VERSION 5.7 ;
  NOWIREEXTENSIONATPIN ON ;
  DIVIDERCHAR "/" ;
  BUSBITCHARS "[]" ;
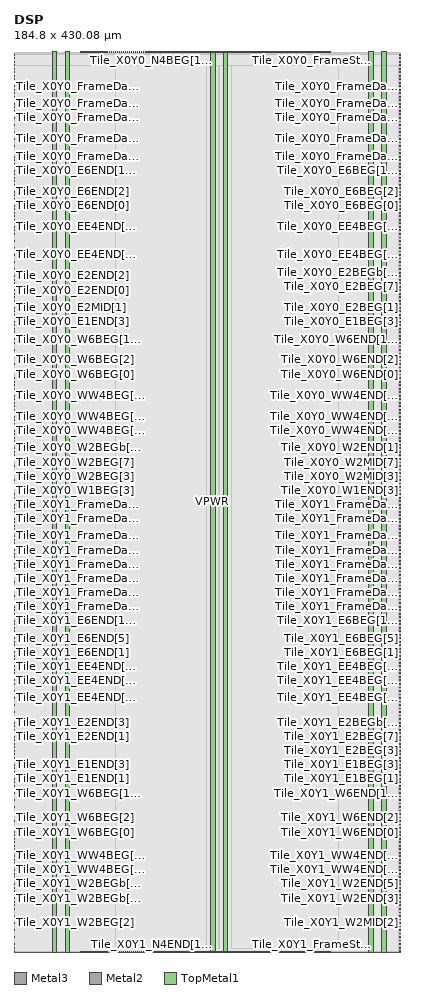
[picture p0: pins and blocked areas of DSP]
MACRO DSP
  CLASS BLOCK ;
  FOREIGN DSP ;
  ORIGIN 0.000 0.000 ;
  SIZE 184.800 BY 430.080 ;
  PIN Tile_X0Y0_E1BEG[0]
    DIRECTION OUTPUT ;
    USE SIGNAL ;
    ANTENNADIFFAREA 0.708600 ;
    PORT
      LAYER Metal3 ;
        RECT 184.400 295.900 184.800 296.300 ;
    END
  END Tile_X0Y0_E1BEG[0]
  PIN Tile_X0Y0_E1BEG[1]
    DIRECTION OUTPUT ;
    USE SIGNAL ;
    ANTENNADIFFAREA 0.708600 ;
    PORT
      LAYER Metal3 ;
        RECT 184.400 297.580 184.800 297.980 ;
    END
  END Tile_X0Y0_E1BEG[1]
  PIN Tile_X0Y0_E1BEG[2]
    DIRECTION OUTPUT ;
    USE SIGNAL ;
    ANTENNADIFFAREA 0.708600 ;
    PORT
      LAYER Metal3 ;
        RECT 184.400 299.260 184.800 299.660 ;
    END
  END Tile_X0Y0_E1BEG[2]
  PIN Tile_X0Y0_E1BEG[3]
    DIRECTION OUTPUT ;
    USE SIGNAL ;
    ANTENNADIFFAREA 0.708600 ;
    PORT
      LAYER Metal3 ;
        RECT 184.400 300.940 184.800 301.340 ;
    END
  END Tile_X0Y0_E1BEG[3]
  PIN Tile_X0Y0_E1END[0]
    DIRECTION INPUT ;
    USE SIGNAL ;
    ANTENNAGATEAREA 0.668200 ;
    PORT
      LAYER Metal3 ;
        RECT 0.000 295.900 0.400 296.300 ;
    END
  END Tile_X0Y0_E1END[0]
  PIN Tile_X0Y0_E1END[1]
    DIRECTION INPUT ;
    USE SIGNAL ;
    ANTENNAGATEAREA 1.834300 ;
    PORT
      LAYER Metal3 ;
        RECT 0.000 297.580 0.400 297.980 ;
    END
  END Tile_X0Y0_E1END[1]
  PIN Tile_X0Y0_E1END[2]
    DIRECTION INPUT ;
    USE SIGNAL ;
    ANTENNAGATEAREA 2.345200 ;
    PORT
      LAYER Metal3 ;
        RECT 0.000 299.260 0.400 299.660 ;
    END
  END Tile_X0Y0_E1END[2]
  PIN Tile_X0Y0_E1END[3]
    DIRECTION INPUT ;
    USE SIGNAL ;
    ANTENNAGATEAREA 1.336400 ;
    PORT
      LAYER Metal3 ;
        RECT 0.000 300.940 0.400 301.340 ;
    END
  END Tile_X0Y0_E1END[3]
  PIN Tile_X0Y0_E2BEG[0]
    DIRECTION OUTPUT ;
    USE SIGNAL ;
    ANTENNADIFFAREA 0.708600 ;
    PORT
      LAYER Metal3 ;
        RECT 184.400 302.620 184.800 303.020 ;
    END
  END Tile_X0Y0_E2BEG[0]
  PIN Tile_X0Y0_E2BEG[1]
    DIRECTION OUTPUT ;
    USE SIGNAL ;
    ANTENNADIFFAREA 0.708600 ;
    PORT
      LAYER Metal3 ;
        RECT 184.400 304.300 184.800 304.700 ;
    END
  END Tile_X0Y0_E2BEG[1]
  PIN Tile_X0Y0_E2BEG[2]
    DIRECTION OUTPUT ;
    USE SIGNAL ;
    ANTENNADIFFAREA 0.708600 ;
    PORT
      LAYER Metal3 ;
        RECT 184.400 305.980 184.800 306.380 ;
    END
  END Tile_X0Y0_E2BEG[2]
  PIN Tile_X0Y0_E2BEG[3]
    DIRECTION OUTPUT ;
    USE SIGNAL ;
    ANTENNADIFFAREA 0.708600 ;
    PORT
      LAYER Metal3 ;
        RECT 184.400 307.660 184.800 308.060 ;
    END
  END Tile_X0Y0_E2BEG[3]
  PIN Tile_X0Y0_E2BEG[4]
    DIRECTION OUTPUT ;
    USE SIGNAL ;
    ANTENNADIFFAREA 0.708600 ;
    PORT
      LAYER Metal3 ;
        RECT 184.400 309.340 184.800 309.740 ;
    END
  END Tile_X0Y0_E2BEG[4]
  PIN Tile_X0Y0_E2BEG[5]
    DIRECTION OUTPUT ;
    USE SIGNAL ;
    ANTENNADIFFAREA 0.708600 ;
    PORT
      LAYER Metal3 ;
        RECT 184.400 311.020 184.800 311.420 ;
    END
  END Tile_X0Y0_E2BEG[5]
  PIN Tile_X0Y0_E2BEG[6]
    DIRECTION OUTPUT ;
    USE SIGNAL ;
    ANTENNADIFFAREA 0.708600 ;
    PORT
      LAYER Metal3 ;
        RECT 184.400 312.700 184.800 313.100 ;
    END
  END Tile_X0Y0_E2BEG[6]
  PIN Tile_X0Y0_E2BEG[7]
    DIRECTION OUTPUT ;
    USE SIGNAL ;
    ANTENNADIFFAREA 0.708600 ;
    PORT
      LAYER Metal3 ;
        RECT 184.400 314.380 184.800 314.780 ;
    END
  END Tile_X0Y0_E2BEG[7]
  PIN Tile_X0Y0_E2BEGb[0]
    DIRECTION OUTPUT ;
    USE SIGNAL ;
    ANTENNADIFFAREA 0.708600 ;
    PORT
      LAYER Metal3 ;
        RECT 184.400 316.060 184.800 316.460 ;
    END
  END Tile_X0Y0_E2BEGb[0]
  PIN Tile_X0Y0_E2BEGb[1]
    DIRECTION OUTPUT ;
    USE SIGNAL ;
    ANTENNADIFFAREA 0.708600 ;
    PORT
      LAYER Metal3 ;
        RECT 184.400 317.740 184.800 318.140 ;
    END
  END Tile_X0Y0_E2BEGb[1]
  PIN Tile_X0Y0_E2BEGb[2]
    DIRECTION OUTPUT ;
    USE SIGNAL ;
    ANTENNADIFFAREA 0.708600 ;
    PORT
      LAYER Metal3 ;
        RECT 184.400 319.420 184.800 319.820 ;
    END
  END Tile_X0Y0_E2BEGb[2]
  PIN Tile_X0Y0_E2BEGb[3]
    DIRECTION OUTPUT ;
    USE SIGNAL ;
    ANTENNADIFFAREA 0.708600 ;
    PORT
      LAYER Metal3 ;
        RECT 184.400 321.100 184.800 321.500 ;
    END
  END Tile_X0Y0_E2BEGb[3]
  PIN Tile_X0Y0_E2BEGb[4]
    DIRECTION OUTPUT ;
    USE SIGNAL ;
    ANTENNADIFFAREA 0.708600 ;
    PORT
      LAYER Metal3 ;
        RECT 184.400 322.780 184.800 323.180 ;
    END
  END Tile_X0Y0_E2BEGb[4]
  PIN Tile_X0Y0_E2BEGb[5]
    DIRECTION OUTPUT ;
    USE SIGNAL ;
    ANTENNADIFFAREA 0.708600 ;
    PORT
      LAYER Metal3 ;
        RECT 184.400 324.460 184.800 324.860 ;
    END
  END Tile_X0Y0_E2BEGb[5]
  PIN Tile_X0Y0_E2BEGb[6]
    DIRECTION OUTPUT ;
    USE SIGNAL ;
    ANTENNADIFFAREA 0.708600 ;
    PORT
      LAYER Metal3 ;
        RECT 184.400 326.140 184.800 326.540 ;
    END
  END Tile_X0Y0_E2BEGb[6]
  PIN Tile_X0Y0_E2BEGb[7]
    DIRECTION OUTPUT ;
    USE SIGNAL ;
    ANTENNADIFFAREA 0.708600 ;
    PORT
      LAYER Metal3 ;
        RECT 184.400 327.820 184.800 328.220 ;
    END
  END Tile_X0Y0_E2BEGb[7]
  PIN Tile_X0Y0_E2END[0]
    DIRECTION INPUT ;
    USE SIGNAL ;
    ANTENNAGATEAREA 0.938600 ;
    PORT
      LAYER Metal3 ;
        RECT 0.000 316.060 0.400 316.460 ;
    END
  END Tile_X0Y0_E2END[0]
  PIN Tile_X0Y0_E2END[1]
    DIRECTION INPUT ;
    USE SIGNAL ;
    ANTENNAGATEAREA 0.894400 ;
    PORT
      LAYER Metal3 ;
        RECT 0.000 317.740 0.400 318.140 ;
    END
  END Tile_X0Y0_E2END[1]
  PIN Tile_X0Y0_E2END[2]
    DIRECTION INPUT ;
    USE SIGNAL ;
    ANTENNAGATEAREA 1.501500 ;
    PORT
      LAYER Metal3 ;
        RECT 0.000 319.420 0.400 319.820 ;
    END
  END Tile_X0Y0_E2END[2]
  PIN Tile_X0Y0_E2END[3]
    DIRECTION INPUT ;
    USE SIGNAL ;
    ANTENNAGATEAREA 1.714700 ;
    PORT
      LAYER Metal3 ;
        RECT 0.000 321.100 0.400 321.500 ;
    END
  END Tile_X0Y0_E2END[3]
  PIN Tile_X0Y0_E2END[4]
    DIRECTION INPUT ;
    USE SIGNAL ;
    ANTENNAGATEAREA 1.066000 ;
    PORT
      LAYER Metal3 ;
        RECT 0.000 322.780 0.400 323.180 ;
    END
  END Tile_X0Y0_E2END[4]
  PIN Tile_X0Y0_E2END[5]
    DIRECTION INPUT ;
    USE SIGNAL ;
    ANTENNAGATEAREA 1.378000 ;
    PORT
      LAYER Metal3 ;
        RECT 0.000 324.460 0.400 324.860 ;
    END
  END Tile_X0Y0_E2END[5]
  PIN Tile_X0Y0_E2END[6]
    DIRECTION INPUT ;
    USE SIGNAL ;
    ANTENNAGATEAREA 1.279200 ;
    PORT
      LAYER Metal3 ;
        RECT 0.000 326.140 0.400 326.540 ;
    END
  END Tile_X0Y0_E2END[6]
  PIN Tile_X0Y0_E2END[7]
    DIRECTION INPUT ;
    USE SIGNAL ;
    ANTENNAGATEAREA 1.180400 ;
    PORT
      LAYER Metal3 ;
        RECT 0.000 327.820 0.400 328.220 ;
    END
  END Tile_X0Y0_E2END[7]
  PIN Tile_X0Y0_E2MID[0]
    DIRECTION INPUT ;
    USE SIGNAL ;
    ANTENNAGATEAREA 0.914700 ;
    PORT
      LAYER Metal3 ;
        RECT 0.000 302.620 0.400 303.020 ;
    END
  END Tile_X0Y0_E2MID[0]
  PIN Tile_X0Y0_E2MID[1]
    DIRECTION INPUT ;
    USE SIGNAL ;
    ANTENNAGATEAREA 0.968500 ;
    PORT
      LAYER Metal3 ;
        RECT 0.000 304.300 0.400 304.700 ;
    END
  END Tile_X0Y0_E2MID[1]
  PIN Tile_X0Y0_E2MID[2]
    DIRECTION INPUT ;
    USE SIGNAL ;
    ANTENNAGATEAREA 0.848900 ;
    PORT
      LAYER Metal3 ;
        RECT 0.000 305.980 0.400 306.380 ;
    END
  END Tile_X0Y0_E2MID[2]
  PIN Tile_X0Y0_E2MID[3]
    DIRECTION INPUT ;
    USE SIGNAL ;
    ANTENNAGATEAREA 1.059500 ;
    PORT
      LAYER Metal3 ;
        RECT 0.000 307.660 0.400 308.060 ;
    END
  END Tile_X0Y0_E2MID[3]
  PIN Tile_X0Y0_E2MID[4]
    DIRECTION INPUT ;
    USE SIGNAL ;
    ANTENNAGATEAREA 4.104100 ;
    ANTENNADIFFAREA 10.077000 ;
    PORT
      LAYER Metal3 ;
        RECT 0.000 309.340 0.400 309.740 ;
    END
  END Tile_X0Y0_E2MID[4]
  PIN Tile_X0Y0_E2MID[5]
    DIRECTION INPUT ;
    USE SIGNAL ;
    ANTENNAGATEAREA 1.127900 ;
    PORT
      LAYER Metal3 ;
        RECT 0.000 311.020 0.400 311.420 ;
    END
  END Tile_X0Y0_E2MID[5]
  PIN Tile_X0Y0_E2MID[6]
    DIRECTION INPUT ;
    USE SIGNAL ;
    ANTENNAGATEAREA 0.848900 ;
    PORT
      LAYER Metal3 ;
        RECT 0.000 312.700 0.400 313.100 ;
    END
  END Tile_X0Y0_E2MID[6]
  PIN Tile_X0Y0_E2MID[7]
    DIRECTION INPUT ;
    USE SIGNAL ;
    ANTENNAGATEAREA 1.062100 ;
    PORT
      LAYER Metal3 ;
        RECT 0.000 314.380 0.400 314.780 ;
    END
  END Tile_X0Y0_E2MID[7]
  PIN Tile_X0Y0_E6BEG[0]
    DIRECTION OUTPUT ;
    USE SIGNAL ;
    ANTENNADIFFAREA 0.708600 ;
    PORT
      LAYER Metal3 ;
        RECT 184.400 356.380 184.800 356.780 ;
    END
  END Tile_X0Y0_E6BEG[0]
  PIN Tile_X0Y0_E6BEG[10]
    DIRECTION OUTPUT ;
    USE SIGNAL ;
    ANTENNADIFFAREA 0.708600 ;
    PORT
      LAYER Metal3 ;
        RECT 184.400 373.180 184.800 373.580 ;
    END
  END Tile_X0Y0_E6BEG[10]
  PIN Tile_X0Y0_E6BEG[11]
    DIRECTION OUTPUT ;
    USE SIGNAL ;
    ANTENNADIFFAREA 0.708600 ;
    PORT
      LAYER Metal3 ;
        RECT 184.400 374.860 184.800 375.260 ;
    END
  END Tile_X0Y0_E6BEG[11]
  PIN Tile_X0Y0_E6BEG[1]
    DIRECTION OUTPUT ;
    USE SIGNAL ;
    ANTENNADIFFAREA 0.708600 ;
    PORT
      LAYER Metal3 ;
        RECT 184.400 358.060 184.800 358.460 ;
    END
  END Tile_X0Y0_E6BEG[1]
  PIN Tile_X0Y0_E6BEG[2]
    DIRECTION OUTPUT ;
    USE SIGNAL ;
    ANTENNADIFFAREA 0.708600 ;
    PORT
      LAYER Metal3 ;
        RECT 184.400 359.740 184.800 360.140 ;
    END
  END Tile_X0Y0_E6BEG[2]
  PIN Tile_X0Y0_E6BEG[3]
    DIRECTION OUTPUT ;
    USE SIGNAL ;
    ANTENNADIFFAREA 0.708600 ;
    PORT
      LAYER Metal3 ;
        RECT 184.400 361.420 184.800 361.820 ;
    END
  END Tile_X0Y0_E6BEG[3]
  PIN Tile_X0Y0_E6BEG[4]
    DIRECTION OUTPUT ;
    USE SIGNAL ;
    ANTENNADIFFAREA 0.708600 ;
    PORT
      LAYER Metal3 ;
        RECT 184.400 363.100 184.800 363.500 ;
    END
  END Tile_X0Y0_E6BEG[4]
  PIN Tile_X0Y0_E6BEG[5]
    DIRECTION OUTPUT ;
    USE SIGNAL ;
    ANTENNADIFFAREA 0.708600 ;
    PORT
      LAYER Metal3 ;
        RECT 184.400 364.780 184.800 365.180 ;
    END
  END Tile_X0Y0_E6BEG[5]
  PIN Tile_X0Y0_E6BEG[6]
    DIRECTION OUTPUT ;
    USE SIGNAL ;
    ANTENNADIFFAREA 0.708600 ;
    PORT
      LAYER Metal3 ;
        RECT 184.400 366.460 184.800 366.860 ;
    END
  END Tile_X0Y0_E6BEG[6]
  PIN Tile_X0Y0_E6BEG[7]
    DIRECTION OUTPUT ;
    USE SIGNAL ;
    ANTENNADIFFAREA 0.708600 ;
    PORT
      LAYER Metal3 ;
        RECT 184.400 368.140 184.800 368.540 ;
    END
  END Tile_X0Y0_E6BEG[7]
  PIN Tile_X0Y0_E6BEG[8]
    DIRECTION OUTPUT ;
    USE SIGNAL ;
    ANTENNADIFFAREA 0.708600 ;
    PORT
      LAYER Metal3 ;
        RECT 184.400 369.820 184.800 370.220 ;
    END
  END Tile_X0Y0_E6BEG[8]
  PIN Tile_X0Y0_E6BEG[9]
    DIRECTION OUTPUT ;
    USE SIGNAL ;
    ANTENNADIFFAREA 0.708600 ;
    PORT
      LAYER Metal3 ;
        RECT 184.400 371.500 184.800 371.900 ;
    END
  END Tile_X0Y0_E6BEG[9]
  PIN Tile_X0Y0_E6END[0]
    DIRECTION INPUT ;
    USE SIGNAL ;
    ANTENNAGATEAREA 2.567500 ;
    PORT
      LAYER Metal3 ;
        RECT 0.000 356.380 0.400 356.780 ;
    END
  END Tile_X0Y0_E6END[0]
  PIN Tile_X0Y0_E6END[10]
    DIRECTION INPUT ;
    USE SIGNAL ;
    ANTENNAGATEAREA 0.789100 ;
    ANTENNADIFFAREA 2.015400 ;
    PORT
      LAYER Metal3 ;
        RECT 0.000 373.180 0.400 373.580 ;
    END
  END Tile_X0Y0_E6END[10]
  PIN Tile_X0Y0_E6END[11]
    DIRECTION INPUT ;
    USE SIGNAL ;
    ANTENNAGATEAREA 0.180700 ;
    PORT
      LAYER Metal3 ;
        RECT 0.000 374.860 0.400 375.260 ;
    END
  END Tile_X0Y0_E6END[11]
  PIN Tile_X0Y0_E6END[1]
    DIRECTION INPUT ;
    USE SIGNAL ;
    ANTENNAGATEAREA 2.764900 ;
    PORT
      LAYER Metal3 ;
        RECT 0.000 358.060 0.400 358.460 ;
    END
  END Tile_X0Y0_E6END[1]
  PIN Tile_X0Y0_E6END[2]
    DIRECTION INPUT ;
    USE SIGNAL ;
    ANTENNAGATEAREA 0.180700 ;
    PORT
      LAYER Metal3 ;
        RECT 0.000 359.740 0.400 360.140 ;
    END
  END Tile_X0Y0_E6END[2]
  PIN Tile_X0Y0_E6END[3]
    DIRECTION INPUT ;
    USE SIGNAL ;
    ANTENNAGATEAREA 0.789100 ;
    ANTENNADIFFAREA 2.015400 ;
    PORT
      LAYER Metal3 ;
        RECT 0.000 361.420 0.400 361.820 ;
    END
  END Tile_X0Y0_E6END[3]
  PIN Tile_X0Y0_E6END[4]
    DIRECTION INPUT ;
    USE SIGNAL ;
    ANTENNAGATEAREA 0.789100 ;
    ANTENNADIFFAREA 2.015400 ;
    PORT
      LAYER Metal3 ;
        RECT 0.000 363.100 0.400 363.500 ;
    END
  END Tile_X0Y0_E6END[4]
  PIN Tile_X0Y0_E6END[5]
    DIRECTION INPUT ;
    USE SIGNAL ;
    ANTENNAGATEAREA 0.789100 ;
    ANTENNADIFFAREA 2.015400 ;
    PORT
      LAYER Metal3 ;
        RECT 0.000 364.780 0.400 365.180 ;
    END
  END Tile_X0Y0_E6END[5]
  PIN Tile_X0Y0_E6END[6]
    DIRECTION INPUT ;
    USE SIGNAL ;
    ANTENNAGATEAREA 0.180700 ;
    PORT
      LAYER Metal3 ;
        RECT 0.000 366.460 0.400 366.860 ;
    END
  END Tile_X0Y0_E6END[6]
  PIN Tile_X0Y0_E6END[7]
    DIRECTION INPUT ;
    USE SIGNAL ;
    ANTENNAGATEAREA 0.180700 ;
    PORT
      LAYER Metal3 ;
        RECT 0.000 368.140 0.400 368.540 ;
    END
  END Tile_X0Y0_E6END[7]
  PIN Tile_X0Y0_E6END[8]
    DIRECTION INPUT ;
    USE SIGNAL ;
    ANTENNAGATEAREA 0.789100 ;
    ANTENNADIFFAREA 2.015400 ;
    PORT
      LAYER Metal3 ;
        RECT 0.000 369.820 0.400 370.220 ;
    END
  END Tile_X0Y0_E6END[8]
  PIN Tile_X0Y0_E6END[9]
    DIRECTION INPUT ;
    USE SIGNAL ;
    ANTENNAGATEAREA 0.180700 ;
    PORT
      LAYER Metal3 ;
        RECT 0.000 371.500 0.400 371.900 ;
    END
  END Tile_X0Y0_E6END[9]
  PIN Tile_X0Y0_EE4BEG[0]
    DIRECTION OUTPUT ;
    USE SIGNAL ;
    ANTENNADIFFAREA 0.708600 ;
    PORT
      LAYER Metal3 ;
        RECT 184.400 329.500 184.800 329.900 ;
    END
  END Tile_X0Y0_EE4BEG[0]
  PIN Tile_X0Y0_EE4BEG[10]
    DIRECTION OUTPUT ;
    USE SIGNAL ;
    ANTENNADIFFAREA 0.708600 ;
    PORT
      LAYER Metal3 ;
        RECT 184.400 346.300 184.800 346.700 ;
    END
  END Tile_X0Y0_EE4BEG[10]
  PIN Tile_X0Y0_EE4BEG[11]
    DIRECTION OUTPUT ;
    USE SIGNAL ;
    ANTENNADIFFAREA 0.708600 ;
    PORT
      LAYER Metal3 ;
        RECT 184.400 347.980 184.800 348.380 ;
    END
  END Tile_X0Y0_EE4BEG[11]
  PIN Tile_X0Y0_EE4BEG[12]
    DIRECTION OUTPUT ;
    USE SIGNAL ;
    ANTENNADIFFAREA 0.708600 ;
    PORT
      LAYER Metal3 ;
        RECT 184.400 349.660 184.800 350.060 ;
    END
  END Tile_X0Y0_EE4BEG[12]
  PIN Tile_X0Y0_EE4BEG[13]
    DIRECTION OUTPUT ;
    USE SIGNAL ;
    ANTENNADIFFAREA 0.708600 ;
    PORT
      LAYER Metal3 ;
        RECT 184.400 351.340 184.800 351.740 ;
    END
  END Tile_X0Y0_EE4BEG[13]
  PIN Tile_X0Y0_EE4BEG[14]
    DIRECTION OUTPUT ;
    USE SIGNAL ;
    ANTENNADIFFAREA 0.708600 ;
    PORT
      LAYER Metal3 ;
        RECT 184.400 353.020 184.800 353.420 ;
    END
  END Tile_X0Y0_EE4BEG[14]
  PIN Tile_X0Y0_EE4BEG[15]
    DIRECTION OUTPUT ;
    USE SIGNAL ;
    ANTENNADIFFAREA 0.708600 ;
    PORT
      LAYER Metal3 ;
        RECT 184.400 354.700 184.800 355.100 ;
    END
  END Tile_X0Y0_EE4BEG[15]
  PIN Tile_X0Y0_EE4BEG[1]
    DIRECTION OUTPUT ;
    USE SIGNAL ;
    ANTENNADIFFAREA 0.708600 ;
    PORT
      LAYER Metal3 ;
        RECT 184.400 331.180 184.800 331.580 ;
    END
  END Tile_X0Y0_EE4BEG[1]
  PIN Tile_X0Y0_EE4BEG[2]
    DIRECTION OUTPUT ;
    USE SIGNAL ;
    ANTENNADIFFAREA 0.708600 ;
    PORT
      LAYER Metal3 ;
        RECT 184.400 332.860 184.800 333.260 ;
    END
  END Tile_X0Y0_EE4BEG[2]
  PIN Tile_X0Y0_EE4BEG[3]
    DIRECTION OUTPUT ;
    USE SIGNAL ;
    ANTENNADIFFAREA 0.708600 ;
    PORT
      LAYER Metal3 ;
        RECT 184.400 334.540 184.800 334.940 ;
    END
  END Tile_X0Y0_EE4BEG[3]
  PIN Tile_X0Y0_EE4BEG[4]
    DIRECTION OUTPUT ;
    USE SIGNAL ;
    ANTENNADIFFAREA 0.708600 ;
    PORT
      LAYER Metal3 ;
        RECT 184.400 336.220 184.800 336.620 ;
    END
  END Tile_X0Y0_EE4BEG[4]
  PIN Tile_X0Y0_EE4BEG[5]
    DIRECTION OUTPUT ;
    USE SIGNAL ;
    ANTENNADIFFAREA 0.708600 ;
    PORT
      LAYER Metal3 ;
        RECT 184.400 337.900 184.800 338.300 ;
    END
  END Tile_X0Y0_EE4BEG[5]
  PIN Tile_X0Y0_EE4BEG[6]
    DIRECTION OUTPUT ;
    USE SIGNAL ;
    ANTENNADIFFAREA 0.708600 ;
    PORT
      LAYER Metal3 ;
        RECT 184.400 339.580 184.800 339.980 ;
    END
  END Tile_X0Y0_EE4BEG[6]
  PIN Tile_X0Y0_EE4BEG[7]
    DIRECTION OUTPUT ;
    USE SIGNAL ;
    ANTENNADIFFAREA 0.708600 ;
    PORT
      LAYER Metal3 ;
        RECT 184.400 341.260 184.800 341.660 ;
    END
  END Tile_X0Y0_EE4BEG[7]
  PIN Tile_X0Y0_EE4BEG[8]
    DIRECTION OUTPUT ;
    USE SIGNAL ;
    ANTENNADIFFAREA 0.708600 ;
    PORT
      LAYER Metal3 ;
        RECT 184.400 342.940 184.800 343.340 ;
    END
  END Tile_X0Y0_EE4BEG[8]
  PIN Tile_X0Y0_EE4BEG[9]
    DIRECTION OUTPUT ;
    USE SIGNAL ;
    ANTENNADIFFAREA 0.708600 ;
    PORT
      LAYER Metal3 ;
        RECT 184.400 344.620 184.800 345.020 ;
    END
  END Tile_X0Y0_EE4BEG[9]
  PIN Tile_X0Y0_EE4END[0]
    DIRECTION INPUT ;
    USE SIGNAL ;
    ANTENNAGATEAREA 0.696800 ;
    PORT
      LAYER Metal3 ;
        RECT 0.000 329.500 0.400 329.900 ;
    END
  END Tile_X0Y0_EE4END[0]
  PIN Tile_X0Y0_EE4END[10]
    DIRECTION INPUT ;
    USE SIGNAL ;
    ANTENNAGATEAREA 0.180700 ;
    PORT
      LAYER Metal3 ;
        RECT 0.000 346.300 0.400 346.700 ;
    END
  END Tile_X0Y0_EE4END[10]
  PIN Tile_X0Y0_EE4END[11]
    DIRECTION INPUT ;
    USE SIGNAL ;
    ANTENNAGATEAREA 0.789100 ;
    ANTENNADIFFAREA 2.015400 ;
    PORT
      LAYER Metal3 ;
        RECT 0.000 347.980 0.400 348.380 ;
    END
  END Tile_X0Y0_EE4END[11]
  PIN Tile_X0Y0_EE4END[12]
    DIRECTION INPUT ;
    USE SIGNAL ;
    ANTENNAGATEAREA 0.789100 ;
    ANTENNADIFFAREA 2.015400 ;
    PORT
      LAYER Metal3 ;
        RECT 0.000 349.660 0.400 350.060 ;
    END
  END Tile_X0Y0_EE4END[12]
  PIN Tile_X0Y0_EE4END[13]
    DIRECTION INPUT ;
    USE SIGNAL ;
    ANTENNAGATEAREA 0.789100 ;
    ANTENNADIFFAREA 2.015400 ;
    PORT
      LAYER Metal3 ;
        RECT 0.000 351.340 0.400 351.740 ;
    END
  END Tile_X0Y0_EE4END[13]
  PIN Tile_X0Y0_EE4END[14]
    DIRECTION INPUT ;
    USE SIGNAL ;
    ANTENNAGATEAREA 0.180700 ;
    PORT
      LAYER Metal3 ;
        RECT 0.000 353.020 0.400 353.420 ;
    END
  END Tile_X0Y0_EE4END[14]
  PIN Tile_X0Y0_EE4END[15]
    DIRECTION INPUT ;
    USE SIGNAL ;
    ANTENNAGATEAREA 0.180700 ;
    PORT
      LAYER Metal3 ;
        RECT 0.000 354.700 0.400 355.100 ;
    END
  END Tile_X0Y0_EE4END[15]
  PIN Tile_X0Y0_EE4END[1]
    DIRECTION INPUT ;
    USE SIGNAL ;
    ANTENNAGATEAREA 0.681200 ;
    PORT
      LAYER Metal3 ;
        RECT 0.000 331.180 0.400 331.580 ;
    END
  END Tile_X0Y0_EE4END[1]
  PIN Tile_X0Y0_EE4END[2]
    DIRECTION INPUT ;
    USE SIGNAL ;
    ANTENNAGATEAREA 0.705400 ;
    PORT
      LAYER Metal3 ;
        RECT 0.000 332.860 0.400 333.260 ;
    END
  END Tile_X0Y0_EE4END[2]
  PIN Tile_X0Y0_EE4END[3]
    DIRECTION INPUT ;
    USE SIGNAL ;
    ANTENNAGATEAREA 0.393900 ;
    PORT
      LAYER Metal3 ;
        RECT 0.000 334.540 0.400 334.940 ;
    END
  END Tile_X0Y0_EE4END[3]
  PIN Tile_X0Y0_EE4END[4]
    DIRECTION INPUT ;
    USE SIGNAL ;
    ANTENNAGATEAREA 0.180700 ;
    PORT
      LAYER Metal3 ;
        RECT 0.000 336.220 0.400 336.620 ;
    END
  END Tile_X0Y0_EE4END[4]
  PIN Tile_X0Y0_EE4END[5]
    DIRECTION INPUT ;
    USE SIGNAL ;
    ANTENNAGATEAREA 0.180700 ;
    PORT
      LAYER Metal3 ;
        RECT 0.000 337.900 0.400 338.300 ;
    END
  END Tile_X0Y0_EE4END[5]
  PIN Tile_X0Y0_EE4END[6]
    DIRECTION INPUT ;
    USE SIGNAL ;
    ANTENNAGATEAREA 0.180700 ;
    PORT
      LAYER Metal3 ;
        RECT 0.000 339.580 0.400 339.980 ;
    END
  END Tile_X0Y0_EE4END[6]
  PIN Tile_X0Y0_EE4END[7]
    DIRECTION INPUT ;
    USE SIGNAL ;
    ANTENNAGATEAREA 0.180700 ;
    PORT
      LAYER Metal3 ;
        RECT 0.000 341.260 0.400 341.660 ;
    END
  END Tile_X0Y0_EE4END[7]
  PIN Tile_X0Y0_EE4END[8]
    DIRECTION INPUT ;
    USE SIGNAL ;
    ANTENNAGATEAREA 0.789100 ;
    ANTENNADIFFAREA 2.015400 ;
    PORT
      LAYER Metal3 ;
        RECT 0.000 342.940 0.400 343.340 ;
    END
  END Tile_X0Y0_EE4END[8]
  PIN Tile_X0Y0_EE4END[9]
    DIRECTION INPUT ;
    USE SIGNAL ;
    ANTENNAGATEAREA 0.180700 ;
    PORT
      LAYER Metal3 ;
        RECT 0.000 344.620 0.400 345.020 ;
    END
  END Tile_X0Y0_EE4END[9]
  PIN Tile_X0Y0_FrameData[0]
    DIRECTION INPUT ;
    USE SIGNAL ;
    ANTENNAGATEAREA 2.349100 ;
    PORT
      LAYER Metal3 ;
        RECT 0.000 376.540 0.400 376.940 ;
    END
  END Tile_X0Y0_FrameData[0]
  PIN Tile_X0Y0_FrameData[10]
    DIRECTION INPUT ;
    USE SIGNAL ;
    ANTENNAGATEAREA 2.529800 ;
    PORT
      LAYER Metal3 ;
        RECT 0.000 393.340 0.400 393.740 ;
    END
  END Tile_X0Y0_FrameData[10]
  PIN Tile_X0Y0_FrameData[11]
    DIRECTION INPUT ;
    USE SIGNAL ;
    ANTENNAGATEAREA 2.529800 ;
    PORT
      LAYER Metal3 ;
        RECT 0.000 395.020 0.400 395.420 ;
    END
  END Tile_X0Y0_FrameData[11]
  PIN Tile_X0Y0_FrameData[12]
    DIRECTION INPUT ;
    USE SIGNAL ;
    ANTENNAGATEAREA 2.529800 ;
    PORT
      LAYER Metal3 ;
        RECT 0.000 396.700 0.400 397.100 ;
    END
  END Tile_X0Y0_FrameData[12]
  PIN Tile_X0Y0_FrameData[13]
    DIRECTION INPUT ;
    USE SIGNAL ;
    ANTENNAGATEAREA 2.529800 ;
    PORT
      LAYER Metal3 ;
        RECT 0.000 398.380 0.400 398.780 ;
    END
  END Tile_X0Y0_FrameData[13]
  PIN Tile_X0Y0_FrameData[14]
    DIRECTION INPUT ;
    USE SIGNAL ;
    ANTENNAGATEAREA 2.529800 ;
    PORT
      LAYER Metal3 ;
        RECT 0.000 400.060 0.400 400.460 ;
    END
  END Tile_X0Y0_FrameData[14]
  PIN Tile_X0Y0_FrameData[15]
    DIRECTION INPUT ;
    USE SIGNAL ;
    ANTENNAGATEAREA 2.529800 ;
    PORT
      LAYER Metal3 ;
        RECT 0.000 401.740 0.400 402.140 ;
    END
  END Tile_X0Y0_FrameData[15]
  PIN Tile_X0Y0_FrameData[16]
    DIRECTION INPUT ;
    USE SIGNAL ;
    ANTENNAGATEAREA 2.529800 ;
    PORT
      LAYER Metal3 ;
        RECT 0.000 403.420 0.400 403.820 ;
    END
  END Tile_X0Y0_FrameData[16]
  PIN Tile_X0Y0_FrameData[17]
    DIRECTION INPUT ;
    USE SIGNAL ;
    ANTENNAGATEAREA 2.529800 ;
    PORT
      LAYER Metal3 ;
        RECT 0.000 405.100 0.400 405.500 ;
    END
  END Tile_X0Y0_FrameData[17]
  PIN Tile_X0Y0_FrameData[18]
    DIRECTION INPUT ;
    USE SIGNAL ;
    ANTENNAGATEAREA 2.529800 ;
    PORT
      LAYER Metal3 ;
        RECT 0.000 406.780 0.400 407.180 ;
    END
  END Tile_X0Y0_FrameData[18]
  PIN Tile_X0Y0_FrameData[19]
    DIRECTION INPUT ;
    USE SIGNAL ;
    ANTENNAGATEAREA 2.529800 ;
    PORT
      LAYER Metal3 ;
        RECT 0.000 408.460 0.400 408.860 ;
    END
  END Tile_X0Y0_FrameData[19]
  PIN Tile_X0Y0_FrameData[1]
    DIRECTION INPUT ;
    USE SIGNAL ;
    ANTENNAGATEAREA 2.349100 ;
    PORT
      LAYER Metal3 ;
        RECT 0.000 378.220 0.400 378.620 ;
    END
  END Tile_X0Y0_FrameData[1]
  PIN Tile_X0Y0_FrameData[20]
    DIRECTION INPUT ;
    USE SIGNAL ;
    ANTENNAGATEAREA 2.529800 ;
    PORT
      LAYER Metal3 ;
        RECT 0.000 410.140 0.400 410.540 ;
    END
  END Tile_X0Y0_FrameData[20]
  PIN Tile_X0Y0_FrameData[21]
    DIRECTION INPUT ;
    USE SIGNAL ;
    ANTENNAGATEAREA 2.529800 ;
    PORT
      LAYER Metal3 ;
        RECT 0.000 411.820 0.400 412.220 ;
    END
  END Tile_X0Y0_FrameData[21]
  PIN Tile_X0Y0_FrameData[22]
    DIRECTION INPUT ;
    USE SIGNAL ;
    ANTENNAGATEAREA 2.529800 ;
    PORT
      LAYER Metal3 ;
        RECT 0.000 413.500 0.400 413.900 ;
    END
  END Tile_X0Y0_FrameData[22]
  PIN Tile_X0Y0_FrameData[23]
    DIRECTION INPUT ;
    USE SIGNAL ;
    ANTENNAGATEAREA 2.529800 ;
    PORT
      LAYER Metal3 ;
        RECT 0.000 415.180 0.400 415.580 ;
    END
  END Tile_X0Y0_FrameData[23]
  PIN Tile_X0Y0_FrameData[24]
    DIRECTION INPUT ;
    USE SIGNAL ;
    ANTENNAGATEAREA 2.529800 ;
    PORT
      LAYER Metal3 ;
        RECT 0.000 416.860 0.400 417.260 ;
    END
  END Tile_X0Y0_FrameData[24]
  PIN Tile_X0Y0_FrameData[25]
    DIRECTION INPUT ;
    USE SIGNAL ;
    ANTENNAGATEAREA 2.529800 ;
    PORT
      LAYER Metal3 ;
        RECT 0.000 418.540 0.400 418.940 ;
    END
  END Tile_X0Y0_FrameData[25]
  PIN Tile_X0Y0_FrameData[26]
    DIRECTION INPUT ;
    USE SIGNAL ;
    ANTENNAGATEAREA 2.529800 ;
    PORT
      LAYER Metal3 ;
        RECT 0.000 420.220 0.400 420.620 ;
    END
  END Tile_X0Y0_FrameData[26]
  PIN Tile_X0Y0_FrameData[27]
    DIRECTION INPUT ;
    USE SIGNAL ;
    ANTENNAGATEAREA 2.529800 ;
    PORT
      LAYER Metal3 ;
        RECT 0.000 421.900 0.400 422.300 ;
    END
  END Tile_X0Y0_FrameData[27]
  PIN Tile_X0Y0_FrameData[28]
    DIRECTION INPUT ;
    USE SIGNAL ;
    ANTENNAGATEAREA 2.529800 ;
    PORT
      LAYER Metal3 ;
        RECT 0.000 423.580 0.400 423.980 ;
    END
  END Tile_X0Y0_FrameData[28]
  PIN Tile_X0Y0_FrameData[29]
    DIRECTION INPUT ;
    USE SIGNAL ;
    ANTENNAGATEAREA 2.529800 ;
    PORT
      LAYER Metal3 ;
        RECT 0.000 425.260 0.400 425.660 ;
    END
  END Tile_X0Y0_FrameData[29]
  PIN Tile_X0Y0_FrameData[2]
    DIRECTION INPUT ;
    USE SIGNAL ;
    ANTENNAGATEAREA 2.349100 ;
    PORT
      LAYER Metal3 ;
        RECT 0.000 379.900 0.400 380.300 ;
    END
  END Tile_X0Y0_FrameData[2]
  PIN Tile_X0Y0_FrameData[30]
    DIRECTION INPUT ;
    USE SIGNAL ;
    ANTENNAGATEAREA 2.529800 ;
    PORT
      LAYER Metal3 ;
        RECT 0.000 426.940 0.400 427.340 ;
    END
  END Tile_X0Y0_FrameData[30]
  PIN Tile_X0Y0_FrameData[31]
    DIRECTION INPUT ;
    USE SIGNAL ;
    ANTENNAGATEAREA 2.529800 ;
    PORT
      LAYER Metal3 ;
        RECT 0.000 428.620 0.400 429.020 ;
    END
  END Tile_X0Y0_FrameData[31]
  PIN Tile_X0Y0_FrameData[3]
    DIRECTION INPUT ;
    USE SIGNAL ;
    ANTENNAGATEAREA 2.349100 ;
    PORT
      LAYER Metal3 ;
        RECT 0.000 381.580 0.400 381.980 ;
    END
  END Tile_X0Y0_FrameData[3]
  PIN Tile_X0Y0_FrameData[4]
    DIRECTION INPUT ;
    USE SIGNAL ;
    ANTENNAGATEAREA 2.349100 ;
    PORT
      LAYER Metal3 ;
        RECT 0.000 383.260 0.400 383.660 ;
    END
  END Tile_X0Y0_FrameData[4]
  PIN Tile_X0Y0_FrameData[5]
    DIRECTION INPUT ;
    USE SIGNAL ;
    ANTENNAGATEAREA 2.349100 ;
    PORT
      LAYER Metal3 ;
        RECT 0.000 384.940 0.400 385.340 ;
    END
  END Tile_X0Y0_FrameData[5]
  PIN Tile_X0Y0_FrameData[6]
    DIRECTION INPUT ;
    USE SIGNAL ;
    ANTENNAGATEAREA 17.559099 ;
    ANTENNADIFFAREA 50.384998 ;
    PORT
      LAYER Metal3 ;
        RECT 0.000 386.620 0.400 387.020 ;
    END
  END Tile_X0Y0_FrameData[6]
  PIN Tile_X0Y0_FrameData[7]
    DIRECTION INPUT ;
    USE SIGNAL ;
    ANTENNAGATEAREA 2.349100 ;
    PORT
      LAYER Metal3 ;
        RECT 0.000 388.300 0.400 388.700 ;
    END
  END Tile_X0Y0_FrameData[7]
  PIN Tile_X0Y0_FrameData[8]
    DIRECTION INPUT ;
    USE SIGNAL ;
    ANTENNAGATEAREA 2.349100 ;
    PORT
      LAYER Metal3 ;
        RECT 0.000 389.980 0.400 390.380 ;
    END
  END Tile_X0Y0_FrameData[8]
  PIN Tile_X0Y0_FrameData[9]
    DIRECTION INPUT ;
    USE SIGNAL ;
    ANTENNAGATEAREA 2.349100 ;
    PORT
      LAYER Metal3 ;
        RECT 0.000 391.660 0.400 392.060 ;
    END
  END Tile_X0Y0_FrameData[9]
  PIN Tile_X0Y0_FrameData_O[0]
    DIRECTION OUTPUT ;
    USE SIGNAL ;
    ANTENNADIFFAREA 0.708600 ;
    PORT
      LAYER Metal3 ;
        RECT 184.400 376.540 184.800 376.940 ;
    END
  END Tile_X0Y0_FrameData_O[0]
  PIN Tile_X0Y0_FrameData_O[10]
    DIRECTION OUTPUT ;
    USE SIGNAL ;
    ANTENNADIFFAREA 0.708600 ;
    PORT
      LAYER Metal3 ;
        RECT 184.400 393.340 184.800 393.740 ;
    END
  END Tile_X0Y0_FrameData_O[10]
  PIN Tile_X0Y0_FrameData_O[11]
    DIRECTION OUTPUT ;
    USE SIGNAL ;
    ANTENNADIFFAREA 0.708600 ;
    PORT
      LAYER Metal3 ;
        RECT 184.400 395.020 184.800 395.420 ;
    END
  END Tile_X0Y0_FrameData_O[11]
  PIN Tile_X0Y0_FrameData_O[12]
    DIRECTION OUTPUT ;
    USE SIGNAL ;
    ANTENNADIFFAREA 0.708600 ;
    PORT
      LAYER Metal3 ;
        RECT 184.400 396.700 184.800 397.100 ;
    END
  END Tile_X0Y0_FrameData_O[12]
  PIN Tile_X0Y0_FrameData_O[13]
    DIRECTION OUTPUT ;
    USE SIGNAL ;
    ANTENNADIFFAREA 0.708600 ;
    PORT
      LAYER Metal3 ;
        RECT 184.400 398.380 184.800 398.780 ;
    END
  END Tile_X0Y0_FrameData_O[13]
  PIN Tile_X0Y0_FrameData_O[14]
    DIRECTION OUTPUT ;
    USE SIGNAL ;
    ANTENNADIFFAREA 0.708600 ;
    PORT
      LAYER Metal3 ;
        RECT 184.400 400.060 184.800 400.460 ;
    END
  END Tile_X0Y0_FrameData_O[14]
  PIN Tile_X0Y0_FrameData_O[15]
    DIRECTION OUTPUT ;
    USE SIGNAL ;
    ANTENNADIFFAREA 0.708600 ;
    PORT
      LAYER Metal3 ;
        RECT 184.400 401.740 184.800 402.140 ;
    END
  END Tile_X0Y0_FrameData_O[15]
  PIN Tile_X0Y0_FrameData_O[16]
    DIRECTION OUTPUT ;
    USE SIGNAL ;
    ANTENNADIFFAREA 0.708600 ;
    PORT
      LAYER Metal3 ;
        RECT 184.400 403.420 184.800 403.820 ;
    END
  END Tile_X0Y0_FrameData_O[16]
  PIN Tile_X0Y0_FrameData_O[17]
    DIRECTION OUTPUT ;
    USE SIGNAL ;
    ANTENNADIFFAREA 0.708600 ;
    PORT
      LAYER Metal3 ;
        RECT 184.400 405.100 184.800 405.500 ;
    END
  END Tile_X0Y0_FrameData_O[17]
  PIN Tile_X0Y0_FrameData_O[18]
    DIRECTION OUTPUT ;
    USE SIGNAL ;
    ANTENNADIFFAREA 0.708600 ;
    PORT
      LAYER Metal3 ;
        RECT 184.400 406.780 184.800 407.180 ;
    END
  END Tile_X0Y0_FrameData_O[18]
  PIN Tile_X0Y0_FrameData_O[19]
    DIRECTION OUTPUT ;
    USE SIGNAL ;
    ANTENNADIFFAREA 0.708600 ;
    PORT
      LAYER Metal3 ;
        RECT 184.400 408.460 184.800 408.860 ;
    END
  END Tile_X0Y0_FrameData_O[19]
  PIN Tile_X0Y0_FrameData_O[1]
    DIRECTION OUTPUT ;
    USE SIGNAL ;
    ANTENNADIFFAREA 0.708600 ;
    PORT
      LAYER Metal3 ;
        RECT 184.400 378.220 184.800 378.620 ;
    END
  END Tile_X0Y0_FrameData_O[1]
  PIN Tile_X0Y0_FrameData_O[20]
    DIRECTION OUTPUT ;
    USE SIGNAL ;
    ANTENNADIFFAREA 0.708600 ;
    PORT
      LAYER Metal3 ;
        RECT 184.400 410.140 184.800 410.540 ;
    END
  END Tile_X0Y0_FrameData_O[20]
  PIN Tile_X0Y0_FrameData_O[21]
    DIRECTION OUTPUT ;
    USE SIGNAL ;
    ANTENNADIFFAREA 0.708600 ;
    PORT
      LAYER Metal3 ;
        RECT 184.400 411.820 184.800 412.220 ;
    END
  END Tile_X0Y0_FrameData_O[21]
  PIN Tile_X0Y0_FrameData_O[22]
    DIRECTION OUTPUT ;
    USE SIGNAL ;
    ANTENNADIFFAREA 0.708600 ;
    PORT
      LAYER Metal3 ;
        RECT 184.400 413.500 184.800 413.900 ;
    END
  END Tile_X0Y0_FrameData_O[22]
  PIN Tile_X0Y0_FrameData_O[23]
    DIRECTION OUTPUT ;
    USE SIGNAL ;
    ANTENNADIFFAREA 0.708600 ;
    PORT
      LAYER Metal3 ;
        RECT 184.400 415.180 184.800 415.580 ;
    END
  END Tile_X0Y0_FrameData_O[23]
  PIN Tile_X0Y0_FrameData_O[24]
    DIRECTION OUTPUT ;
    USE SIGNAL ;
    ANTENNADIFFAREA 0.708600 ;
    PORT
      LAYER Metal3 ;
        RECT 184.400 416.860 184.800 417.260 ;
    END
  END Tile_X0Y0_FrameData_O[24]
  PIN Tile_X0Y0_FrameData_O[25]
    DIRECTION OUTPUT ;
    USE SIGNAL ;
    ANTENNADIFFAREA 0.708600 ;
    PORT
      LAYER Metal3 ;
        RECT 184.400 418.540 184.800 418.940 ;
    END
  END Tile_X0Y0_FrameData_O[25]
  PIN Tile_X0Y0_FrameData_O[26]
    DIRECTION OUTPUT ;
    USE SIGNAL ;
    ANTENNADIFFAREA 0.708600 ;
    PORT
      LAYER Metal3 ;
        RECT 184.400 420.220 184.800 420.620 ;
    END
  END Tile_X0Y0_FrameData_O[26]
  PIN Tile_X0Y0_FrameData_O[27]
    DIRECTION OUTPUT ;
    USE SIGNAL ;
    ANTENNADIFFAREA 0.708600 ;
    PORT
      LAYER Metal3 ;
        RECT 184.400 421.900 184.800 422.300 ;
    END
  END Tile_X0Y0_FrameData_O[27]
  PIN Tile_X0Y0_FrameData_O[28]
    DIRECTION OUTPUT ;
    USE SIGNAL ;
    ANTENNADIFFAREA 0.708600 ;
    PORT
      LAYER Metal3 ;
        RECT 184.400 423.580 184.800 423.980 ;
    END
  END Tile_X0Y0_FrameData_O[28]
  PIN Tile_X0Y0_FrameData_O[29]
    DIRECTION OUTPUT ;
    USE SIGNAL ;
    ANTENNADIFFAREA 0.708600 ;
    PORT
      LAYER Metal3 ;
        RECT 184.400 425.260 184.800 425.660 ;
    END
  END Tile_X0Y0_FrameData_O[29]
  PIN Tile_X0Y0_FrameData_O[2]
    DIRECTION OUTPUT ;
    USE SIGNAL ;
    ANTENNADIFFAREA 0.708600 ;
    PORT
      LAYER Metal3 ;
        RECT 184.400 379.900 184.800 380.300 ;
    END
  END Tile_X0Y0_FrameData_O[2]
  PIN Tile_X0Y0_FrameData_O[30]
    DIRECTION OUTPUT ;
    USE SIGNAL ;
    ANTENNADIFFAREA 0.708600 ;
    PORT
      LAYER Metal3 ;
        RECT 184.400 426.940 184.800 427.340 ;
    END
  END Tile_X0Y0_FrameData_O[30]
  PIN Tile_X0Y0_FrameData_O[31]
    DIRECTION OUTPUT ;
    USE SIGNAL ;
    ANTENNADIFFAREA 0.708600 ;
    PORT
      LAYER Metal3 ;
        RECT 184.400 428.620 184.800 429.020 ;
    END
  END Tile_X0Y0_FrameData_O[31]
  PIN Tile_X0Y0_FrameData_O[3]
    DIRECTION OUTPUT ;
    USE SIGNAL ;
    ANTENNADIFFAREA 0.708600 ;
    PORT
      LAYER Metal3 ;
        RECT 184.400 381.580 184.800 381.980 ;
    END
  END Tile_X0Y0_FrameData_O[3]
  PIN Tile_X0Y0_FrameData_O[4]
    DIRECTION OUTPUT ;
    USE SIGNAL ;
    ANTENNADIFFAREA 0.708600 ;
    PORT
      LAYER Metal3 ;
        RECT 184.400 383.260 184.800 383.660 ;
    END
  END Tile_X0Y0_FrameData_O[4]
  PIN Tile_X0Y0_FrameData_O[5]
    DIRECTION OUTPUT ;
    USE SIGNAL ;
    ANTENNADIFFAREA 0.708600 ;
    PORT
      LAYER Metal3 ;
        RECT 184.400 384.940 184.800 385.340 ;
    END
  END Tile_X0Y0_FrameData_O[5]
  PIN Tile_X0Y0_FrameData_O[6]
    DIRECTION OUTPUT ;
    USE SIGNAL ;
    ANTENNADIFFAREA 0.708600 ;
    PORT
      LAYER Metal3 ;
        RECT 184.400 386.620 184.800 387.020 ;
    END
  END Tile_X0Y0_FrameData_O[6]
  PIN Tile_X0Y0_FrameData_O[7]
    DIRECTION OUTPUT ;
    USE SIGNAL ;
    ANTENNADIFFAREA 0.708600 ;
    PORT
      LAYER Metal3 ;
        RECT 184.400 388.300 184.800 388.700 ;
    END
  END Tile_X0Y0_FrameData_O[7]
  PIN Tile_X0Y0_FrameData_O[8]
    DIRECTION OUTPUT ;
    USE SIGNAL ;
    ANTENNADIFFAREA 0.708600 ;
    PORT
      LAYER Metal3 ;
        RECT 184.400 389.980 184.800 390.380 ;
    END
  END Tile_X0Y0_FrameData_O[8]
  PIN Tile_X0Y0_FrameData_O[9]
    DIRECTION OUTPUT ;
    USE SIGNAL ;
    ANTENNADIFFAREA 0.708600 ;
    PORT
      LAYER Metal3 ;
        RECT 184.400 391.660 184.800 392.060 ;
    END
  END Tile_X0Y0_FrameData_O[9]
  PIN Tile_X0Y0_FrameStrobe_O[0]
    DIRECTION OUTPUT ;
    USE SIGNAL ;
    ANTENNADIFFAREA 0.708600 ;
    PORT
      LAYER Metal2 ;
        RECT 132.760 429.680 133.160 430.080 ;
    END
  END Tile_X0Y0_FrameStrobe_O[0]
  PIN Tile_X0Y0_FrameStrobe_O[10]
    DIRECTION OUTPUT ;
    USE SIGNAL ;
    ANTENNADIFFAREA 0.708600 ;
    PORT
      LAYER Metal2 ;
        RECT 142.360 429.680 142.760 430.080 ;
    END
  END Tile_X0Y0_FrameStrobe_O[10]
  PIN Tile_X0Y0_FrameStrobe_O[11]
    DIRECTION OUTPUT ;
    USE SIGNAL ;
    ANTENNADIFFAREA 0.708600 ;
    PORT
      LAYER Metal2 ;
        RECT 143.320 429.680 143.720 430.080 ;
    END
  END Tile_X0Y0_FrameStrobe_O[11]
  PIN Tile_X0Y0_FrameStrobe_O[12]
    DIRECTION OUTPUT ;
    USE SIGNAL ;
    ANTENNADIFFAREA 0.708600 ;
    PORT
      LAYER Metal2 ;
        RECT 144.280 429.680 144.680 430.080 ;
    END
  END Tile_X0Y0_FrameStrobe_O[12]
  PIN Tile_X0Y0_FrameStrobe_O[13]
    DIRECTION OUTPUT ;
    USE SIGNAL ;
    ANTENNADIFFAREA 0.708600 ;
    PORT
      LAYER Metal2 ;
        RECT 145.240 429.680 145.640 430.080 ;
    END
  END Tile_X0Y0_FrameStrobe_O[13]
  PIN Tile_X0Y0_FrameStrobe_O[14]
    DIRECTION OUTPUT ;
    USE SIGNAL ;
    ANTENNADIFFAREA 0.708600 ;
    PORT
      LAYER Metal2 ;
        RECT 146.200 429.680 146.600 430.080 ;
    END
  END Tile_X0Y0_FrameStrobe_O[14]
  PIN Tile_X0Y0_FrameStrobe_O[15]
    DIRECTION OUTPUT ;
    USE SIGNAL ;
    ANTENNADIFFAREA 0.708600 ;
    PORT
      LAYER Metal2 ;
        RECT 147.160 429.680 147.560 430.080 ;
    END
  END Tile_X0Y0_FrameStrobe_O[15]
  PIN Tile_X0Y0_FrameStrobe_O[16]
    DIRECTION OUTPUT ;
    USE SIGNAL ;
    ANTENNADIFFAREA 0.708600 ;
    PORT
      LAYER Metal2 ;
        RECT 148.120 429.680 148.520 430.080 ;
    END
  END Tile_X0Y0_FrameStrobe_O[16]
  PIN Tile_X0Y0_FrameStrobe_O[17]
    DIRECTION OUTPUT ;
    USE SIGNAL ;
    ANTENNADIFFAREA 0.708600 ;
    PORT
      LAYER Metal2 ;
        RECT 149.080 429.680 149.480 430.080 ;
    END
  END Tile_X0Y0_FrameStrobe_O[17]
  PIN Tile_X0Y0_FrameStrobe_O[18]
    DIRECTION OUTPUT ;
    USE SIGNAL ;
    ANTENNADIFFAREA 0.708600 ;
    PORT
      LAYER Metal2 ;
        RECT 150.040 429.680 150.440 430.080 ;
    END
  END Tile_X0Y0_FrameStrobe_O[18]
  PIN Tile_X0Y0_FrameStrobe_O[19]
    DIRECTION OUTPUT ;
    USE SIGNAL ;
    ANTENNADIFFAREA 0.708600 ;
    PORT
      LAYER Metal2 ;
        RECT 151.000 429.680 151.400 430.080 ;
    END
  END Tile_X0Y0_FrameStrobe_O[19]
  PIN Tile_X0Y0_FrameStrobe_O[1]
    DIRECTION OUTPUT ;
    USE SIGNAL ;
    ANTENNADIFFAREA 0.708600 ;
    PORT
      LAYER Metal2 ;
        RECT 133.720 429.680 134.120 430.080 ;
    END
  END Tile_X0Y0_FrameStrobe_O[1]
  PIN Tile_X0Y0_FrameStrobe_O[2]
    DIRECTION OUTPUT ;
    USE SIGNAL ;
    ANTENNADIFFAREA 0.708600 ;
    PORT
      LAYER Metal2 ;
        RECT 134.680 429.680 135.080 430.080 ;
    END
  END Tile_X0Y0_FrameStrobe_O[2]
  PIN Tile_X0Y0_FrameStrobe_O[3]
    DIRECTION OUTPUT ;
    USE SIGNAL ;
    ANTENNADIFFAREA 0.708600 ;
    PORT
      LAYER Metal2 ;
        RECT 135.640 429.680 136.040 430.080 ;
    END
  END Tile_X0Y0_FrameStrobe_O[3]
  PIN Tile_X0Y0_FrameStrobe_O[4]
    DIRECTION OUTPUT ;
    USE SIGNAL ;
    ANTENNADIFFAREA 0.708600 ;
    PORT
      LAYER Metal2 ;
        RECT 136.600 429.680 137.000 430.080 ;
    END
  END Tile_X0Y0_FrameStrobe_O[4]
  PIN Tile_X0Y0_FrameStrobe_O[5]
    DIRECTION OUTPUT ;
    USE SIGNAL ;
    ANTENNADIFFAREA 0.708600 ;
    PORT
      LAYER Metal2 ;
        RECT 137.560 429.680 137.960 430.080 ;
    END
  END Tile_X0Y0_FrameStrobe_O[5]
  PIN Tile_X0Y0_FrameStrobe_O[6]
    DIRECTION OUTPUT ;
    USE SIGNAL ;
    ANTENNADIFFAREA 0.708600 ;
    PORT
      LAYER Metal2 ;
        RECT 138.520 429.680 138.920 430.080 ;
    END
  END Tile_X0Y0_FrameStrobe_O[6]
  PIN Tile_X0Y0_FrameStrobe_O[7]
    DIRECTION OUTPUT ;
    USE SIGNAL ;
    ANTENNADIFFAREA 0.708600 ;
    PORT
      LAYER Metal2 ;
        RECT 139.480 429.680 139.880 430.080 ;
    END
  END Tile_X0Y0_FrameStrobe_O[7]
  PIN Tile_X0Y0_FrameStrobe_O[8]
    DIRECTION OUTPUT ;
    USE SIGNAL ;
    ANTENNADIFFAREA 0.708600 ;
    PORT
      LAYER Metal2 ;
        RECT 140.440 429.680 140.840 430.080 ;
    END
  END Tile_X0Y0_FrameStrobe_O[8]
  PIN Tile_X0Y0_FrameStrobe_O[9]
    DIRECTION OUTPUT ;
    USE SIGNAL ;
    ANTENNADIFFAREA 0.708600 ;
    PORT
      LAYER Metal2 ;
        RECT 141.400 429.680 141.800 430.080 ;
    END
  END Tile_X0Y0_FrameStrobe_O[9]
  PIN Tile_X0Y0_N1BEG[0]
    DIRECTION OUTPUT ;
    USE SIGNAL ;
    ANTENNADIFFAREA 0.708600 ;
    PORT
      LAYER Metal2 ;
        RECT 31.960 429.680 32.360 430.080 ;
    END
  END Tile_X0Y0_N1BEG[0]
  PIN Tile_X0Y0_N1BEG[1]
    DIRECTION OUTPUT ;
    USE SIGNAL ;
    ANTENNADIFFAREA 0.708600 ;
    PORT
      LAYER Metal2 ;
        RECT 32.920 429.680 33.320 430.080 ;
    END
  END Tile_X0Y0_N1BEG[1]
  PIN Tile_X0Y0_N1BEG[2]
    DIRECTION OUTPUT ;
    USE SIGNAL ;
    ANTENNADIFFAREA 0.708600 ;
    PORT
      LAYER Metal2 ;
        RECT 33.880 429.680 34.280 430.080 ;
    END
  END Tile_X0Y0_N1BEG[2]
  PIN Tile_X0Y0_N1BEG[3]
    DIRECTION OUTPUT ;
    USE SIGNAL ;
    ANTENNADIFFAREA 0.708600 ;
    PORT
      LAYER Metal2 ;
        RECT 34.840 429.680 35.240 430.080 ;
    END
  END Tile_X0Y0_N1BEG[3]
  PIN Tile_X0Y0_N2BEG[0]
    DIRECTION OUTPUT ;
    USE SIGNAL ;
    ANTENNADIFFAREA 0.708600 ;
    PORT
      LAYER Metal2 ;
        RECT 35.800 429.680 36.200 430.080 ;
    END
  END Tile_X0Y0_N2BEG[0]
  PIN Tile_X0Y0_N2BEG[1]
    DIRECTION OUTPUT ;
    USE SIGNAL ;
    ANTENNADIFFAREA 0.708600 ;
    PORT
      LAYER Metal2 ;
        RECT 36.760 429.680 37.160 430.080 ;
    END
  END Tile_X0Y0_N2BEG[1]
  PIN Tile_X0Y0_N2BEG[2]
    DIRECTION OUTPUT ;
    USE SIGNAL ;
    ANTENNADIFFAREA 0.708600 ;
    PORT
      LAYER Metal2 ;
        RECT 37.720 429.680 38.120 430.080 ;
    END
  END Tile_X0Y0_N2BEG[2]
  PIN Tile_X0Y0_N2BEG[3]
    DIRECTION OUTPUT ;
    USE SIGNAL ;
    ANTENNADIFFAREA 0.708600 ;
    PORT
      LAYER Metal2 ;
        RECT 38.680 429.680 39.080 430.080 ;
    END
  END Tile_X0Y0_N2BEG[3]
  PIN Tile_X0Y0_N2BEG[4]
    DIRECTION OUTPUT ;
    USE SIGNAL ;
    ANTENNADIFFAREA 0.708600 ;
    PORT
      LAYER Metal2 ;
        RECT 39.640 429.680 40.040 430.080 ;
    END
  END Tile_X0Y0_N2BEG[4]
  PIN Tile_X0Y0_N2BEG[5]
    DIRECTION OUTPUT ;
    USE SIGNAL ;
    ANTENNADIFFAREA 0.708600 ;
    PORT
      LAYER Metal2 ;
        RECT 40.600 429.680 41.000 430.080 ;
    END
  END Tile_X0Y0_N2BEG[5]
  PIN Tile_X0Y0_N2BEG[6]
    DIRECTION OUTPUT ;
    USE SIGNAL ;
    ANTENNADIFFAREA 0.708600 ;
    PORT
      LAYER Metal2 ;
        RECT 41.560 429.680 41.960 430.080 ;
    END
  END Tile_X0Y0_N2BEG[6]
  PIN Tile_X0Y0_N2BEG[7]
    DIRECTION OUTPUT ;
    USE SIGNAL ;
    ANTENNADIFFAREA 0.708600 ;
    PORT
      LAYER Metal2 ;
        RECT 42.520 429.680 42.920 430.080 ;
    END
  END Tile_X0Y0_N2BEG[7]
  PIN Tile_X0Y0_N2BEGb[0]
    DIRECTION OUTPUT ;
    USE SIGNAL ;
    ANTENNADIFFAREA 0.708600 ;
    PORT
      LAYER Metal2 ;
        RECT 43.480 429.680 43.880 430.080 ;
    END
  END Tile_X0Y0_N2BEGb[0]
  PIN Tile_X0Y0_N2BEGb[1]
    DIRECTION OUTPUT ;
    USE SIGNAL ;
    ANTENNADIFFAREA 0.708600 ;
    PORT
      LAYER Metal2 ;
        RECT 44.440 429.680 44.840 430.080 ;
    END
  END Tile_X0Y0_N2BEGb[1]
  PIN Tile_X0Y0_N2BEGb[2]
    DIRECTION OUTPUT ;
    USE SIGNAL ;
    ANTENNADIFFAREA 0.708600 ;
    PORT
      LAYER Metal2 ;
        RECT 45.400 429.680 45.800 430.080 ;
    END
  END Tile_X0Y0_N2BEGb[2]
  PIN Tile_X0Y0_N2BEGb[3]
    DIRECTION OUTPUT ;
    USE SIGNAL ;
    ANTENNADIFFAREA 0.708600 ;
    PORT
      LAYER Metal2 ;
        RECT 46.360 429.680 46.760 430.080 ;
    END
  END Tile_X0Y0_N2BEGb[3]
  PIN Tile_X0Y0_N2BEGb[4]
    DIRECTION OUTPUT ;
    USE SIGNAL ;
    ANTENNADIFFAREA 0.708600 ;
    PORT
      LAYER Metal2 ;
        RECT 47.320 429.680 47.720 430.080 ;
    END
  END Tile_X0Y0_N2BEGb[4]
  PIN Tile_X0Y0_N2BEGb[5]
    DIRECTION OUTPUT ;
    USE SIGNAL ;
    ANTENNADIFFAREA 0.708600 ;
    PORT
      LAYER Metal2 ;
        RECT 48.280 429.680 48.680 430.080 ;
    END
  END Tile_X0Y0_N2BEGb[5]
  PIN Tile_X0Y0_N2BEGb[6]
    DIRECTION OUTPUT ;
    USE SIGNAL ;
    ANTENNADIFFAREA 0.708600 ;
    PORT
      LAYER Metal2 ;
        RECT 49.240 429.680 49.640 430.080 ;
    END
  END Tile_X0Y0_N2BEGb[6]
  PIN Tile_X0Y0_N2BEGb[7]
    DIRECTION OUTPUT ;
    USE SIGNAL ;
    ANTENNADIFFAREA 0.708600 ;
    PORT
      LAYER Metal2 ;
        RECT 50.200 429.680 50.600 430.080 ;
    END
  END Tile_X0Y0_N2BEGb[7]
  PIN Tile_X0Y0_N4BEG[0]
    DIRECTION OUTPUT ;
    USE SIGNAL ;
    ANTENNADIFFAREA 0.708600 ;
    PORT
      LAYER Metal2 ;
        RECT 51.160 429.680 51.560 430.080 ;
    END
  END Tile_X0Y0_N4BEG[0]
  PIN Tile_X0Y0_N4BEG[10]
    DIRECTION OUTPUT ;
    USE SIGNAL ;
    ANTENNADIFFAREA 0.708600 ;
    PORT
      LAYER Metal2 ;
        RECT 60.760 429.680 61.160 430.080 ;
    END
  END Tile_X0Y0_N4BEG[10]
  PIN Tile_X0Y0_N4BEG[11]
    DIRECTION OUTPUT ;
    USE SIGNAL ;
    ANTENNADIFFAREA 0.708600 ;
    PORT
      LAYER Metal2 ;
        RECT 61.720 429.680 62.120 430.080 ;
    END
  END Tile_X0Y0_N4BEG[11]
  PIN Tile_X0Y0_N4BEG[12]
    DIRECTION OUTPUT ;
    USE SIGNAL ;
    ANTENNADIFFAREA 0.708600 ;
    PORT
      LAYER Metal2 ;
        RECT 62.680 429.680 63.080 430.080 ;
    END
  END Tile_X0Y0_N4BEG[12]
  PIN Tile_X0Y0_N4BEG[13]
    DIRECTION OUTPUT ;
    USE SIGNAL ;
    ANTENNADIFFAREA 0.708600 ;
    PORT
      LAYER Metal2 ;
        RECT 63.640 429.680 64.040 430.080 ;
    END
  END Tile_X0Y0_N4BEG[13]
  PIN Tile_X0Y0_N4BEG[14]
    DIRECTION OUTPUT ;
    USE SIGNAL ;
    ANTENNADIFFAREA 0.708600 ;
    PORT
      LAYER Metal2 ;
        RECT 64.600 429.680 65.000 430.080 ;
    END
  END Tile_X0Y0_N4BEG[14]
  PIN Tile_X0Y0_N4BEG[15]
    DIRECTION OUTPUT ;
    USE SIGNAL ;
    ANTENNADIFFAREA 0.708600 ;
    PORT
      LAYER Metal2 ;
        RECT 65.560 429.680 65.960 430.080 ;
    END
  END Tile_X0Y0_N4BEG[15]
  PIN Tile_X0Y0_N4BEG[1]
    DIRECTION OUTPUT ;
    USE SIGNAL ;
    ANTENNADIFFAREA 0.708600 ;
    PORT
      LAYER Metal2 ;
        RECT 52.120 429.680 52.520 430.080 ;
    END
  END Tile_X0Y0_N4BEG[1]
  PIN Tile_X0Y0_N4BEG[2]
    DIRECTION OUTPUT ;
    USE SIGNAL ;
    ANTENNADIFFAREA 0.708600 ;
    PORT
      LAYER Metal2 ;
        RECT 53.080 429.680 53.480 430.080 ;
    END
  END Tile_X0Y0_N4BEG[2]
  PIN Tile_X0Y0_N4BEG[3]
    DIRECTION OUTPUT ;
    USE SIGNAL ;
    ANTENNADIFFAREA 0.708600 ;
    PORT
      LAYER Metal2 ;
        RECT 54.040 429.680 54.440 430.080 ;
    END
  END Tile_X0Y0_N4BEG[3]
  PIN Tile_X0Y0_N4BEG[4]
    DIRECTION OUTPUT ;
    USE SIGNAL ;
    ANTENNADIFFAREA 0.708600 ;
    PORT
      LAYER Metal2 ;
        RECT 55.000 429.680 55.400 430.080 ;
    END
  END Tile_X0Y0_N4BEG[4]
  PIN Tile_X0Y0_N4BEG[5]
    DIRECTION OUTPUT ;
    USE SIGNAL ;
    ANTENNADIFFAREA 0.708600 ;
    PORT
      LAYER Metal2 ;
        RECT 55.960 429.680 56.360 430.080 ;
    END
  END Tile_X0Y0_N4BEG[5]
  PIN Tile_X0Y0_N4BEG[6]
    DIRECTION OUTPUT ;
    USE SIGNAL ;
    ANTENNADIFFAREA 0.708600 ;
    PORT
      LAYER Metal2 ;
        RECT 56.920 429.680 57.320 430.080 ;
    END
  END Tile_X0Y0_N4BEG[6]
  PIN Tile_X0Y0_N4BEG[7]
    DIRECTION OUTPUT ;
    USE SIGNAL ;
    ANTENNADIFFAREA 0.708600 ;
    PORT
      LAYER Metal2 ;
        RECT 57.880 429.680 58.280 430.080 ;
    END
  END Tile_X0Y0_N4BEG[7]
  PIN Tile_X0Y0_N4BEG[8]
    DIRECTION OUTPUT ;
    USE SIGNAL ;
    ANTENNADIFFAREA 0.708600 ;
    PORT
      LAYER Metal2 ;
        RECT 58.840 429.680 59.240 430.080 ;
    END
  END Tile_X0Y0_N4BEG[8]
  PIN Tile_X0Y0_N4BEG[9]
    DIRECTION OUTPUT ;
    USE SIGNAL ;
    ANTENNADIFFAREA 0.708600 ;
    PORT
      LAYER Metal2 ;
        RECT 59.800 429.680 60.200 430.080 ;
    END
  END Tile_X0Y0_N4BEG[9]
  PIN Tile_X0Y0_NN4BEG[0]
    DIRECTION OUTPUT ;
    USE SIGNAL ;
    ANTENNADIFFAREA 0.708600 ;
    PORT
      LAYER Metal2 ;
        RECT 66.520 429.680 66.920 430.080 ;
    END
  END Tile_X0Y0_NN4BEG[0]
  PIN Tile_X0Y0_NN4BEG[10]
    DIRECTION OUTPUT ;
    USE SIGNAL ;
    ANTENNADIFFAREA 0.708600 ;
    PORT
      LAYER Metal2 ;
        RECT 76.120 429.680 76.520 430.080 ;
    END
  END Tile_X0Y0_NN4BEG[10]
  PIN Tile_X0Y0_NN4BEG[11]
    DIRECTION OUTPUT ;
    USE SIGNAL ;
    ANTENNADIFFAREA 0.708600 ;
    PORT
      LAYER Metal2 ;
        RECT 77.080 429.680 77.480 430.080 ;
    END
  END Tile_X0Y0_NN4BEG[11]
  PIN Tile_X0Y0_NN4BEG[12]
    DIRECTION OUTPUT ;
    USE SIGNAL ;
    ANTENNADIFFAREA 0.708600 ;
    PORT
      LAYER Metal2 ;
        RECT 78.040 429.680 78.440 430.080 ;
    END
  END Tile_X0Y0_NN4BEG[12]
  PIN Tile_X0Y0_NN4BEG[13]
    DIRECTION OUTPUT ;
    USE SIGNAL ;
    ANTENNADIFFAREA 0.708600 ;
    PORT
      LAYER Metal2 ;
        RECT 79.000 429.680 79.400 430.080 ;
    END
  END Tile_X0Y0_NN4BEG[13]
  PIN Tile_X0Y0_NN4BEG[14]
    DIRECTION OUTPUT ;
    USE SIGNAL ;
    ANTENNADIFFAREA 0.708600 ;
    PORT
      LAYER Metal2 ;
        RECT 79.960 429.680 80.360 430.080 ;
    END
  END Tile_X0Y0_NN4BEG[14]
  PIN Tile_X0Y0_NN4BEG[15]
    DIRECTION OUTPUT ;
    USE SIGNAL ;
    ANTENNADIFFAREA 0.708600 ;
    PORT
      LAYER Metal2 ;
        RECT 80.920 429.680 81.320 430.080 ;
    END
  END Tile_X0Y0_NN4BEG[15]
  PIN Tile_X0Y0_NN4BEG[1]
    DIRECTION OUTPUT ;
    USE SIGNAL ;
    ANTENNADIFFAREA 0.708600 ;
    PORT
      LAYER Metal2 ;
        RECT 67.480 429.680 67.880 430.080 ;
    END
  END Tile_X0Y0_NN4BEG[1]
  PIN Tile_X0Y0_NN4BEG[2]
    DIRECTION OUTPUT ;
    USE SIGNAL ;
    ANTENNADIFFAREA 0.708600 ;
    PORT
      LAYER Metal2 ;
        RECT 68.440 429.680 68.840 430.080 ;
    END
  END Tile_X0Y0_NN4BEG[2]
  PIN Tile_X0Y0_NN4BEG[3]
    DIRECTION OUTPUT ;
    USE SIGNAL ;
    ANTENNADIFFAREA 0.708600 ;
    PORT
      LAYER Metal2 ;
        RECT 69.400 429.680 69.800 430.080 ;
    END
  END Tile_X0Y0_NN4BEG[3]
  PIN Tile_X0Y0_NN4BEG[4]
    DIRECTION OUTPUT ;
    USE SIGNAL ;
    ANTENNADIFFAREA 0.708600 ;
    PORT
      LAYER Metal2 ;
        RECT 70.360 429.680 70.760 430.080 ;
    END
  END Tile_X0Y0_NN4BEG[4]
  PIN Tile_X0Y0_NN4BEG[5]
    DIRECTION OUTPUT ;
    USE SIGNAL ;
    ANTENNADIFFAREA 0.708600 ;
    PORT
      LAYER Metal2 ;
        RECT 71.320 429.680 71.720 430.080 ;
    END
  END Tile_X0Y0_NN4BEG[5]
  PIN Tile_X0Y0_NN4BEG[6]
    DIRECTION OUTPUT ;
    USE SIGNAL ;
    ANTENNADIFFAREA 0.708600 ;
    PORT
      LAYER Metal2 ;
        RECT 72.280 429.680 72.680 430.080 ;
    END
  END Tile_X0Y0_NN4BEG[6]
  PIN Tile_X0Y0_NN4BEG[7]
    DIRECTION OUTPUT ;
    USE SIGNAL ;
    ANTENNADIFFAREA 0.708600 ;
    PORT
      LAYER Metal2 ;
        RECT 73.240 429.680 73.640 430.080 ;
    END
  END Tile_X0Y0_NN4BEG[7]
  PIN Tile_X0Y0_NN4BEG[8]
    DIRECTION OUTPUT ;
    USE SIGNAL ;
    ANTENNADIFFAREA 0.708600 ;
    PORT
      LAYER Metal2 ;
        RECT 74.200 429.680 74.600 430.080 ;
    END
  END Tile_X0Y0_NN4BEG[8]
  PIN Tile_X0Y0_NN4BEG[9]
    DIRECTION OUTPUT ;
    USE SIGNAL ;
    ANTENNADIFFAREA 0.708600 ;
    PORT
      LAYER Metal2 ;
        RECT 75.160 429.680 75.560 430.080 ;
    END
  END Tile_X0Y0_NN4BEG[9]
  PIN Tile_X0Y0_S1END[0]
    DIRECTION INPUT ;
    USE SIGNAL ;
    ANTENNAGATEAREA 1.107600 ;
    PORT
      LAYER Metal2 ;
        RECT 81.880 429.680 82.280 430.080 ;
    END
  END Tile_X0Y0_S1END[0]
  PIN Tile_X0Y0_S1END[1]
    DIRECTION INPUT ;
    USE SIGNAL ;
    ANTENNAGATEAREA 1.606800 ;
    PORT
      LAYER Metal2 ;
        RECT 82.840 429.680 83.240 430.080 ;
    END
  END Tile_X0Y0_S1END[1]
  PIN Tile_X0Y0_S1END[2]
    DIRECTION INPUT ;
    USE SIGNAL ;
    ANTENNAGATEAREA 1.830400 ;
    PORT
      LAYER Metal2 ;
        RECT 83.800 429.680 84.200 430.080 ;
    END
  END Tile_X0Y0_S1END[2]
  PIN Tile_X0Y0_S1END[3]
    DIRECTION INPUT ;
    USE SIGNAL ;
    ANTENNAGATEAREA 1.648400 ;
    PORT
      LAYER Metal2 ;
        RECT 84.760 429.680 85.160 430.080 ;
    END
  END Tile_X0Y0_S1END[3]
  PIN Tile_X0Y0_S2END[0]
    DIRECTION INPUT ;
    USE SIGNAL ;
    ANTENNAGATEAREA 1.246700 ;
    PORT
      LAYER Metal2 ;
        RECT 93.400 429.680 93.800 430.080 ;
    END
  END Tile_X0Y0_S2END[0]
  PIN Tile_X0Y0_S2END[1]
    DIRECTION INPUT ;
    USE SIGNAL ;
    ANTENNAGATEAREA 1.280000 ;
    PORT
      LAYER Metal2 ;
        RECT 94.360 429.680 94.760 430.080 ;
    END
  END Tile_X0Y0_S2END[1]
  PIN Tile_X0Y0_S2END[2]
    DIRECTION INPUT ;
    USE SIGNAL ;
    ANTENNAGATEAREA 1.373600 ;
    PORT
      LAYER Metal2 ;
        RECT 95.320 429.680 95.720 430.080 ;
    END
  END Tile_X0Y0_S2END[2]
  PIN Tile_X0Y0_S2END[3]
    DIRECTION INPUT ;
    USE SIGNAL ;
    ANTENNAGATEAREA 1.094600 ;
    PORT
      LAYER Metal2 ;
        RECT 96.280 429.680 96.680 430.080 ;
    END
  END Tile_X0Y0_S2END[3]
  PIN Tile_X0Y0_S2END[4]
    DIRECTION INPUT ;
    USE SIGNAL ;
    ANTENNAGATEAREA 1.066000 ;
    PORT
      LAYER Metal2 ;
        RECT 97.240 429.680 97.640 430.080 ;
    END
  END Tile_X0Y0_S2END[4]
  PIN Tile_X0Y0_S2END[5]
    DIRECTION INPUT ;
    USE SIGNAL ;
    ANTENNAGATEAREA 1.189000 ;
    PORT
      LAYER Metal2 ;
        RECT 98.200 429.680 98.600 430.080 ;
    END
  END Tile_X0Y0_S2END[5]
  PIN Tile_X0Y0_S2END[6]
    DIRECTION INPUT ;
    USE SIGNAL ;
    ANTENNAGATEAREA 1.223600 ;
    PORT
      LAYER Metal2 ;
        RECT 99.160 429.680 99.560 430.080 ;
    END
  END Tile_X0Y0_S2END[6]
  PIN Tile_X0Y0_S2END[7]
    DIRECTION INPUT ;
    USE SIGNAL ;
    ANTENNAGATEAREA 1.468000 ;
    PORT
      LAYER Metal2 ;
        RECT 100.120 429.680 100.520 430.080 ;
    END
  END Tile_X0Y0_S2END[7]
  PIN Tile_X0Y0_S2MID[0]
    DIRECTION INPUT ;
    USE SIGNAL ;
    ANTENNAGATEAREA 1.094600 ;
    PORT
      LAYER Metal2 ;
        RECT 85.720 429.680 86.120 430.080 ;
    END
  END Tile_X0Y0_S2MID[0]
  PIN Tile_X0Y0_S2MID[1]
    DIRECTION INPUT ;
    USE SIGNAL ;
    ANTENNAGATEAREA 2.167100 ;
    PORT
      LAYER Metal2 ;
        RECT 86.680 429.680 87.080 430.080 ;
    END
  END Tile_X0Y0_S2MID[1]
  PIN Tile_X0Y0_S2MID[2]
    DIRECTION INPUT ;
    USE SIGNAL ;
    ANTENNAGATEAREA 1.853800 ;
    PORT
      LAYER Metal2 ;
        RECT 87.640 429.680 88.040 430.080 ;
    END
  END Tile_X0Y0_S2MID[2]
  PIN Tile_X0Y0_S2MID[3]
    DIRECTION INPUT ;
    USE SIGNAL ;
    ANTENNAGATEAREA 2.215200 ;
    PORT
      LAYER Metal2 ;
        RECT 88.600 429.680 89.000 430.080 ;
    END
  END Tile_X0Y0_S2MID[3]
  PIN Tile_X0Y0_S2MID[4]
    DIRECTION INPUT ;
    USE SIGNAL ;
    ANTENNAGATEAREA 23.210199 ;
    ANTENNADIFFAREA 72.554398 ;
    PORT
      LAYER Metal2 ;
        RECT 89.560 429.680 89.960 430.080 ;
    END
  END Tile_X0Y0_S2MID[4]
  PIN Tile_X0Y0_S2MID[5]
    DIRECTION INPUT ;
    USE SIGNAL ;
    ANTENNAGATEAREA 1.718400 ;
    PORT
      LAYER Metal2 ;
        RECT 90.520 429.680 90.920 430.080 ;
    END
  END Tile_X0Y0_S2MID[5]
  PIN Tile_X0Y0_S2MID[6]
    DIRECTION INPUT ;
    USE SIGNAL ;
    ANTENNAGATEAREA 1.586800 ;
    PORT
      LAYER Metal2 ;
        RECT 91.480 429.680 91.880 430.080 ;
    END
  END Tile_X0Y0_S2MID[6]
  PIN Tile_X0Y0_S2MID[7]
    DIRECTION INPUT ;
    USE SIGNAL ;
    ANTENNAGATEAREA 2.358000 ;
    PORT
      LAYER Metal2 ;
        RECT 92.440 429.680 92.840 430.080 ;
    END
  END Tile_X0Y0_S2MID[7]
  PIN Tile_X0Y0_S4END[0]
    DIRECTION INPUT ;
    USE SIGNAL ;
    ANTENNAGATEAREA 4.149600 ;
    ANTENNADIFFAREA 10.077000 ;
    PORT
      LAYER Metal2 ;
        RECT 101.080 429.680 101.480 430.080 ;
    END
  END Tile_X0Y0_S4END[0]
  PIN Tile_X0Y0_S4END[10]
    DIRECTION INPUT ;
    USE SIGNAL ;
    ANTENNAGATEAREA 0.180700 ;
    PORT
      LAYER Metal2 ;
        RECT 110.680 429.680 111.080 430.080 ;
    END
  END Tile_X0Y0_S4END[10]
  PIN Tile_X0Y0_S4END[11]
    DIRECTION INPUT ;
    USE SIGNAL ;
    ANTENNAGATEAREA 0.180700 ;
    PORT
      LAYER Metal2 ;
        RECT 111.640 429.680 112.040 430.080 ;
    END
  END Tile_X0Y0_S4END[11]
  PIN Tile_X0Y0_S4END[12]
    DIRECTION INPUT ;
    USE SIGNAL ;
    ANTENNAGATEAREA 0.180700 ;
    PORT
      LAYER Metal2 ;
        RECT 112.600 429.680 113.000 430.080 ;
    END
  END Tile_X0Y0_S4END[12]
  PIN Tile_X0Y0_S4END[13]
    DIRECTION INPUT ;
    USE SIGNAL ;
    ANTENNAGATEAREA 0.180700 ;
    PORT
      LAYER Metal2 ;
        RECT 113.560 429.680 113.960 430.080 ;
    END
  END Tile_X0Y0_S4END[13]
  PIN Tile_X0Y0_S4END[14]
    DIRECTION INPUT ;
    USE SIGNAL ;
    ANTENNAGATEAREA 0.180700 ;
    PORT
      LAYER Metal2 ;
        RECT 114.520 429.680 114.920 430.080 ;
    END
  END Tile_X0Y0_S4END[14]
  PIN Tile_X0Y0_S4END[15]
    DIRECTION INPUT ;
    USE SIGNAL ;
    ANTENNAGATEAREA 0.180700 ;
    PORT
      LAYER Metal2 ;
        RECT 115.480 429.680 115.880 430.080 ;
    END
  END Tile_X0Y0_S4END[15]
  PIN Tile_X0Y0_S4END[1]
    DIRECTION INPUT ;
    USE SIGNAL ;
    ANTENNAGATEAREA 0.696800 ;
    PORT
      LAYER Metal2 ;
        RECT 102.040 429.680 102.440 430.080 ;
    END
  END Tile_X0Y0_S4END[1]
  PIN Tile_X0Y0_S4END[2]
    DIRECTION INPUT ;
    USE SIGNAL ;
    ANTENNAGATEAREA 0.960200 ;
    PORT
      LAYER Metal2 ;
        RECT 103.000 429.680 103.400 430.080 ;
    END
  END Tile_X0Y0_S4END[2]
  PIN Tile_X0Y0_S4END[3]
    DIRECTION INPUT ;
    USE SIGNAL ;
    ANTENNAGATEAREA 1.107600 ;
    PORT
      LAYER Metal2 ;
        RECT 103.960 429.680 104.360 430.080 ;
    END
  END Tile_X0Y0_S4END[3]
  PIN Tile_X0Y0_S4END[4]
    DIRECTION INPUT ;
    USE SIGNAL ;
    ANTENNAGATEAREA 0.668200 ;
    PORT
      LAYER Metal2 ;
        RECT 104.920 429.680 105.320 430.080 ;
    END
  END Tile_X0Y0_S4END[4]
  PIN Tile_X0Y0_S4END[5]
    DIRECTION INPUT ;
    USE SIGNAL ;
    ANTENNAGATEAREA 1.107600 ;
    PORT
      LAYER Metal2 ;
        RECT 105.880 429.680 106.280 430.080 ;
    END
  END Tile_X0Y0_S4END[5]
  PIN Tile_X0Y0_S4END[6]
    DIRECTION INPUT ;
    USE SIGNAL ;
    ANTENNAGATEAREA 16.239599 ;
    ANTENNADIFFAREA 50.384998 ;
    PORT
      LAYER Metal2 ;
        RECT 106.840 429.680 107.240 430.080 ;
    END
  END Tile_X0Y0_S4END[6]
  PIN Tile_X0Y0_S4END[7]
    DIRECTION INPUT ;
    USE SIGNAL ;
    ANTENNAGATEAREA 1.144800 ;
    PORT
      LAYER Metal2 ;
        RECT 107.800 429.680 108.200 430.080 ;
    END
  END Tile_X0Y0_S4END[7]
  PIN Tile_X0Y0_S4END[8]
    DIRECTION INPUT ;
    USE SIGNAL ;
    ANTENNAGATEAREA 0.180700 ;
    PORT
      LAYER Metal2 ;
        RECT 108.760 429.680 109.160 430.080 ;
    END
  END Tile_X0Y0_S4END[8]
  PIN Tile_X0Y0_S4END[9]
    DIRECTION INPUT ;
    USE SIGNAL ;
    ANTENNAGATEAREA 0.180700 ;
    PORT
      LAYER Metal2 ;
        RECT 109.720 429.680 110.120 430.080 ;
    END
  END Tile_X0Y0_S4END[9]
  PIN Tile_X0Y0_SS4END[0]
    DIRECTION INPUT ;
    USE SIGNAL ;
    ANTENNAGATEAREA 0.668200 ;
    PORT
      LAYER Metal2 ;
        RECT 116.440 429.680 116.840 430.080 ;
    END
  END Tile_X0Y0_SS4END[0]
  PIN Tile_X0Y0_SS4END[10]
    DIRECTION INPUT ;
    USE SIGNAL ;
    ANTENNAGATEAREA 0.180700 ;
    PORT
      LAYER Metal2 ;
        RECT 126.040 429.680 126.440 430.080 ;
    END
  END Tile_X0Y0_SS4END[10]
  PIN Tile_X0Y0_SS4END[11]
    DIRECTION INPUT ;
    USE SIGNAL ;
    ANTENNAGATEAREA 0.180700 ;
    PORT
      LAYER Metal2 ;
        RECT 127.000 429.680 127.400 430.080 ;
    END
  END Tile_X0Y0_SS4END[11]
  PIN Tile_X0Y0_SS4END[12]
    DIRECTION INPUT ;
    USE SIGNAL ;
    ANTENNAGATEAREA 0.180700 ;
    PORT
      LAYER Metal2 ;
        RECT 127.960 429.680 128.360 430.080 ;
    END
  END Tile_X0Y0_SS4END[12]
  PIN Tile_X0Y0_SS4END[13]
    DIRECTION INPUT ;
    USE SIGNAL ;
    ANTENNAGATEAREA 0.180700 ;
    PORT
      LAYER Metal2 ;
        RECT 128.920 429.680 129.320 430.080 ;
    END
  END Tile_X0Y0_SS4END[13]
  PIN Tile_X0Y0_SS4END[14]
    DIRECTION INPUT ;
    USE SIGNAL ;
    ANTENNAGATEAREA 0.180700 ;
    PORT
      LAYER Metal2 ;
        RECT 129.880 429.680 130.280 430.080 ;
    END
  END Tile_X0Y0_SS4END[14]
  PIN Tile_X0Y0_SS4END[15]
    DIRECTION INPUT ;
    USE SIGNAL ;
    ANTENNAGATEAREA 0.180700 ;
    PORT
      LAYER Metal2 ;
        RECT 130.840 429.680 131.240 430.080 ;
    END
  END Tile_X0Y0_SS4END[15]
  PIN Tile_X0Y0_SS4END[1]
    DIRECTION INPUT ;
    USE SIGNAL ;
    ANTENNAGATEAREA 0.668200 ;
    PORT
      LAYER Metal2 ;
        RECT 117.400 429.680 117.800 430.080 ;
    END
  END Tile_X0Y0_SS4END[1]
  PIN Tile_X0Y0_SS4END[2]
    DIRECTION INPUT ;
    USE SIGNAL ;
    ANTENNAGATEAREA 0.681200 ;
    PORT
      LAYER Metal2 ;
        RECT 118.360 429.680 118.760 430.080 ;
    END
  END Tile_X0Y0_SS4END[2]
  PIN Tile_X0Y0_SS4END[3]
    DIRECTION INPUT ;
    USE SIGNAL ;
    ANTENNAGATEAREA 0.455000 ;
    PORT
      LAYER Metal2 ;
        RECT 119.320 429.680 119.720 430.080 ;
    END
  END Tile_X0Y0_SS4END[3]
  PIN Tile_X0Y0_SS4END[4]
    DIRECTION INPUT ;
    USE SIGNAL ;
    ANTENNAGATEAREA 0.734000 ;
    PORT
      LAYER Metal2 ;
        RECT 120.280 429.680 120.680 430.080 ;
    END
  END Tile_X0Y0_SS4END[4]
  PIN Tile_X0Y0_SS4END[5]
    DIRECTION INPUT ;
    USE SIGNAL ;
    ANTENNAGATEAREA 0.652600 ;
    PORT
      LAYER Metal2 ;
        RECT 121.240 429.680 121.640 430.080 ;
    END
  END Tile_X0Y0_SS4END[5]
  PIN Tile_X0Y0_SS4END[6]
    DIRECTION INPUT ;
    USE SIGNAL ;
    ANTENNAGATEAREA 0.696800 ;
    PORT
      LAYER Metal2 ;
        RECT 122.200 429.680 122.600 430.080 ;
    END
  END Tile_X0Y0_SS4END[6]
  PIN Tile_X0Y0_SS4END[7]
    DIRECTION INPUT ;
    USE SIGNAL ;
    ANTENNAGATEAREA 0.455000 ;
    PORT
      LAYER Metal2 ;
        RECT 123.160 429.680 123.560 430.080 ;
    END
  END Tile_X0Y0_SS4END[7]
  PIN Tile_X0Y0_SS4END[8]
    DIRECTION INPUT ;
    USE SIGNAL ;
    ANTENNAGATEAREA 0.180700 ;
    PORT
      LAYER Metal2 ;
        RECT 124.120 429.680 124.520 430.080 ;
    END
  END Tile_X0Y0_SS4END[8]
  PIN Tile_X0Y0_SS4END[9]
    DIRECTION INPUT ;
    USE SIGNAL ;
    ANTENNAGATEAREA 0.180700 ;
    PORT
      LAYER Metal2 ;
        RECT 125.080 429.680 125.480 430.080 ;
    END
  END Tile_X0Y0_SS4END[9]
  PIN Tile_X0Y0_UserCLKo
    DIRECTION OUTPUT ;
    USE SIGNAL ;
    ANTENNADIFFAREA 0.708600 ;
    PORT
      LAYER Metal2 ;
        RECT 131.800 429.680 132.200 430.080 ;
    END
  END Tile_X0Y0_UserCLKo
  PIN Tile_X0Y0_W1BEG[0]
    DIRECTION OUTPUT ;
    USE SIGNAL ;
    ANTENNADIFFAREA 0.708600 ;
    PORT
      LAYER Metal3 ;
        RECT 0.000 215.260 0.400 215.660 ;
    END
  END Tile_X0Y0_W1BEG[0]
  PIN Tile_X0Y0_W1BEG[1]
    DIRECTION OUTPUT ;
    USE SIGNAL ;
    ANTENNADIFFAREA 0.708600 ;
    PORT
      LAYER Metal3 ;
        RECT 0.000 216.940 0.400 217.340 ;
    END
  END Tile_X0Y0_W1BEG[1]
  PIN Tile_X0Y0_W1BEG[2]
    DIRECTION OUTPUT ;
    USE SIGNAL ;
    ANTENNADIFFAREA 0.708600 ;
    PORT
      LAYER Metal3 ;
        RECT 0.000 218.620 0.400 219.020 ;
    END
  END Tile_X0Y0_W1BEG[2]
  PIN Tile_X0Y0_W1BEG[3]
    DIRECTION OUTPUT ;
    USE SIGNAL ;
    ANTENNADIFFAREA 0.708600 ;
    PORT
      LAYER Metal3 ;
        RECT 0.000 220.300 0.400 220.700 ;
    END
  END Tile_X0Y0_W1BEG[3]
  PIN Tile_X0Y0_W1END[0]
    DIRECTION INPUT ;
    USE SIGNAL ;
    ANTENNAGATEAREA 1.904800 ;
    PORT
      LAYER Metal3 ;
        RECT 184.400 215.260 184.800 215.660 ;
    END
  END Tile_X0Y0_W1END[0]
  PIN Tile_X0Y0_W1END[1]
    DIRECTION INPUT ;
    USE SIGNAL ;
    ANTENNAGATEAREA 2.149500 ;
    PORT
      LAYER Metal3 ;
        RECT 184.400 216.940 184.800 217.340 ;
    END
  END Tile_X0Y0_W1END[1]
  PIN Tile_X0Y0_W1END[2]
    DIRECTION INPUT ;
    USE SIGNAL ;
    ANTENNAGATEAREA 2.228200 ;
    PORT
      LAYER Metal3 ;
        RECT 184.400 218.620 184.800 219.020 ;
    END
  END Tile_X0Y0_W1END[2]
  PIN Tile_X0Y0_W1END[3]
    DIRECTION INPUT ;
    USE SIGNAL ;
    ANTENNAGATEAREA 2.176200 ;
    PORT
      LAYER Metal3 ;
        RECT 184.400 220.300 184.800 220.700 ;
    END
  END Tile_X0Y0_W1END[3]
  PIN Tile_X0Y0_W2BEG[0]
    DIRECTION OUTPUT ;
    USE SIGNAL ;
    ANTENNADIFFAREA 0.708600 ;
    PORT
      LAYER Metal3 ;
        RECT 0.000 221.980 0.400 222.380 ;
    END
  END Tile_X0Y0_W2BEG[0]
  PIN Tile_X0Y0_W2BEG[1]
    DIRECTION OUTPUT ;
    USE SIGNAL ;
    ANTENNADIFFAREA 0.708600 ;
    PORT
      LAYER Metal3 ;
        RECT 0.000 223.660 0.400 224.060 ;
    END
  END Tile_X0Y0_W2BEG[1]
  PIN Tile_X0Y0_W2BEG[2]
    DIRECTION OUTPUT ;
    USE SIGNAL ;
    ANTENNADIFFAREA 0.708600 ;
    PORT
      LAYER Metal3 ;
        RECT 0.000 225.340 0.400 225.740 ;
    END
  END Tile_X0Y0_W2BEG[2]
  PIN Tile_X0Y0_W2BEG[3]
    DIRECTION OUTPUT ;
    USE SIGNAL ;
    ANTENNADIFFAREA 0.708600 ;
    PORT
      LAYER Metal3 ;
        RECT 0.000 227.020 0.400 227.420 ;
    END
  END Tile_X0Y0_W2BEG[3]
  PIN Tile_X0Y0_W2BEG[4]
    DIRECTION OUTPUT ;
    USE SIGNAL ;
    ANTENNADIFFAREA 0.708600 ;
    PORT
      LAYER Metal3 ;
        RECT 0.000 228.700 0.400 229.100 ;
    END
  END Tile_X0Y0_W2BEG[4]
  PIN Tile_X0Y0_W2BEG[5]
    DIRECTION OUTPUT ;
    USE SIGNAL ;
    ANTENNADIFFAREA 0.708600 ;
    PORT
      LAYER Metal3 ;
        RECT 0.000 230.380 0.400 230.780 ;
    END
  END Tile_X0Y0_W2BEG[5]
  PIN Tile_X0Y0_W2BEG[6]
    DIRECTION OUTPUT ;
    USE SIGNAL ;
    ANTENNADIFFAREA 0.708600 ;
    PORT
      LAYER Metal3 ;
        RECT 0.000 232.060 0.400 232.460 ;
    END
  END Tile_X0Y0_W2BEG[6]
  PIN Tile_X0Y0_W2BEG[7]
    DIRECTION OUTPUT ;
    USE SIGNAL ;
    ANTENNADIFFAREA 0.708600 ;
    PORT
      LAYER Metal3 ;
        RECT 0.000 233.740 0.400 234.140 ;
    END
  END Tile_X0Y0_W2BEG[7]
  PIN Tile_X0Y0_W2BEGb[0]
    DIRECTION OUTPUT ;
    USE SIGNAL ;
    ANTENNADIFFAREA 0.708600 ;
    PORT
      LAYER Metal3 ;
        RECT 0.000 235.420 0.400 235.820 ;
    END
  END Tile_X0Y0_W2BEGb[0]
  PIN Tile_X0Y0_W2BEGb[1]
    DIRECTION OUTPUT ;
    USE SIGNAL ;
    ANTENNADIFFAREA 0.708600 ;
    PORT
      LAYER Metal3 ;
        RECT 0.000 237.100 0.400 237.500 ;
    END
  END Tile_X0Y0_W2BEGb[1]
  PIN Tile_X0Y0_W2BEGb[2]
    DIRECTION OUTPUT ;
    USE SIGNAL ;
    ANTENNADIFFAREA 0.708600 ;
    PORT
      LAYER Metal3 ;
        RECT 0.000 238.780 0.400 239.180 ;
    END
  END Tile_X0Y0_W2BEGb[2]
  PIN Tile_X0Y0_W2BEGb[3]
    DIRECTION OUTPUT ;
    USE SIGNAL ;
    ANTENNADIFFAREA 0.708600 ;
    PORT
      LAYER Metal3 ;
        RECT 0.000 240.460 0.400 240.860 ;
    END
  END Tile_X0Y0_W2BEGb[3]
  PIN Tile_X0Y0_W2BEGb[4]
    DIRECTION OUTPUT ;
    USE SIGNAL ;
    ANTENNADIFFAREA 0.708600 ;
    PORT
      LAYER Metal3 ;
        RECT 0.000 242.140 0.400 242.540 ;
    END
  END Tile_X0Y0_W2BEGb[4]
  PIN Tile_X0Y0_W2BEGb[5]
    DIRECTION OUTPUT ;
    USE SIGNAL ;
    ANTENNADIFFAREA 0.708600 ;
    PORT
      LAYER Metal3 ;
        RECT 0.000 243.820 0.400 244.220 ;
    END
  END Tile_X0Y0_W2BEGb[5]
  PIN Tile_X0Y0_W2BEGb[6]
    DIRECTION OUTPUT ;
    USE SIGNAL ;
    ANTENNADIFFAREA 0.708600 ;
    PORT
      LAYER Metal3 ;
        RECT 0.000 245.500 0.400 245.900 ;
    END
  END Tile_X0Y0_W2BEGb[6]
  PIN Tile_X0Y0_W2BEGb[7]
    DIRECTION OUTPUT ;
    USE SIGNAL ;
    ANTENNADIFFAREA 0.708600 ;
    PORT
      LAYER Metal3 ;
        RECT 0.000 247.180 0.400 247.580 ;
    END
  END Tile_X0Y0_W2BEGb[7]
  PIN Tile_X0Y0_W2END[0]
    DIRECTION INPUT ;
    USE SIGNAL ;
    ANTENNAGATEAREA 0.607100 ;
    PORT
      LAYER Metal3 ;
        RECT 184.400 235.420 184.800 235.820 ;
    END
  END Tile_X0Y0_W2END[0]
  PIN Tile_X0Y0_W2END[1]
    DIRECTION INPUT ;
    USE SIGNAL ;
    ANTENNAGATEAREA 1.489600 ;
    PORT
      LAYER Metal3 ;
        RECT 184.400 237.100 184.800 237.500 ;
    END
  END Tile_X0Y0_W2END[1]
  PIN Tile_X0Y0_W2END[2]
    DIRECTION INPUT ;
    USE SIGNAL ;
    ANTENNAGATEAREA 1.331200 ;
    PORT
      LAYER Metal3 ;
        RECT 184.400 238.780 184.800 239.180 ;
    END
  END Tile_X0Y0_W2END[2]
  PIN Tile_X0Y0_W2END[3]
    DIRECTION INPUT ;
    USE SIGNAL ;
    ANTENNAGATEAREA 1.604500 ;
    PORT
      LAYER Metal3 ;
        RECT 184.400 240.460 184.800 240.860 ;
    END
  END Tile_X0Y0_W2END[3]
  PIN Tile_X0Y0_W2END[4]
    DIRECTION INPUT ;
    USE SIGNAL ;
    ANTENNAGATEAREA 1.673100 ;
    PORT
      LAYER Metal3 ;
        RECT 184.400 242.140 184.800 242.540 ;
    END
  END Tile_X0Y0_W2END[4]
  PIN Tile_X0Y0_W2END[5]
    DIRECTION INPUT ;
    USE SIGNAL ;
    ANTENNAGATEAREA 0.426400 ;
    PORT
      LAYER Metal3 ;
        RECT 184.400 243.820 184.800 244.220 ;
    END
  END Tile_X0Y0_W2END[5]
  PIN Tile_X0Y0_W2END[6]
    DIRECTION INPUT ;
    USE SIGNAL ;
    ANTENNAGATEAREA 0.426400 ;
    PORT
      LAYER Metal3 ;
        RECT 184.400 245.500 184.800 245.900 ;
    END
  END Tile_X0Y0_W2END[6]
  PIN Tile_X0Y0_W2END[7]
    DIRECTION INPUT ;
    USE SIGNAL ;
    ANTENNAGATEAREA 0.833300 ;
    PORT
      LAYER Metal3 ;
        RECT 184.400 247.180 184.800 247.580 ;
    END
  END Tile_X0Y0_W2END[7]
  PIN Tile_X0Y0_W2MID[0]
    DIRECTION INPUT ;
    USE SIGNAL ;
    ANTENNAGATEAREA 0.899100 ;
    PORT
      LAYER Metal3 ;
        RECT 184.400 221.980 184.800 222.380 ;
    END
  END Tile_X0Y0_W2MID[0]
  PIN Tile_X0Y0_W2MID[1]
    DIRECTION INPUT ;
    USE SIGNAL ;
    ANTENNAGATEAREA 1.059500 ;
    PORT
      LAYER Metal3 ;
        RECT 184.400 223.660 184.800 224.060 ;
    END
  END Tile_X0Y0_W2MID[1]
  PIN Tile_X0Y0_W2MID[2]
    DIRECTION INPUT ;
    USE SIGNAL ;
    ANTENNAGATEAREA 0.820300 ;
    PORT
      LAYER Metal3 ;
        RECT 184.400 225.340 184.800 225.740 ;
    END
  END Tile_X0Y0_W2MID[2]
  PIN Tile_X0Y0_W2MID[3]
    DIRECTION INPUT ;
    USE SIGNAL ;
    ANTENNAGATEAREA 1.090700 ;
    PORT
      LAYER Metal3 ;
        RECT 184.400 227.020 184.800 227.420 ;
    END
  END Tile_X0Y0_W2MID[3]
  PIN Tile_X0Y0_W2MID[4]
    DIRECTION INPUT ;
    USE SIGNAL ;
    ANTENNAGATEAREA 0.820300 ;
    PORT
      LAYER Metal3 ;
        RECT 184.400 228.700 184.800 229.100 ;
    END
  END Tile_X0Y0_W2MID[4]
  PIN Tile_X0Y0_W2MID[5]
    DIRECTION INPUT ;
    USE SIGNAL ;
    ANTENNAGATEAREA 1.062100 ;
    PORT
      LAYER Metal3 ;
        RECT 184.400 230.380 184.800 230.780 ;
    END
  END Tile_X0Y0_W2MID[5]
  PIN Tile_X0Y0_W2MID[6]
    DIRECTION INPUT ;
    USE SIGNAL ;
    ANTENNAGATEAREA 0.800800 ;
    PORT
      LAYER Metal3 ;
        RECT 184.400 232.060 184.800 232.460 ;
    END
  END Tile_X0Y0_W2MID[6]
  PIN Tile_X0Y0_W2MID[7]
    DIRECTION INPUT ;
    USE SIGNAL ;
    ANTENNAGATEAREA 5.320900 ;
    ANTENNADIFFAREA 14.107800 ;
    PORT
      LAYER Metal3 ;
        RECT 184.400 233.740 184.800 234.140 ;
    END
  END Tile_X0Y0_W2MID[7]
  PIN Tile_X0Y0_W6BEG[0]
    DIRECTION OUTPUT ;
    USE SIGNAL ;
    ANTENNADIFFAREA 0.708600 ;
    PORT
      LAYER Metal3 ;
        RECT 0.000 275.740 0.400 276.140 ;
    END
  END Tile_X0Y0_W6BEG[0]
  PIN Tile_X0Y0_W6BEG[10]
    DIRECTION OUTPUT ;
    USE SIGNAL ;
    ANTENNADIFFAREA 0.708600 ;
    PORT
      LAYER Metal3 ;
        RECT 0.000 292.540 0.400 292.940 ;
    END
  END Tile_X0Y0_W6BEG[10]
  PIN Tile_X0Y0_W6BEG[11]
    DIRECTION OUTPUT ;
    USE SIGNAL ;
    ANTENNADIFFAREA 0.708600 ;
    PORT
      LAYER Metal3 ;
        RECT 0.000 294.220 0.400 294.620 ;
    END
  END Tile_X0Y0_W6BEG[11]
  PIN Tile_X0Y0_W6BEG[1]
    DIRECTION OUTPUT ;
    USE SIGNAL ;
    ANTENNADIFFAREA 0.708600 ;
    PORT
      LAYER Metal3 ;
        RECT 0.000 277.420 0.400 277.820 ;
    END
  END Tile_X0Y0_W6BEG[1]
  PIN Tile_X0Y0_W6BEG[2]
    DIRECTION OUTPUT ;
    USE SIGNAL ;
    ANTENNADIFFAREA 0.708600 ;
    PORT
      LAYER Metal3 ;
        RECT 0.000 279.100 0.400 279.500 ;
    END
  END Tile_X0Y0_W6BEG[2]
  PIN Tile_X0Y0_W6BEG[3]
    DIRECTION OUTPUT ;
    USE SIGNAL ;
    ANTENNADIFFAREA 0.708600 ;
    PORT
      LAYER Metal3 ;
        RECT 0.000 280.780 0.400 281.180 ;
    END
  END Tile_X0Y0_W6BEG[3]
  PIN Tile_X0Y0_W6BEG[4]
    DIRECTION OUTPUT ;
    USE SIGNAL ;
    ANTENNADIFFAREA 0.708600 ;
    PORT
      LAYER Metal3 ;
        RECT 0.000 282.460 0.400 282.860 ;
    END
  END Tile_X0Y0_W6BEG[4]
  PIN Tile_X0Y0_W6BEG[5]
    DIRECTION OUTPUT ;
    USE SIGNAL ;
    ANTENNADIFFAREA 0.708600 ;
    PORT
      LAYER Metal3 ;
        RECT 0.000 284.140 0.400 284.540 ;
    END
  END Tile_X0Y0_W6BEG[5]
  PIN Tile_X0Y0_W6BEG[6]
    DIRECTION OUTPUT ;
    USE SIGNAL ;
    ANTENNADIFFAREA 0.708600 ;
    PORT
      LAYER Metal3 ;
        RECT 0.000 285.820 0.400 286.220 ;
    END
  END Tile_X0Y0_W6BEG[6]
  PIN Tile_X0Y0_W6BEG[7]
    DIRECTION OUTPUT ;
    USE SIGNAL ;
    ANTENNADIFFAREA 0.708600 ;
    PORT
      LAYER Metal3 ;
        RECT 0.000 287.500 0.400 287.900 ;
    END
  END Tile_X0Y0_W6BEG[7]
  PIN Tile_X0Y0_W6BEG[8]
    DIRECTION OUTPUT ;
    USE SIGNAL ;
    ANTENNADIFFAREA 0.708600 ;
    PORT
      LAYER Metal3 ;
        RECT 0.000 289.180 0.400 289.580 ;
    END
  END Tile_X0Y0_W6BEG[8]
  PIN Tile_X0Y0_W6BEG[9]
    DIRECTION OUTPUT ;
    USE SIGNAL ;
    ANTENNADIFFAREA 0.708600 ;
    PORT
      LAYER Metal3 ;
        RECT 0.000 290.860 0.400 291.260 ;
    END
  END Tile_X0Y0_W6BEG[9]
  PIN Tile_X0Y0_W6END[0]
    DIRECTION INPUT ;
    USE SIGNAL ;
    ANTENNAGATEAREA 1.970800 ;
    PORT
      LAYER Metal3 ;
        RECT 184.400 275.740 184.800 276.140 ;
    END
  END Tile_X0Y0_W6END[0]
  PIN Tile_X0Y0_W6END[10]
    DIRECTION INPUT ;
    USE SIGNAL ;
    ANTENNAGATEAREA 0.180700 ;
    PORT
      LAYER Metal3 ;
        RECT 184.400 292.540 184.800 292.940 ;
    END
  END Tile_X0Y0_W6END[10]
  PIN Tile_X0Y0_W6END[11]
    DIRECTION INPUT ;
    USE SIGNAL ;
    ANTENNAGATEAREA 0.180700 ;
    PORT
      LAYER Metal3 ;
        RECT 184.400 294.220 184.800 294.620 ;
    END
  END Tile_X0Y0_W6END[11]
  PIN Tile_X0Y0_W6END[1]
    DIRECTION INPUT ;
    USE SIGNAL ;
    ANTENNAGATEAREA 1.386600 ;
    PORT
      LAYER Metal3 ;
        RECT 184.400 277.420 184.800 277.820 ;
    END
  END Tile_X0Y0_W6END[1]
  PIN Tile_X0Y0_W6END[2]
    DIRECTION INPUT ;
    USE SIGNAL ;
    ANTENNAGATEAREA 0.180700 ;
    PORT
      LAYER Metal3 ;
        RECT 184.400 279.100 184.800 279.500 ;
    END
  END Tile_X0Y0_W6END[2]
  PIN Tile_X0Y0_W6END[3]
    DIRECTION INPUT ;
    USE SIGNAL ;
    ANTENNAGATEAREA 0.180700 ;
    PORT
      LAYER Metal3 ;
        RECT 184.400 280.780 184.800 281.180 ;
    END
  END Tile_X0Y0_W6END[3]
  PIN Tile_X0Y0_W6END[4]
    DIRECTION INPUT ;
    USE SIGNAL ;
    ANTENNAGATEAREA 0.180700 ;
    PORT
      LAYER Metal3 ;
        RECT 184.400 282.460 184.800 282.860 ;
    END
  END Tile_X0Y0_W6END[4]
  PIN Tile_X0Y0_W6END[5]
    DIRECTION INPUT ;
    USE SIGNAL ;
    ANTENNAGATEAREA 0.180700 ;
    PORT
      LAYER Metal3 ;
        RECT 184.400 284.140 184.800 284.540 ;
    END
  END Tile_X0Y0_W6END[5]
  PIN Tile_X0Y0_W6END[6]
    DIRECTION INPUT ;
    USE SIGNAL ;
    ANTENNAGATEAREA 0.180700 ;
    PORT
      LAYER Metal3 ;
        RECT 184.400 285.820 184.800 286.220 ;
    END
  END Tile_X0Y0_W6END[6]
  PIN Tile_X0Y0_W6END[7]
    DIRECTION INPUT ;
    USE SIGNAL ;
    ANTENNAGATEAREA 0.180700 ;
    PORT
      LAYER Metal3 ;
        RECT 184.400 287.500 184.800 287.900 ;
    END
  END Tile_X0Y0_W6END[7]
  PIN Tile_X0Y0_W6END[8]
    DIRECTION INPUT ;
    USE SIGNAL ;
    ANTENNAGATEAREA 0.180700 ;
    PORT
      LAYER Metal3 ;
        RECT 184.400 289.180 184.800 289.580 ;
    END
  END Tile_X0Y0_W6END[8]
  PIN Tile_X0Y0_W6END[9]
    DIRECTION INPUT ;
    USE SIGNAL ;
    ANTENNAGATEAREA 0.180700 ;
    PORT
      LAYER Metal3 ;
        RECT 184.400 290.860 184.800 291.260 ;
    END
  END Tile_X0Y0_W6END[9]
  PIN Tile_X0Y0_WW4BEG[0]
    DIRECTION OUTPUT ;
    USE SIGNAL ;
    ANTENNADIFFAREA 0.708600 ;
    PORT
      LAYER Metal3 ;
        RECT 0.000 248.860 0.400 249.260 ;
    END
  END Tile_X0Y0_WW4BEG[0]
  PIN Tile_X0Y0_WW4BEG[10]
    DIRECTION OUTPUT ;
    USE SIGNAL ;
    ANTENNADIFFAREA 0.708600 ;
    PORT
      LAYER Metal3 ;
        RECT 0.000 265.660 0.400 266.060 ;
    END
  END Tile_X0Y0_WW4BEG[10]
  PIN Tile_X0Y0_WW4BEG[11]
    DIRECTION OUTPUT ;
    USE SIGNAL ;
    ANTENNADIFFAREA 0.708600 ;
    PORT
      LAYER Metal3 ;
        RECT 0.000 267.340 0.400 267.740 ;
    END
  END Tile_X0Y0_WW4BEG[11]
  PIN Tile_X0Y0_WW4BEG[12]
    DIRECTION OUTPUT ;
    USE SIGNAL ;
    ANTENNADIFFAREA 0.708600 ;
    PORT
      LAYER Metal3 ;
        RECT 0.000 269.020 0.400 269.420 ;
    END
  END Tile_X0Y0_WW4BEG[12]
  PIN Tile_X0Y0_WW4BEG[13]
    DIRECTION OUTPUT ;
    USE SIGNAL ;
    ANTENNADIFFAREA 0.708600 ;
    PORT
      LAYER Metal3 ;
        RECT 0.000 270.700 0.400 271.100 ;
    END
  END Tile_X0Y0_WW4BEG[13]
  PIN Tile_X0Y0_WW4BEG[14]
    DIRECTION OUTPUT ;
    USE SIGNAL ;
    ANTENNADIFFAREA 0.708600 ;
    PORT
      LAYER Metal3 ;
        RECT 0.000 272.380 0.400 272.780 ;
    END
  END Tile_X0Y0_WW4BEG[14]
  PIN Tile_X0Y0_WW4BEG[15]
    DIRECTION OUTPUT ;
    USE SIGNAL ;
    ANTENNADIFFAREA 0.708600 ;
    PORT
      LAYER Metal3 ;
        RECT 0.000 274.060 0.400 274.460 ;
    END
  END Tile_X0Y0_WW4BEG[15]
  PIN Tile_X0Y0_WW4BEG[1]
    DIRECTION OUTPUT ;
    USE SIGNAL ;
    ANTENNADIFFAREA 0.708600 ;
    PORT
      LAYER Metal3 ;
        RECT 0.000 250.540 0.400 250.940 ;
    END
  END Tile_X0Y0_WW4BEG[1]
  PIN Tile_X0Y0_WW4BEG[2]
    DIRECTION OUTPUT ;
    USE SIGNAL ;
    ANTENNADIFFAREA 0.708600 ;
    PORT
      LAYER Metal3 ;
        RECT 0.000 252.220 0.400 252.620 ;
    END
  END Tile_X0Y0_WW4BEG[2]
  PIN Tile_X0Y0_WW4BEG[3]
    DIRECTION OUTPUT ;
    USE SIGNAL ;
    ANTENNADIFFAREA 0.708600 ;
    PORT
      LAYER Metal3 ;
        RECT 0.000 253.900 0.400 254.300 ;
    END
  END Tile_X0Y0_WW4BEG[3]
  PIN Tile_X0Y0_WW4BEG[4]
    DIRECTION OUTPUT ;
    USE SIGNAL ;
    ANTENNADIFFAREA 0.708600 ;
    PORT
      LAYER Metal3 ;
        RECT 0.000 255.580 0.400 255.980 ;
    END
  END Tile_X0Y0_WW4BEG[4]
  PIN Tile_X0Y0_WW4BEG[5]
    DIRECTION OUTPUT ;
    USE SIGNAL ;
    ANTENNADIFFAREA 0.708600 ;
    PORT
      LAYER Metal3 ;
        RECT 0.000 257.260 0.400 257.660 ;
    END
  END Tile_X0Y0_WW4BEG[5]
  PIN Tile_X0Y0_WW4BEG[6]
    DIRECTION OUTPUT ;
    USE SIGNAL ;
    ANTENNADIFFAREA 0.708600 ;
    PORT
      LAYER Metal3 ;
        RECT 0.000 258.940 0.400 259.340 ;
    END
  END Tile_X0Y0_WW4BEG[6]
  PIN Tile_X0Y0_WW4BEG[7]
    DIRECTION OUTPUT ;
    USE SIGNAL ;
    ANTENNADIFFAREA 0.708600 ;
    PORT
      LAYER Metal3 ;
        RECT 0.000 260.620 0.400 261.020 ;
    END
  END Tile_X0Y0_WW4BEG[7]
  PIN Tile_X0Y0_WW4BEG[8]
    DIRECTION OUTPUT ;
    USE SIGNAL ;
    ANTENNADIFFAREA 0.708600 ;
    PORT
      LAYER Metal3 ;
        RECT 0.000 262.300 0.400 262.700 ;
    END
  END Tile_X0Y0_WW4BEG[8]
  PIN Tile_X0Y0_WW4BEG[9]
    DIRECTION OUTPUT ;
    USE SIGNAL ;
    ANTENNADIFFAREA 0.708600 ;
    PORT
      LAYER Metal3 ;
        RECT 0.000 263.980 0.400 264.380 ;
    END
  END Tile_X0Y0_WW4BEG[9]
  PIN Tile_X0Y0_WW4END[0]
    DIRECTION INPUT ;
    USE SIGNAL ;
    ANTENNAGATEAREA 0.639600 ;
    PORT
      LAYER Metal3 ;
        RECT 184.400 248.860 184.800 249.260 ;
    END
  END Tile_X0Y0_WW4END[0]
  PIN Tile_X0Y0_WW4END[10]
    DIRECTION INPUT ;
    USE SIGNAL ;
    ANTENNAGATEAREA 0.180700 ;
    PORT
      LAYER Metal3 ;
        RECT 184.400 265.660 184.800 266.060 ;
    END
  END Tile_X0Y0_WW4END[10]
  PIN Tile_X0Y0_WW4END[11]
    DIRECTION INPUT ;
    USE SIGNAL ;
    ANTENNAGATEAREA 0.180700 ;
    PORT
      LAYER Metal3 ;
        RECT 184.400 267.340 184.800 267.740 ;
    END
  END Tile_X0Y0_WW4END[11]
  PIN Tile_X0Y0_WW4END[12]
    DIRECTION INPUT ;
    USE SIGNAL ;
    ANTENNAGATEAREA 0.180700 ;
    PORT
      LAYER Metal3 ;
        RECT 184.400 269.020 184.800 269.420 ;
    END
  END Tile_X0Y0_WW4END[12]
  PIN Tile_X0Y0_WW4END[13]
    DIRECTION INPUT ;
    USE SIGNAL ;
    ANTENNAGATEAREA 0.180700 ;
    PORT
      LAYER Metal3 ;
        RECT 184.400 270.700 184.800 271.100 ;
    END
  END Tile_X0Y0_WW4END[13]
  PIN Tile_X0Y0_WW4END[14]
    DIRECTION INPUT ;
    USE SIGNAL ;
    ANTENNAGATEAREA 0.180700 ;
    PORT
      LAYER Metal3 ;
        RECT 184.400 272.380 184.800 272.780 ;
    END
  END Tile_X0Y0_WW4END[14]
  PIN Tile_X0Y0_WW4END[15]
    DIRECTION INPUT ;
    USE SIGNAL ;
    ANTENNAGATEAREA 0.180700 ;
    PORT
      LAYER Metal3 ;
        RECT 184.400 274.060 184.800 274.460 ;
    END
  END Tile_X0Y0_WW4END[15]
  PIN Tile_X0Y0_WW4END[1]
    DIRECTION INPUT ;
    USE SIGNAL ;
    ANTENNAGATEAREA 0.652600 ;
    PORT
      LAYER Metal3 ;
        RECT 184.400 250.540 184.800 250.940 ;
    END
  END Tile_X0Y0_WW4END[1]
  PIN Tile_X0Y0_WW4END[2]
    DIRECTION INPUT ;
    USE SIGNAL ;
    ANTENNAGATEAREA 0.652600 ;
    PORT
      LAYER Metal3 ;
        RECT 184.400 252.220 184.800 252.620 ;
    END
  END Tile_X0Y0_WW4END[2]
  PIN Tile_X0Y0_WW4END[3]
    DIRECTION INPUT ;
    USE SIGNAL ;
    ANTENNAGATEAREA 0.705400 ;
    PORT
      LAYER Metal3 ;
        RECT 184.400 253.900 184.800 254.300 ;
    END
  END Tile_X0Y0_WW4END[3]
  PIN Tile_X0Y0_WW4END[4]
    DIRECTION INPUT ;
    USE SIGNAL ;
    ANTENNAGATEAREA 0.180700 ;
    PORT
      LAYER Metal3 ;
        RECT 184.400 255.580 184.800 255.980 ;
    END
  END Tile_X0Y0_WW4END[4]
  PIN Tile_X0Y0_WW4END[5]
    DIRECTION INPUT ;
    USE SIGNAL ;
    ANTENNAGATEAREA 0.180700 ;
    PORT
      LAYER Metal3 ;
        RECT 184.400 257.260 184.800 257.660 ;
    END
  END Tile_X0Y0_WW4END[5]
  PIN Tile_X0Y0_WW4END[6]
    DIRECTION INPUT ;
    USE SIGNAL ;
    ANTENNAGATEAREA 0.180700 ;
    PORT
      LAYER Metal3 ;
        RECT 184.400 258.940 184.800 259.340 ;
    END
  END Tile_X0Y0_WW4END[6]
  PIN Tile_X0Y0_WW4END[7]
    DIRECTION INPUT ;
    USE SIGNAL ;
    ANTENNAGATEAREA 0.180700 ;
    PORT
      LAYER Metal3 ;
        RECT 184.400 260.620 184.800 261.020 ;
    END
  END Tile_X0Y0_WW4END[7]
  PIN Tile_X0Y0_WW4END[8]
    DIRECTION INPUT ;
    USE SIGNAL ;
    ANTENNAGATEAREA 0.180700 ;
    PORT
      LAYER Metal3 ;
        RECT 184.400 262.300 184.800 262.700 ;
    END
  END Tile_X0Y0_WW4END[8]
  PIN Tile_X0Y0_WW4END[9]
    DIRECTION INPUT ;
    USE SIGNAL ;
    ANTENNAGATEAREA 0.180700 ;
    PORT
      LAYER Metal3 ;
        RECT 184.400 263.980 184.800 264.380 ;
    END
  END Tile_X0Y0_WW4END[9]
  PIN Tile_X0Y1_E1BEG[0]
    DIRECTION OUTPUT ;
    USE SIGNAL ;
    ANTENNADIFFAREA 0.708600 ;
    PORT
      LAYER Metal3 ;
        RECT 184.400 80.860 184.800 81.260 ;
    END
  END Tile_X0Y1_E1BEG[0]
  PIN Tile_X0Y1_E1BEG[1]
    DIRECTION OUTPUT ;
    USE SIGNAL ;
    ANTENNADIFFAREA 0.708600 ;
    PORT
      LAYER Metal3 ;
        RECT 184.400 82.540 184.800 82.940 ;
    END
  END Tile_X0Y1_E1BEG[1]
  PIN Tile_X0Y1_E1BEG[2]
    DIRECTION OUTPUT ;
    USE SIGNAL ;
    ANTENNADIFFAREA 0.708600 ;
    PORT
      LAYER Metal3 ;
        RECT 184.400 84.220 184.800 84.620 ;
    END
  END Tile_X0Y1_E1BEG[2]
  PIN Tile_X0Y1_E1BEG[3]
    DIRECTION OUTPUT ;
    USE SIGNAL ;
    ANTENNADIFFAREA 0.708600 ;
    PORT
      LAYER Metal3 ;
        RECT 184.400 85.900 184.800 86.300 ;
    END
  END Tile_X0Y1_E1BEG[3]
  PIN Tile_X0Y1_E1END[0]
    DIRECTION INPUT ;
    USE SIGNAL ;
    ANTENNAGATEAREA 1.918800 ;
    PORT
      LAYER Metal3 ;
        RECT 0.000 80.860 0.400 81.260 ;
    END
  END Tile_X0Y1_E1END[0]
  PIN Tile_X0Y1_E1END[1]
    DIRECTION INPUT ;
    USE SIGNAL ;
    ANTENNAGATEAREA 1.918800 ;
    PORT
      LAYER Metal3 ;
        RECT 0.000 82.540 0.400 82.940 ;
    END
  END Tile_X0Y1_E1END[1]
  PIN Tile_X0Y1_E1END[2]
    DIRECTION INPUT ;
    USE SIGNAL ;
    ANTENNAGATEAREA 2.411000 ;
    PORT
      LAYER Metal3 ;
        RECT 0.000 84.220 0.400 84.620 ;
    END
  END Tile_X0Y1_E1END[2]
  PIN Tile_X0Y1_E1END[3]
    DIRECTION INPUT ;
    USE SIGNAL ;
    ANTENNAGATEAREA 2.373800 ;
    PORT
      LAYER Metal3 ;
        RECT 0.000 85.900 0.400 86.300 ;
    END
  END Tile_X0Y1_E1END[3]
  PIN Tile_X0Y1_E2BEG[0]
    DIRECTION OUTPUT ;
    USE SIGNAL ;
    ANTENNADIFFAREA 0.708600 ;
    PORT
      LAYER Metal3 ;
        RECT 184.400 87.580 184.800 87.980 ;
    END
  END Tile_X0Y1_E2BEG[0]
  PIN Tile_X0Y1_E2BEG[1]
    DIRECTION OUTPUT ;
    USE SIGNAL ;
    ANTENNADIFFAREA 0.708600 ;
    PORT
      LAYER Metal3 ;
        RECT 184.400 89.260 184.800 89.660 ;
    END
  END Tile_X0Y1_E2BEG[1]
  PIN Tile_X0Y1_E2BEG[2]
    DIRECTION OUTPUT ;
    USE SIGNAL ;
    ANTENNADIFFAREA 0.708600 ;
    PORT
      LAYER Metal3 ;
        RECT 184.400 90.940 184.800 91.340 ;
    END
  END Tile_X0Y1_E2BEG[2]
  PIN Tile_X0Y1_E2BEG[3]
    DIRECTION OUTPUT ;
    USE SIGNAL ;
    ANTENNADIFFAREA 0.708600 ;
    PORT
      LAYER Metal3 ;
        RECT 184.400 92.620 184.800 93.020 ;
    END
  END Tile_X0Y1_E2BEG[3]
  PIN Tile_X0Y1_E2BEG[4]
    DIRECTION OUTPUT ;
    USE SIGNAL ;
    ANTENNADIFFAREA 0.708600 ;
    PORT
      LAYER Metal3 ;
        RECT 184.400 94.300 184.800 94.700 ;
    END
  END Tile_X0Y1_E2BEG[4]
  PIN Tile_X0Y1_E2BEG[5]
    DIRECTION OUTPUT ;
    USE SIGNAL ;
    ANTENNADIFFAREA 0.708600 ;
    PORT
      LAYER Metal3 ;
        RECT 184.400 95.980 184.800 96.380 ;
    END
  END Tile_X0Y1_E2BEG[5]
  PIN Tile_X0Y1_E2BEG[6]
    DIRECTION OUTPUT ;
    USE SIGNAL ;
    ANTENNADIFFAREA 0.708600 ;
    PORT
      LAYER Metal3 ;
        RECT 184.400 97.660 184.800 98.060 ;
    END
  END Tile_X0Y1_E2BEG[6]
  PIN Tile_X0Y1_E2BEG[7]
    DIRECTION OUTPUT ;
    USE SIGNAL ;
    ANTENNADIFFAREA 0.708600 ;
    PORT
      LAYER Metal3 ;
        RECT 184.400 99.340 184.800 99.740 ;
    END
  END Tile_X0Y1_E2BEG[7]
  PIN Tile_X0Y1_E2BEGb[0]
    DIRECTION OUTPUT ;
    USE SIGNAL ;
    ANTENNADIFFAREA 0.708600 ;
    PORT
      LAYER Metal3 ;
        RECT 184.400 101.020 184.800 101.420 ;
    END
  END Tile_X0Y1_E2BEGb[0]
  PIN Tile_X0Y1_E2BEGb[1]
    DIRECTION OUTPUT ;
    USE SIGNAL ;
    ANTENNADIFFAREA 0.708600 ;
    PORT
      LAYER Metal3 ;
        RECT 184.400 102.700 184.800 103.100 ;
    END
  END Tile_X0Y1_E2BEGb[1]
  PIN Tile_X0Y1_E2BEGb[2]
    DIRECTION OUTPUT ;
    USE SIGNAL ;
    ANTENNADIFFAREA 0.708600 ;
    PORT
      LAYER Metal3 ;
        RECT 184.400 104.380 184.800 104.780 ;
    END
  END Tile_X0Y1_E2BEGb[2]
  PIN Tile_X0Y1_E2BEGb[3]
    DIRECTION OUTPUT ;
    USE SIGNAL ;
    ANTENNADIFFAREA 0.708600 ;
    PORT
      LAYER Metal3 ;
        RECT 184.400 106.060 184.800 106.460 ;
    END
  END Tile_X0Y1_E2BEGb[3]
  PIN Tile_X0Y1_E2BEGb[4]
    DIRECTION OUTPUT ;
    USE SIGNAL ;
    ANTENNADIFFAREA 0.708600 ;
    PORT
      LAYER Metal3 ;
        RECT 184.400 107.740 184.800 108.140 ;
    END
  END Tile_X0Y1_E2BEGb[4]
  PIN Tile_X0Y1_E2BEGb[5]
    DIRECTION OUTPUT ;
    USE SIGNAL ;
    ANTENNADIFFAREA 0.708600 ;
    PORT
      LAYER Metal3 ;
        RECT 184.400 109.420 184.800 109.820 ;
    END
  END Tile_X0Y1_E2BEGb[5]
  PIN Tile_X0Y1_E2BEGb[6]
    DIRECTION OUTPUT ;
    USE SIGNAL ;
    ANTENNADIFFAREA 0.708600 ;
    PORT
      LAYER Metal3 ;
        RECT 184.400 111.100 184.800 111.500 ;
    END
  END Tile_X0Y1_E2BEGb[6]
  PIN Tile_X0Y1_E2BEGb[7]
    DIRECTION OUTPUT ;
    USE SIGNAL ;
    ANTENNADIFFAREA 0.708600 ;
    PORT
      LAYER Metal3 ;
        RECT 184.400 112.780 184.800 113.180 ;
    END
  END Tile_X0Y1_E2BEGb[7]
  PIN Tile_X0Y1_E2END[0]
    DIRECTION INPUT ;
    USE SIGNAL ;
    ANTENNAGATEAREA 0.852800 ;
    PORT
      LAYER Metal3 ;
        RECT 0.000 101.020 0.400 101.420 ;
    END
  END Tile_X0Y1_E2END[0]
  PIN Tile_X0Y1_E2END[1]
    DIRECTION INPUT ;
    USE SIGNAL ;
    ANTENNAGATEAREA 0.865800 ;
    PORT
      LAYER Metal3 ;
        RECT 0.000 102.700 0.400 103.100 ;
    END
  END Tile_X0Y1_E2END[1]
  PIN Tile_X0Y1_E2END[2]
    DIRECTION INPUT ;
    USE SIGNAL ;
    ANTENNAGATEAREA 1.459900 ;
    PORT
      LAYER Metal3 ;
        RECT 0.000 104.380 0.400 104.780 ;
    END
  END Tile_X0Y1_E2END[2]
  PIN Tile_X0Y1_E2END[3]
    DIRECTION INPUT ;
    USE SIGNAL ;
    ANTENNAGATEAREA 1.701700 ;
    PORT
      LAYER Metal3 ;
        RECT 0.000 106.060 0.400 106.460 ;
    END
  END Tile_X0Y1_E2END[3]
  PIN Tile_X0Y1_E2END[4]
    DIRECTION INPUT ;
    USE SIGNAL ;
    ANTENNAGATEAREA 1.001000 ;
    PORT
      LAYER Metal3 ;
        RECT 0.000 107.740 0.400 108.140 ;
    END
  END Tile_X0Y1_E2END[4]
  PIN Tile_X0Y1_E2END[5]
    DIRECTION INPUT ;
    USE SIGNAL ;
    ANTENNAGATEAREA 1.279200 ;
    PORT
      LAYER Metal3 ;
        RECT 0.000 109.420 0.400 109.820 ;
    END
  END Tile_X0Y1_E2END[5]
  PIN Tile_X0Y1_E2END[6]
    DIRECTION INPUT ;
    USE SIGNAL ;
    ANTENNAGATEAREA 1.279200 ;
    PORT
      LAYER Metal3 ;
        RECT 0.000 111.100 0.400 111.500 ;
    END
  END Tile_X0Y1_E2END[6]
  PIN Tile_X0Y1_E2END[7]
    DIRECTION INPUT ;
    USE SIGNAL ;
    ANTENNAGATEAREA 1.066000 ;
    PORT
      LAYER Metal3 ;
        RECT 0.000 112.780 0.400 113.180 ;
    END
  END Tile_X0Y1_E2END[7]
  PIN Tile_X0Y1_E2MID[0]
    DIRECTION INPUT ;
    USE SIGNAL ;
    ANTENNAGATEAREA 1.058200 ;
    PORT
      LAYER Metal3 ;
        RECT 0.000 87.580 0.400 87.980 ;
    END
  END Tile_X0Y1_E2MID[0]
  PIN Tile_X0Y1_E2MID[1]
    DIRECTION INPUT ;
    USE SIGNAL ;
    ANTENNAGATEAREA 0.936000 ;
    PORT
      LAYER Metal3 ;
        RECT 0.000 89.260 0.400 89.660 ;
    END
  END Tile_X0Y1_E2MID[1]
  PIN Tile_X0Y1_E2MID[2]
    DIRECTION INPUT ;
    USE SIGNAL ;
    ANTENNAGATEAREA 0.874900 ;
    PORT
      LAYER Metal3 ;
        RECT 0.000 90.940 0.400 91.340 ;
    END
  END Tile_X0Y1_E2MID[2]
  PIN Tile_X0Y1_E2MID[3]
    DIRECTION INPUT ;
    USE SIGNAL ;
    ANTENNAGATEAREA 0.848900 ;
    PORT
      LAYER Metal3 ;
        RECT 0.000 92.620 0.400 93.020 ;
    END
  END Tile_X0Y1_E2MID[3]
  PIN Tile_X0Y1_E2MID[4]
    DIRECTION INPUT ;
    USE SIGNAL ;
    ANTENNAGATEAREA 0.664300 ;
    PORT
      LAYER Metal3 ;
        RECT 0.000 94.300 0.400 94.700 ;
    END
  END Tile_X0Y1_E2MID[4]
  PIN Tile_X0Y1_E2MID[5]
    DIRECTION INPUT ;
    USE SIGNAL ;
    ANTENNAGATEAREA 1.033500 ;
    PORT
      LAYER Metal3 ;
        RECT 0.000 95.980 0.400 96.380 ;
    END
  END Tile_X0Y1_E2MID[5]
  PIN Tile_X0Y1_E2MID[6]
    DIRECTION INPUT ;
    USE SIGNAL ;
    ANTENNAGATEAREA 1.042600 ;
    PORT
      LAYER Metal3 ;
        RECT 0.000 97.660 0.400 98.060 ;
    END
  END Tile_X0Y1_E2MID[6]
  PIN Tile_X0Y1_E2MID[7]
    DIRECTION INPUT ;
    USE SIGNAL ;
    ANTENNAGATEAREA 0.936000 ;
    PORT
      LAYER Metal3 ;
        RECT 0.000 99.340 0.400 99.740 ;
    END
  END Tile_X0Y1_E2MID[7]
  PIN Tile_X0Y1_E6BEG[0]
    DIRECTION OUTPUT ;
    USE SIGNAL ;
    ANTENNADIFFAREA 0.708600 ;
    PORT
      LAYER Metal3 ;
        RECT 184.400 141.340 184.800 141.740 ;
    END
  END Tile_X0Y1_E6BEG[0]
  PIN Tile_X0Y1_E6BEG[10]
    DIRECTION OUTPUT ;
    USE SIGNAL ;
    ANTENNADIFFAREA 0.708600 ;
    PORT
      LAYER Metal3 ;
        RECT 184.400 158.140 184.800 158.540 ;
    END
  END Tile_X0Y1_E6BEG[10]
  PIN Tile_X0Y1_E6BEG[11]
    DIRECTION OUTPUT ;
    USE SIGNAL ;
    ANTENNADIFFAREA 0.708600 ;
    PORT
      LAYER Metal3 ;
        RECT 184.400 159.820 184.800 160.220 ;
    END
  END Tile_X0Y1_E6BEG[11]
  PIN Tile_X0Y1_E6BEG[1]
    DIRECTION OUTPUT ;
    USE SIGNAL ;
    ANTENNADIFFAREA 0.708600 ;
    PORT
      LAYER Metal3 ;
        RECT 184.400 143.020 184.800 143.420 ;
    END
  END Tile_X0Y1_E6BEG[1]
  PIN Tile_X0Y1_E6BEG[2]
    DIRECTION OUTPUT ;
    USE SIGNAL ;
    ANTENNADIFFAREA 0.708600 ;
    PORT
      LAYER Metal3 ;
        RECT 184.400 144.700 184.800 145.100 ;
    END
  END Tile_X0Y1_E6BEG[2]
  PIN Tile_X0Y1_E6BEG[3]
    DIRECTION OUTPUT ;
    USE SIGNAL ;
    ANTENNADIFFAREA 0.708600 ;
    PORT
      LAYER Metal3 ;
        RECT 184.400 146.380 184.800 146.780 ;
    END
  END Tile_X0Y1_E6BEG[3]
  PIN Tile_X0Y1_E6BEG[4]
    DIRECTION OUTPUT ;
    USE SIGNAL ;
    ANTENNADIFFAREA 0.708600 ;
    PORT
      LAYER Metal3 ;
        RECT 184.400 148.060 184.800 148.460 ;
    END
  END Tile_X0Y1_E6BEG[4]
  PIN Tile_X0Y1_E6BEG[5]
    DIRECTION OUTPUT ;
    USE SIGNAL ;
    ANTENNADIFFAREA 0.708600 ;
    PORT
      LAYER Metal3 ;
        RECT 184.400 149.740 184.800 150.140 ;
    END
  END Tile_X0Y1_E6BEG[5]
  PIN Tile_X0Y1_E6BEG[6]
    DIRECTION OUTPUT ;
    USE SIGNAL ;
    ANTENNADIFFAREA 0.708600 ;
    PORT
      LAYER Metal3 ;
        RECT 184.400 151.420 184.800 151.820 ;
    END
  END Tile_X0Y1_E6BEG[6]
  PIN Tile_X0Y1_E6BEG[7]
    DIRECTION OUTPUT ;
    USE SIGNAL ;
    ANTENNADIFFAREA 0.708600 ;
    PORT
      LAYER Metal3 ;
        RECT 184.400 153.100 184.800 153.500 ;
    END
  END Tile_X0Y1_E6BEG[7]
  PIN Tile_X0Y1_E6BEG[8]
    DIRECTION OUTPUT ;
    USE SIGNAL ;
    ANTENNADIFFAREA 0.708600 ;
    PORT
      LAYER Metal3 ;
        RECT 184.400 154.780 184.800 155.180 ;
    END
  END Tile_X0Y1_E6BEG[8]
  PIN Tile_X0Y1_E6BEG[9]
    DIRECTION OUTPUT ;
    USE SIGNAL ;
    ANTENNADIFFAREA 0.708600 ;
    PORT
      LAYER Metal3 ;
        RECT 184.400 156.460 184.800 156.860 ;
    END
  END Tile_X0Y1_E6BEG[9]
  PIN Tile_X0Y1_E6END[0]
    DIRECTION INPUT ;
    USE SIGNAL ;
    ANTENNAGATEAREA 2.672800 ;
    PORT
      LAYER Metal3 ;
        RECT 0.000 141.340 0.400 141.740 ;
    END
  END Tile_X0Y1_E6END[0]
  PIN Tile_X0Y1_E6END[10]
    DIRECTION INPUT ;
    USE SIGNAL ;
    ANTENNAGATEAREA 0.789100 ;
    ANTENNADIFFAREA 2.015400 ;
    PORT
      LAYER Metal3 ;
        RECT 0.000 158.140 0.400 158.540 ;
    END
  END Tile_X0Y1_E6END[10]
  PIN Tile_X0Y1_E6END[11]
    DIRECTION INPUT ;
    USE SIGNAL ;
    ANTENNAGATEAREA 0.180700 ;
    PORT
      LAYER Metal3 ;
        RECT 0.000 159.820 0.400 160.220 ;
    END
  END Tile_X0Y1_E6END[11]
  PIN Tile_X0Y1_E6END[1]
    DIRECTION INPUT ;
    USE SIGNAL ;
    ANTENNAGATEAREA 2.564900 ;
    PORT
      LAYER Metal3 ;
        RECT 0.000 143.020 0.400 143.420 ;
    END
  END Tile_X0Y1_E6END[1]
  PIN Tile_X0Y1_E6END[2]
    DIRECTION INPUT ;
    USE SIGNAL ;
    ANTENNAGATEAREA 0.789100 ;
    ANTENNADIFFAREA 2.015400 ;
    PORT
      LAYER Metal3 ;
        RECT 0.000 144.700 0.400 145.100 ;
    END
  END Tile_X0Y1_E6END[2]
  PIN Tile_X0Y1_E6END[3]
    DIRECTION INPUT ;
    USE SIGNAL ;
    ANTENNAGATEAREA 0.789100 ;
    ANTENNADIFFAREA 2.015400 ;
    PORT
      LAYER Metal3 ;
        RECT 0.000 146.380 0.400 146.780 ;
    END
  END Tile_X0Y1_E6END[3]
  PIN Tile_X0Y1_E6END[4]
    DIRECTION INPUT ;
    USE SIGNAL ;
    ANTENNAGATEAREA 0.180700 ;
    PORT
      LAYER Metal3 ;
        RECT 0.000 148.060 0.400 148.460 ;
    END
  END Tile_X0Y1_E6END[4]
  PIN Tile_X0Y1_E6END[5]
    DIRECTION INPUT ;
    USE SIGNAL ;
    ANTENNAGATEAREA 0.789100 ;
    ANTENNADIFFAREA 2.015400 ;
    PORT
      LAYER Metal3 ;
        RECT 0.000 149.740 0.400 150.140 ;
    END
  END Tile_X0Y1_E6END[5]
  PIN Tile_X0Y1_E6END[6]
    DIRECTION INPUT ;
    USE SIGNAL ;
    ANTENNAGATEAREA 0.180700 ;
    PORT
      LAYER Metal3 ;
        RECT 0.000 151.420 0.400 151.820 ;
    END
  END Tile_X0Y1_E6END[6]
  PIN Tile_X0Y1_E6END[7]
    DIRECTION INPUT ;
    USE SIGNAL ;
    ANTENNAGATEAREA 0.789100 ;
    ANTENNADIFFAREA 2.015400 ;
    PORT
      LAYER Metal3 ;
        RECT 0.000 153.100 0.400 153.500 ;
    END
  END Tile_X0Y1_E6END[7]
  PIN Tile_X0Y1_E6END[8]
    DIRECTION INPUT ;
    USE SIGNAL ;
    ANTENNAGATEAREA 0.789100 ;
    ANTENNADIFFAREA 2.015400 ;
    PORT
      LAYER Metal3 ;
        RECT 0.000 154.780 0.400 155.180 ;
    END
  END Tile_X0Y1_E6END[8]
  PIN Tile_X0Y1_E6END[9]
    DIRECTION INPUT ;
    USE SIGNAL ;
    ANTENNAGATEAREA 0.180700 ;
    PORT
      LAYER Metal3 ;
        RECT 0.000 156.460 0.400 156.860 ;
    END
  END Tile_X0Y1_E6END[9]
  PIN Tile_X0Y1_EE4BEG[0]
    DIRECTION OUTPUT ;
    USE SIGNAL ;
    ANTENNADIFFAREA 0.708600 ;
    PORT
      LAYER Metal3 ;
        RECT 184.400 114.460 184.800 114.860 ;
    END
  END Tile_X0Y1_EE4BEG[0]
  PIN Tile_X0Y1_EE4BEG[10]
    DIRECTION OUTPUT ;
    USE SIGNAL ;
    ANTENNADIFFAREA 0.708600 ;
    PORT
      LAYER Metal3 ;
        RECT 184.400 131.260 184.800 131.660 ;
    END
  END Tile_X0Y1_EE4BEG[10]
  PIN Tile_X0Y1_EE4BEG[11]
    DIRECTION OUTPUT ;
    USE SIGNAL ;
    ANTENNADIFFAREA 0.708600 ;
    PORT
      LAYER Metal3 ;
        RECT 184.400 132.940 184.800 133.340 ;
    END
  END Tile_X0Y1_EE4BEG[11]
  PIN Tile_X0Y1_EE4BEG[12]
    DIRECTION OUTPUT ;
    USE SIGNAL ;
    ANTENNADIFFAREA 0.708600 ;
    PORT
      LAYER Metal3 ;
        RECT 184.400 134.620 184.800 135.020 ;
    END
  END Tile_X0Y1_EE4BEG[12]
  PIN Tile_X0Y1_EE4BEG[13]
    DIRECTION OUTPUT ;
    USE SIGNAL ;
    ANTENNADIFFAREA 0.708600 ;
    PORT
      LAYER Metal3 ;
        RECT 184.400 136.300 184.800 136.700 ;
    END
  END Tile_X0Y1_EE4BEG[13]
  PIN Tile_X0Y1_EE4BEG[14]
    DIRECTION OUTPUT ;
    USE SIGNAL ;
    ANTENNADIFFAREA 0.708600 ;
    PORT
      LAYER Metal3 ;
        RECT 184.400 137.980 184.800 138.380 ;
    END
  END Tile_X0Y1_EE4BEG[14]
  PIN Tile_X0Y1_EE4BEG[15]
    DIRECTION OUTPUT ;
    USE SIGNAL ;
    ANTENNADIFFAREA 0.708600 ;
    PORT
      LAYER Metal3 ;
        RECT 184.400 139.660 184.800 140.060 ;
    END
  END Tile_X0Y1_EE4BEG[15]
  PIN Tile_X0Y1_EE4BEG[1]
    DIRECTION OUTPUT ;
    USE SIGNAL ;
    ANTENNADIFFAREA 0.708600 ;
    PORT
      LAYER Metal3 ;
        RECT 184.400 116.140 184.800 116.540 ;
    END
  END Tile_X0Y1_EE4BEG[1]
  PIN Tile_X0Y1_EE4BEG[2]
    DIRECTION OUTPUT ;
    USE SIGNAL ;
    ANTENNADIFFAREA 0.708600 ;
    PORT
      LAYER Metal3 ;
        RECT 184.400 117.820 184.800 118.220 ;
    END
  END Tile_X0Y1_EE4BEG[2]
  PIN Tile_X0Y1_EE4BEG[3]
    DIRECTION OUTPUT ;
    USE SIGNAL ;
    ANTENNADIFFAREA 0.708600 ;
    PORT
      LAYER Metal3 ;
        RECT 184.400 119.500 184.800 119.900 ;
    END
  END Tile_X0Y1_EE4BEG[3]
  PIN Tile_X0Y1_EE4BEG[4]
    DIRECTION OUTPUT ;
    USE SIGNAL ;
    ANTENNADIFFAREA 0.708600 ;
    PORT
      LAYER Metal3 ;
        RECT 184.400 121.180 184.800 121.580 ;
    END
  END Tile_X0Y1_EE4BEG[4]
  PIN Tile_X0Y1_EE4BEG[5]
    DIRECTION OUTPUT ;
    USE SIGNAL ;
    ANTENNADIFFAREA 0.708600 ;
    PORT
      LAYER Metal3 ;
        RECT 184.400 122.860 184.800 123.260 ;
    END
  END Tile_X0Y1_EE4BEG[5]
  PIN Tile_X0Y1_EE4BEG[6]
    DIRECTION OUTPUT ;
    USE SIGNAL ;
    ANTENNADIFFAREA 0.708600 ;
    PORT
      LAYER Metal3 ;
        RECT 184.400 124.540 184.800 124.940 ;
    END
  END Tile_X0Y1_EE4BEG[6]
  PIN Tile_X0Y1_EE4BEG[7]
    DIRECTION OUTPUT ;
    USE SIGNAL ;
    ANTENNADIFFAREA 0.708600 ;
    PORT
      LAYER Metal3 ;
        RECT 184.400 126.220 184.800 126.620 ;
    END
  END Tile_X0Y1_EE4BEG[7]
  PIN Tile_X0Y1_EE4BEG[8]
    DIRECTION OUTPUT ;
    USE SIGNAL ;
    ANTENNADIFFAREA 0.708600 ;
    PORT
      LAYER Metal3 ;
        RECT 184.400 127.900 184.800 128.300 ;
    END
  END Tile_X0Y1_EE4BEG[8]
  PIN Tile_X0Y1_EE4BEG[9]
    DIRECTION OUTPUT ;
    USE SIGNAL ;
    ANTENNADIFFAREA 0.708600 ;
    PORT
      LAYER Metal3 ;
        RECT 184.400 129.580 184.800 129.980 ;
    END
  END Tile_X0Y1_EE4BEG[9]
  PIN Tile_X0Y1_EE4END[0]
    DIRECTION INPUT ;
    USE SIGNAL ;
    ANTENNAGATEAREA 0.668200 ;
    PORT
      LAYER Metal3 ;
        RECT 0.000 114.460 0.400 114.860 ;
    END
  END Tile_X0Y1_EE4END[0]
  PIN Tile_X0Y1_EE4END[10]
    DIRECTION INPUT ;
    USE SIGNAL ;
    ANTENNAGATEAREA 0.789100 ;
    ANTENNADIFFAREA 2.015400 ;
    PORT
      LAYER Metal3 ;
        RECT 0.000 131.260 0.400 131.660 ;
    END
  END Tile_X0Y1_EE4END[10]
  PIN Tile_X0Y1_EE4END[11]
    DIRECTION INPUT ;
    USE SIGNAL ;
    ANTENNAGATEAREA 0.789100 ;
    ANTENNADIFFAREA 2.015400 ;
    PORT
      LAYER Metal3 ;
        RECT 0.000 132.940 0.400 133.340 ;
    END
  END Tile_X0Y1_EE4END[11]
  PIN Tile_X0Y1_EE4END[12]
    DIRECTION INPUT ;
    USE SIGNAL ;
    ANTENNAGATEAREA 0.789100 ;
    ANTENNADIFFAREA 2.015400 ;
    PORT
      LAYER Metal3 ;
        RECT 0.000 134.620 0.400 135.020 ;
    END
  END Tile_X0Y1_EE4END[12]
  PIN Tile_X0Y1_EE4END[13]
    DIRECTION INPUT ;
    USE SIGNAL ;
    ANTENNAGATEAREA 0.789100 ;
    ANTENNADIFFAREA 2.015400 ;
    PORT
      LAYER Metal3 ;
        RECT 0.000 136.300 0.400 136.700 ;
    END
  END Tile_X0Y1_EE4END[13]
  PIN Tile_X0Y1_EE4END[14]
    DIRECTION INPUT ;
    USE SIGNAL ;
    ANTENNAGATEAREA 0.180700 ;
    PORT
      LAYER Metal3 ;
        RECT 0.000 137.980 0.400 138.380 ;
    END
  END Tile_X0Y1_EE4END[14]
  PIN Tile_X0Y1_EE4END[15]
    DIRECTION INPUT ;
    USE SIGNAL ;
    ANTENNAGATEAREA 0.180700 ;
    PORT
      LAYER Metal3 ;
        RECT 0.000 139.660 0.400 140.060 ;
    END
  END Tile_X0Y1_EE4END[15]
  PIN Tile_X0Y1_EE4END[1]
    DIRECTION INPUT ;
    USE SIGNAL ;
    ANTENNAGATEAREA 0.639600 ;
    PORT
      LAYER Metal3 ;
        RECT 0.000 116.140 0.400 116.540 ;
    END
  END Tile_X0Y1_EE4END[1]
  PIN Tile_X0Y1_EE4END[2]
    DIRECTION INPUT ;
    USE SIGNAL ;
    ANTENNAGATEAREA 0.705400 ;
    PORT
      LAYER Metal3 ;
        RECT 0.000 117.820 0.400 118.220 ;
    END
  END Tile_X0Y1_EE4END[2]
  PIN Tile_X0Y1_EE4END[3]
    DIRECTION INPUT ;
    USE SIGNAL ;
    ANTENNAGATEAREA 0.492200 ;
    PORT
      LAYER Metal3 ;
        RECT 0.000 119.500 0.400 119.900 ;
    END
  END Tile_X0Y1_EE4END[3]
  PIN Tile_X0Y1_EE4END[4]
    DIRECTION INPUT ;
    USE SIGNAL ;
    ANTENNAGATEAREA 0.789100 ;
    ANTENNADIFFAREA 2.015400 ;
    PORT
      LAYER Metal3 ;
        RECT 0.000 121.180 0.400 121.580 ;
    END
  END Tile_X0Y1_EE4END[4]
  PIN Tile_X0Y1_EE4END[5]
    DIRECTION INPUT ;
    USE SIGNAL ;
    ANTENNAGATEAREA 0.789100 ;
    ANTENNADIFFAREA 2.015400 ;
    PORT
      LAYER Metal3 ;
        RECT 0.000 122.860 0.400 123.260 ;
    END
  END Tile_X0Y1_EE4END[5]
  PIN Tile_X0Y1_EE4END[6]
    DIRECTION INPUT ;
    USE SIGNAL ;
    ANTENNAGATEAREA 0.180700 ;
    PORT
      LAYER Metal3 ;
        RECT 0.000 124.540 0.400 124.940 ;
    END
  END Tile_X0Y1_EE4END[6]
  PIN Tile_X0Y1_EE4END[7]
    DIRECTION INPUT ;
    USE SIGNAL ;
    ANTENNAGATEAREA 0.789100 ;
    ANTENNADIFFAREA 2.015400 ;
    PORT
      LAYER Metal3 ;
        RECT 0.000 126.220 0.400 126.620 ;
    END
  END Tile_X0Y1_EE4END[7]
  PIN Tile_X0Y1_EE4END[8]
    DIRECTION INPUT ;
    USE SIGNAL ;
    ANTENNAGATEAREA 0.789100 ;
    ANTENNADIFFAREA 2.015400 ;
    PORT
      LAYER Metal3 ;
        RECT 0.000 127.900 0.400 128.300 ;
    END
  END Tile_X0Y1_EE4END[8]
  PIN Tile_X0Y1_EE4END[9]
    DIRECTION INPUT ;
    USE SIGNAL ;
    ANTENNAGATEAREA 0.789100 ;
    ANTENNADIFFAREA 2.015400 ;
    PORT
      LAYER Metal3 ;
        RECT 0.000 129.580 0.400 129.980 ;
    END
  END Tile_X0Y1_EE4END[9]
  PIN Tile_X0Y1_FrameData[0]
    DIRECTION INPUT ;
    USE SIGNAL ;
    ANTENNAGATEAREA 2.529800 ;
    PORT
      LAYER Metal3 ;
        RECT 0.000 161.500 0.400 161.900 ;
    END
  END Tile_X0Y1_FrameData[0]
  PIN Tile_X0Y1_FrameData[10]
    DIRECTION INPUT ;
    USE SIGNAL ;
    ANTENNAGATEAREA 2.529800 ;
    PORT
      LAYER Metal3 ;
        RECT 0.000 178.300 0.400 178.700 ;
    END
  END Tile_X0Y1_FrameData[10]
  PIN Tile_X0Y1_FrameData[11]
    DIRECTION INPUT ;
    USE SIGNAL ;
    ANTENNAGATEAREA 2.529800 ;
    PORT
      LAYER Metal3 ;
        RECT 0.000 179.980 0.400 180.380 ;
    END
  END Tile_X0Y1_FrameData[11]
  PIN Tile_X0Y1_FrameData[12]
    DIRECTION INPUT ;
    USE SIGNAL ;
    ANTENNAGATEAREA 2.529800 ;
    PORT
      LAYER Metal3 ;
        RECT 0.000 181.660 0.400 182.060 ;
    END
  END Tile_X0Y1_FrameData[12]
  PIN Tile_X0Y1_FrameData[13]
    DIRECTION INPUT ;
    USE SIGNAL ;
    ANTENNAGATEAREA 2.529800 ;
    PORT
      LAYER Metal3 ;
        RECT 0.000 183.340 0.400 183.740 ;
    END
  END Tile_X0Y1_FrameData[13]
  PIN Tile_X0Y1_FrameData[14]
    DIRECTION INPUT ;
    USE SIGNAL ;
    ANTENNAGATEAREA 2.529800 ;
    PORT
      LAYER Metal3 ;
        RECT 0.000 185.020 0.400 185.420 ;
    END
  END Tile_X0Y1_FrameData[14]
  PIN Tile_X0Y1_FrameData[15]
    DIRECTION INPUT ;
    USE SIGNAL ;
    ANTENNAGATEAREA 2.529800 ;
    PORT
      LAYER Metal3 ;
        RECT 0.000 186.700 0.400 187.100 ;
    END
  END Tile_X0Y1_FrameData[15]
  PIN Tile_X0Y1_FrameData[16]
    DIRECTION INPUT ;
    USE SIGNAL ;
    ANTENNAGATEAREA 2.529800 ;
    PORT
      LAYER Metal3 ;
        RECT 0.000 188.380 0.400 188.780 ;
    END
  END Tile_X0Y1_FrameData[16]
  PIN Tile_X0Y1_FrameData[17]
    DIRECTION INPUT ;
    USE SIGNAL ;
    ANTENNAGATEAREA 2.529800 ;
    PORT
      LAYER Metal3 ;
        RECT 0.000 190.060 0.400 190.460 ;
    END
  END Tile_X0Y1_FrameData[17]
  PIN Tile_X0Y1_FrameData[18]
    DIRECTION INPUT ;
    USE SIGNAL ;
    ANTENNAGATEAREA 2.529800 ;
    PORT
      LAYER Metal3 ;
        RECT 0.000 191.740 0.400 192.140 ;
    END
  END Tile_X0Y1_FrameData[18]
  PIN Tile_X0Y1_FrameData[19]
    DIRECTION INPUT ;
    USE SIGNAL ;
    ANTENNAGATEAREA 2.529800 ;
    PORT
      LAYER Metal3 ;
        RECT 0.000 193.420 0.400 193.820 ;
    END
  END Tile_X0Y1_FrameData[19]
  PIN Tile_X0Y1_FrameData[1]
    DIRECTION INPUT ;
    USE SIGNAL ;
    ANTENNAGATEAREA 2.529800 ;
    PORT
      LAYER Metal3 ;
        RECT 0.000 163.180 0.400 163.580 ;
    END
  END Tile_X0Y1_FrameData[1]
  PIN Tile_X0Y1_FrameData[20]
    DIRECTION INPUT ;
    USE SIGNAL ;
    ANTENNAGATEAREA 2.529800 ;
    PORT
      LAYER Metal3 ;
        RECT 0.000 195.100 0.400 195.500 ;
    END
  END Tile_X0Y1_FrameData[20]
  PIN Tile_X0Y1_FrameData[21]
    DIRECTION INPUT ;
    USE SIGNAL ;
    ANTENNAGATEAREA 2.529800 ;
    PORT
      LAYER Metal3 ;
        RECT 0.000 196.780 0.400 197.180 ;
    END
  END Tile_X0Y1_FrameData[21]
  PIN Tile_X0Y1_FrameData[22]
    DIRECTION INPUT ;
    USE SIGNAL ;
    ANTENNAGATEAREA 2.529800 ;
    PORT
      LAYER Metal3 ;
        RECT 0.000 198.460 0.400 198.860 ;
    END
  END Tile_X0Y1_FrameData[22]
  PIN Tile_X0Y1_FrameData[23]
    DIRECTION INPUT ;
    USE SIGNAL ;
    ANTENNAGATEAREA 2.529800 ;
    PORT
      LAYER Metal3 ;
        RECT 0.000 200.140 0.400 200.540 ;
    END
  END Tile_X0Y1_FrameData[23]
  PIN Tile_X0Y1_FrameData[24]
    DIRECTION INPUT ;
    USE SIGNAL ;
    ANTENNAGATEAREA 2.529800 ;
    PORT
      LAYER Metal3 ;
        RECT 0.000 201.820 0.400 202.220 ;
    END
  END Tile_X0Y1_FrameData[24]
  PIN Tile_X0Y1_FrameData[25]
    DIRECTION INPUT ;
    USE SIGNAL ;
    ANTENNAGATEAREA 2.529800 ;
    PORT
      LAYER Metal3 ;
        RECT 0.000 203.500 0.400 203.900 ;
    END
  END Tile_X0Y1_FrameData[25]
  PIN Tile_X0Y1_FrameData[26]
    DIRECTION INPUT ;
    USE SIGNAL ;
    ANTENNAGATEAREA 2.529800 ;
    PORT
      LAYER Metal3 ;
        RECT 0.000 205.180 0.400 205.580 ;
    END
  END Tile_X0Y1_FrameData[26]
  PIN Tile_X0Y1_FrameData[27]
    DIRECTION INPUT ;
    USE SIGNAL ;
    ANTENNAGATEAREA 2.529800 ;
    PORT
      LAYER Metal3 ;
        RECT 0.000 206.860 0.400 207.260 ;
    END
  END Tile_X0Y1_FrameData[27]
  PIN Tile_X0Y1_FrameData[28]
    DIRECTION INPUT ;
    USE SIGNAL ;
    ANTENNAGATEAREA 2.529800 ;
    PORT
      LAYER Metal3 ;
        RECT 0.000 208.540 0.400 208.940 ;
    END
  END Tile_X0Y1_FrameData[28]
  PIN Tile_X0Y1_FrameData[29]
    DIRECTION INPUT ;
    USE SIGNAL ;
    ANTENNAGATEAREA 2.529800 ;
    PORT
      LAYER Metal3 ;
        RECT 0.000 210.220 0.400 210.620 ;
    END
  END Tile_X0Y1_FrameData[29]
  PIN Tile_X0Y1_FrameData[2]
    DIRECTION INPUT ;
    USE SIGNAL ;
    ANTENNAGATEAREA 2.529800 ;
    PORT
      LAYER Metal3 ;
        RECT 0.000 164.860 0.400 165.260 ;
    END
  END Tile_X0Y1_FrameData[2]
  PIN Tile_X0Y1_FrameData[30]
    DIRECTION INPUT ;
    USE SIGNAL ;
    ANTENNAGATEAREA 2.529800 ;
    PORT
      LAYER Metal3 ;
        RECT 0.000 211.900 0.400 212.300 ;
    END
  END Tile_X0Y1_FrameData[30]
  PIN Tile_X0Y1_FrameData[31]
    DIRECTION INPUT ;
    USE SIGNAL ;
    ANTENNAGATEAREA 2.529800 ;
    PORT
      LAYER Metal3 ;
        RECT 0.000 213.580 0.400 213.980 ;
    END
  END Tile_X0Y1_FrameData[31]
  PIN Tile_X0Y1_FrameData[3]
    DIRECTION INPUT ;
    USE SIGNAL ;
    ANTENNAGATEAREA 2.529800 ;
    PORT
      LAYER Metal3 ;
        RECT 0.000 166.540 0.400 166.940 ;
    END
  END Tile_X0Y1_FrameData[3]
  PIN Tile_X0Y1_FrameData[4]
    DIRECTION INPUT ;
    USE SIGNAL ;
    ANTENNAGATEAREA 2.529800 ;
    PORT
      LAYER Metal3 ;
        RECT 0.000 168.220 0.400 168.620 ;
    END
  END Tile_X0Y1_FrameData[4]
  PIN Tile_X0Y1_FrameData[5]
    DIRECTION INPUT ;
    USE SIGNAL ;
    ANTENNAGATEAREA 2.529800 ;
    PORT
      LAYER Metal3 ;
        RECT 0.000 169.900 0.400 170.300 ;
    END
  END Tile_X0Y1_FrameData[5]
  PIN Tile_X0Y1_FrameData[6]
    DIRECTION INPUT ;
    USE SIGNAL ;
    ANTENNAGATEAREA 2.529800 ;
    PORT
      LAYER Metal3 ;
        RECT 0.000 171.580 0.400 171.980 ;
    END
  END Tile_X0Y1_FrameData[6]
  PIN Tile_X0Y1_FrameData[7]
    DIRECTION INPUT ;
    USE SIGNAL ;
    ANTENNAGATEAREA 2.529800 ;
    PORT
      LAYER Metal3 ;
        RECT 0.000 173.260 0.400 173.660 ;
    END
  END Tile_X0Y1_FrameData[7]
  PIN Tile_X0Y1_FrameData[8]
    DIRECTION INPUT ;
    USE SIGNAL ;
    ANTENNAGATEAREA 2.529800 ;
    PORT
      LAYER Metal3 ;
        RECT 0.000 174.940 0.400 175.340 ;
    END
  END Tile_X0Y1_FrameData[8]
  PIN Tile_X0Y1_FrameData[9]
    DIRECTION INPUT ;
    USE SIGNAL ;
    ANTENNAGATEAREA 2.529800 ;
    PORT
      LAYER Metal3 ;
        RECT 0.000 176.620 0.400 177.020 ;
    END
  END Tile_X0Y1_FrameData[9]
  PIN Tile_X0Y1_FrameData_O[0]
    DIRECTION OUTPUT ;
    USE SIGNAL ;
    ANTENNADIFFAREA 0.708600 ;
    PORT
      LAYER Metal3 ;
        RECT 184.400 161.500 184.800 161.900 ;
    END
  END Tile_X0Y1_FrameData_O[0]
  PIN Tile_X0Y1_FrameData_O[10]
    DIRECTION OUTPUT ;
    USE SIGNAL ;
    ANTENNADIFFAREA 0.708600 ;
    PORT
      LAYER Metal3 ;
        RECT 184.400 178.300 184.800 178.700 ;
    END
  END Tile_X0Y1_FrameData_O[10]
  PIN Tile_X0Y1_FrameData_O[11]
    DIRECTION OUTPUT ;
    USE SIGNAL ;
    ANTENNADIFFAREA 0.708600 ;
    PORT
      LAYER Metal3 ;
        RECT 184.400 179.980 184.800 180.380 ;
    END
  END Tile_X0Y1_FrameData_O[11]
  PIN Tile_X0Y1_FrameData_O[12]
    DIRECTION OUTPUT ;
    USE SIGNAL ;
    ANTENNADIFFAREA 0.708600 ;
    PORT
      LAYER Metal3 ;
        RECT 184.400 181.660 184.800 182.060 ;
    END
  END Tile_X0Y1_FrameData_O[12]
  PIN Tile_X0Y1_FrameData_O[13]
    DIRECTION OUTPUT ;
    USE SIGNAL ;
    ANTENNADIFFAREA 0.708600 ;
    PORT
      LAYER Metal3 ;
        RECT 184.400 183.340 184.800 183.740 ;
    END
  END Tile_X0Y1_FrameData_O[13]
  PIN Tile_X0Y1_FrameData_O[14]
    DIRECTION OUTPUT ;
    USE SIGNAL ;
    ANTENNADIFFAREA 0.708600 ;
    PORT
      LAYER Metal3 ;
        RECT 184.400 185.020 184.800 185.420 ;
    END
  END Tile_X0Y1_FrameData_O[14]
  PIN Tile_X0Y1_FrameData_O[15]
    DIRECTION OUTPUT ;
    USE SIGNAL ;
    ANTENNADIFFAREA 0.708600 ;
    PORT
      LAYER Metal3 ;
        RECT 184.400 186.700 184.800 187.100 ;
    END
  END Tile_X0Y1_FrameData_O[15]
  PIN Tile_X0Y1_FrameData_O[16]
    DIRECTION OUTPUT ;
    USE SIGNAL ;
    ANTENNADIFFAREA 0.708600 ;
    PORT
      LAYER Metal3 ;
        RECT 184.400 188.380 184.800 188.780 ;
    END
  END Tile_X0Y1_FrameData_O[16]
  PIN Tile_X0Y1_FrameData_O[17]
    DIRECTION OUTPUT ;
    USE SIGNAL ;
    ANTENNADIFFAREA 0.708600 ;
    PORT
      LAYER Metal3 ;
        RECT 184.400 190.060 184.800 190.460 ;
    END
  END Tile_X0Y1_FrameData_O[17]
  PIN Tile_X0Y1_FrameData_O[18]
    DIRECTION OUTPUT ;
    USE SIGNAL ;
    ANTENNADIFFAREA 0.708600 ;
    PORT
      LAYER Metal3 ;
        RECT 184.400 191.740 184.800 192.140 ;
    END
  END Tile_X0Y1_FrameData_O[18]
  PIN Tile_X0Y1_FrameData_O[19]
    DIRECTION OUTPUT ;
    USE SIGNAL ;
    ANTENNADIFFAREA 0.708600 ;
    PORT
      LAYER Metal3 ;
        RECT 184.400 193.420 184.800 193.820 ;
    END
  END Tile_X0Y1_FrameData_O[19]
  PIN Tile_X0Y1_FrameData_O[1]
    DIRECTION OUTPUT ;
    USE SIGNAL ;
    ANTENNADIFFAREA 0.708600 ;
    PORT
      LAYER Metal3 ;
        RECT 184.400 163.180 184.800 163.580 ;
    END
  END Tile_X0Y1_FrameData_O[1]
  PIN Tile_X0Y1_FrameData_O[20]
    DIRECTION OUTPUT ;
    USE SIGNAL ;
    ANTENNADIFFAREA 0.708600 ;
    PORT
      LAYER Metal3 ;
        RECT 184.400 195.100 184.800 195.500 ;
    END
  END Tile_X0Y1_FrameData_O[20]
  PIN Tile_X0Y1_FrameData_O[21]
    DIRECTION OUTPUT ;
    USE SIGNAL ;
    ANTENNADIFFAREA 0.708600 ;
    PORT
      LAYER Metal3 ;
        RECT 184.400 196.780 184.800 197.180 ;
    END
  END Tile_X0Y1_FrameData_O[21]
  PIN Tile_X0Y1_FrameData_O[22]
    DIRECTION OUTPUT ;
    USE SIGNAL ;
    ANTENNADIFFAREA 0.708600 ;
    PORT
      LAYER Metal3 ;
        RECT 184.400 198.460 184.800 198.860 ;
    END
  END Tile_X0Y1_FrameData_O[22]
  PIN Tile_X0Y1_FrameData_O[23]
    DIRECTION OUTPUT ;
    USE SIGNAL ;
    ANTENNADIFFAREA 0.708600 ;
    PORT
      LAYER Metal3 ;
        RECT 184.400 200.140 184.800 200.540 ;
    END
  END Tile_X0Y1_FrameData_O[23]
  PIN Tile_X0Y1_FrameData_O[24]
    DIRECTION OUTPUT ;
    USE SIGNAL ;
    ANTENNADIFFAREA 0.708600 ;
    PORT
      LAYER Metal3 ;
        RECT 184.400 201.820 184.800 202.220 ;
    END
  END Tile_X0Y1_FrameData_O[24]
  PIN Tile_X0Y1_FrameData_O[25]
    DIRECTION OUTPUT ;
    USE SIGNAL ;
    ANTENNADIFFAREA 0.708600 ;
    PORT
      LAYER Metal3 ;
        RECT 184.400 203.500 184.800 203.900 ;
    END
  END Tile_X0Y1_FrameData_O[25]
  PIN Tile_X0Y1_FrameData_O[26]
    DIRECTION OUTPUT ;
    USE SIGNAL ;
    ANTENNADIFFAREA 0.708600 ;
    PORT
      LAYER Metal3 ;
        RECT 184.400 205.180 184.800 205.580 ;
    END
  END Tile_X0Y1_FrameData_O[26]
  PIN Tile_X0Y1_FrameData_O[27]
    DIRECTION OUTPUT ;
    USE SIGNAL ;
    ANTENNADIFFAREA 0.708600 ;
    PORT
      LAYER Metal3 ;
        RECT 184.400 206.860 184.800 207.260 ;
    END
  END Tile_X0Y1_FrameData_O[27]
  PIN Tile_X0Y1_FrameData_O[28]
    DIRECTION OUTPUT ;
    USE SIGNAL ;
    ANTENNADIFFAREA 0.708600 ;
    PORT
      LAYER Metal3 ;
        RECT 184.400 208.540 184.800 208.940 ;
    END
  END Tile_X0Y1_FrameData_O[28]
  PIN Tile_X0Y1_FrameData_O[29]
    DIRECTION OUTPUT ;
    USE SIGNAL ;
    ANTENNADIFFAREA 0.708600 ;
    PORT
      LAYER Metal3 ;
        RECT 184.400 210.220 184.800 210.620 ;
    END
  END Tile_X0Y1_FrameData_O[29]
  PIN Tile_X0Y1_FrameData_O[2]
    DIRECTION OUTPUT ;
    USE SIGNAL ;
    ANTENNADIFFAREA 0.708600 ;
    PORT
      LAYER Metal3 ;
        RECT 184.400 164.860 184.800 165.260 ;
    END
  END Tile_X0Y1_FrameData_O[2]
  PIN Tile_X0Y1_FrameData_O[30]
    DIRECTION OUTPUT ;
    USE SIGNAL ;
    ANTENNADIFFAREA 0.708600 ;
    PORT
      LAYER Metal3 ;
        RECT 184.400 211.900 184.800 212.300 ;
    END
  END Tile_X0Y1_FrameData_O[30]
  PIN Tile_X0Y1_FrameData_O[31]
    DIRECTION OUTPUT ;
    USE SIGNAL ;
    ANTENNADIFFAREA 0.708600 ;
    PORT
      LAYER Metal3 ;
        RECT 184.400 213.580 184.800 213.980 ;
    END
  END Tile_X0Y1_FrameData_O[31]
  PIN Tile_X0Y1_FrameData_O[3]
    DIRECTION OUTPUT ;
    USE SIGNAL ;
    ANTENNADIFFAREA 0.708600 ;
    PORT
      LAYER Metal3 ;
        RECT 184.400 166.540 184.800 166.940 ;
    END
  END Tile_X0Y1_FrameData_O[3]
  PIN Tile_X0Y1_FrameData_O[4]
    DIRECTION OUTPUT ;
    USE SIGNAL ;
    ANTENNADIFFAREA 0.708600 ;
    PORT
      LAYER Metal3 ;
        RECT 184.400 168.220 184.800 168.620 ;
    END
  END Tile_X0Y1_FrameData_O[4]
  PIN Tile_X0Y1_FrameData_O[5]
    DIRECTION OUTPUT ;
    USE SIGNAL ;
    ANTENNADIFFAREA 0.708600 ;
    PORT
      LAYER Metal3 ;
        RECT 184.400 169.900 184.800 170.300 ;
    END
  END Tile_X0Y1_FrameData_O[5]
  PIN Tile_X0Y1_FrameData_O[6]
    DIRECTION OUTPUT ;
    USE SIGNAL ;
    ANTENNADIFFAREA 0.708600 ;
    PORT
      LAYER Metal3 ;
        RECT 184.400 171.580 184.800 171.980 ;
    END
  END Tile_X0Y1_FrameData_O[6]
  PIN Tile_X0Y1_FrameData_O[7]
    DIRECTION OUTPUT ;
    USE SIGNAL ;
    ANTENNADIFFAREA 0.708600 ;
    PORT
      LAYER Metal3 ;
        RECT 184.400 173.260 184.800 173.660 ;
    END
  END Tile_X0Y1_FrameData_O[7]
  PIN Tile_X0Y1_FrameData_O[8]
    DIRECTION OUTPUT ;
    USE SIGNAL ;
    ANTENNADIFFAREA 0.708600 ;
    PORT
      LAYER Metal3 ;
        RECT 184.400 174.940 184.800 175.340 ;
    END
  END Tile_X0Y1_FrameData_O[8]
  PIN Tile_X0Y1_FrameData_O[9]
    DIRECTION OUTPUT ;
    USE SIGNAL ;
    ANTENNADIFFAREA 0.708600 ;
    PORT
      LAYER Metal3 ;
        RECT 184.400 176.620 184.800 177.020 ;
    END
  END Tile_X0Y1_FrameData_O[9]
  PIN Tile_X0Y1_FrameStrobe[0]
    DIRECTION INPUT ;
    USE SIGNAL ;
    ANTENNAGATEAREA 13.326300 ;
    PORT
      LAYER Metal2 ;
        RECT 132.760 0.000 133.160 0.400 ;
    END
  END Tile_X0Y1_FrameStrobe[0]
  PIN Tile_X0Y1_FrameStrobe[10]
    DIRECTION INPUT ;
    USE SIGNAL ;
    ANTENNAGATEAREA 13.326300 ;
    PORT
      LAYER Metal2 ;
        RECT 142.360 0.000 142.760 0.400 ;
    END
  END Tile_X0Y1_FrameStrobe[10]
  PIN Tile_X0Y1_FrameStrobe[11]
    DIRECTION INPUT ;
    USE SIGNAL ;
    ANTENNAGATEAREA 13.326300 ;
    PORT
      LAYER Metal2 ;
        RECT 143.320 0.000 143.720 0.400 ;
    END
  END Tile_X0Y1_FrameStrobe[11]
  PIN Tile_X0Y1_FrameStrobe[12]
    DIRECTION INPUT ;
    USE SIGNAL ;
    ANTENNAGATEAREA 11.272300 ;
    PORT
      LAYER Metal2 ;
        RECT 144.280 0.000 144.680 0.400 ;
    END
  END Tile_X0Y1_FrameStrobe[12]
  PIN Tile_X0Y1_FrameStrobe[13]
    DIRECTION INPUT ;
    USE SIGNAL ;
    ANTENNAGATEAREA 0.789100 ;
    ANTENNADIFFAREA 2.015400 ;
    PORT
      LAYER Metal2 ;
        RECT 145.240 0.000 145.640 0.400 ;
    END
  END Tile_X0Y1_FrameStrobe[13]
  PIN Tile_X0Y1_FrameStrobe[14]
    DIRECTION INPUT ;
    USE SIGNAL ;
    ANTENNAGATEAREA 0.180700 ;
    PORT
      LAYER Metal2 ;
        RECT 146.200 0.000 146.600 0.400 ;
    END
  END Tile_X0Y1_FrameStrobe[14]
  PIN Tile_X0Y1_FrameStrobe[15]
    DIRECTION INPUT ;
    USE SIGNAL ;
    ANTENNAGATEAREA 0.789100 ;
    ANTENNADIFFAREA 2.015400 ;
    PORT
      LAYER Metal2 ;
        RECT 147.160 0.000 147.560 0.400 ;
    END
  END Tile_X0Y1_FrameStrobe[15]
  PIN Tile_X0Y1_FrameStrobe[16]
    DIRECTION INPUT ;
    USE SIGNAL ;
    ANTENNAGATEAREA 0.180700 ;
    PORT
      LAYER Metal2 ;
        RECT 148.120 0.000 148.520 0.400 ;
    END
  END Tile_X0Y1_FrameStrobe[16]
  PIN Tile_X0Y1_FrameStrobe[17]
    DIRECTION INPUT ;
    USE SIGNAL ;
    ANTENNAGATEAREA 0.789100 ;
    ANTENNADIFFAREA 2.015400 ;
    PORT
      LAYER Metal2 ;
        RECT 149.080 0.000 149.480 0.400 ;
    END
  END Tile_X0Y1_FrameStrobe[17]
  PIN Tile_X0Y1_FrameStrobe[18]
    DIRECTION INPUT ;
    USE SIGNAL ;
    ANTENNAGATEAREA 0.789100 ;
    ANTENNADIFFAREA 2.015400 ;
    PORT
      LAYER Metal2 ;
        RECT 150.040 0.000 150.440 0.400 ;
    END
  END Tile_X0Y1_FrameStrobe[18]
  PIN Tile_X0Y1_FrameStrobe[19]
    DIRECTION INPUT ;
    USE SIGNAL ;
    ANTENNAGATEAREA 0.789100 ;
    ANTENNADIFFAREA 2.015400 ;
    PORT
      LAYER Metal2 ;
        RECT 151.000 0.000 151.400 0.400 ;
    END
  END Tile_X0Y1_FrameStrobe[19]
  PIN Tile_X0Y1_FrameStrobe[1]
    DIRECTION INPUT ;
    USE SIGNAL ;
    ANTENNAGATEAREA 13.326300 ;
    PORT
      LAYER Metal2 ;
        RECT 133.720 0.000 134.120 0.400 ;
    END
  END Tile_X0Y1_FrameStrobe[1]
  PIN Tile_X0Y1_FrameStrobe[2]
    DIRECTION INPUT ;
    USE SIGNAL ;
    ANTENNAGATEAREA 13.326300 ;
    PORT
      LAYER Metal2 ;
        RECT 134.680 0.000 135.080 0.400 ;
    END
  END Tile_X0Y1_FrameStrobe[2]
  PIN Tile_X0Y1_FrameStrobe[3]
    DIRECTION INPUT ;
    USE SIGNAL ;
    ANTENNAGATEAREA 13.326300 ;
    PORT
      LAYER Metal2 ;
        RECT 135.640 0.000 136.040 0.400 ;
    END
  END Tile_X0Y1_FrameStrobe[3]
  PIN Tile_X0Y1_FrameStrobe[4]
    DIRECTION INPUT ;
    USE SIGNAL ;
    ANTENNAGATEAREA 13.326300 ;
    PORT
      LAYER Metal2 ;
        RECT 136.600 0.000 137.000 0.400 ;
    END
  END Tile_X0Y1_FrameStrobe[4]
  PIN Tile_X0Y1_FrameStrobe[5]
    DIRECTION INPUT ;
    USE SIGNAL ;
    ANTENNAGATEAREA 13.326300 ;
    PORT
      LAYER Metal2 ;
        RECT 137.560 0.000 137.960 0.400 ;
    END
  END Tile_X0Y1_FrameStrobe[5]
  PIN Tile_X0Y1_FrameStrobe[6]
    DIRECTION INPUT ;
    USE SIGNAL ;
    ANTENNAGATEAREA 13.326300 ;
    PORT
      LAYER Metal2 ;
        RECT 138.520 0.000 138.920 0.400 ;
    END
  END Tile_X0Y1_FrameStrobe[6]
  PIN Tile_X0Y1_FrameStrobe[7]
    DIRECTION INPUT ;
    USE SIGNAL ;
    ANTENNAGATEAREA 13.326300 ;
    PORT
      LAYER Metal2 ;
        RECT 139.480 0.000 139.880 0.400 ;
    END
  END Tile_X0Y1_FrameStrobe[7]
  PIN Tile_X0Y1_FrameStrobe[8]
    DIRECTION INPUT ;
    USE SIGNAL ;
    ANTENNAGATEAREA 13.326300 ;
    PORT
      LAYER Metal2 ;
        RECT 140.440 0.000 140.840 0.400 ;
    END
  END Tile_X0Y1_FrameStrobe[8]
  PIN Tile_X0Y1_FrameStrobe[9]
    DIRECTION INPUT ;
    USE SIGNAL ;
    ANTENNAGATEAREA 13.326300 ;
    PORT
      LAYER Metal2 ;
        RECT 141.400 0.000 141.800 0.400 ;
    END
  END Tile_X0Y1_FrameStrobe[9]
  PIN Tile_X0Y1_N1END[0]
    DIRECTION INPUT ;
    USE SIGNAL ;
    ANTENNAGATEAREA 2.099500 ;
    PORT
      LAYER Metal2 ;
        RECT 31.960 0.000 32.360 0.400 ;
    END
  END Tile_X0Y1_N1END[0]
  PIN Tile_X0Y1_N1END[1]
    DIRECTION INPUT ;
    USE SIGNAL ;
    ANTENNAGATEAREA 2.132000 ;
    PORT
      LAYER Metal2 ;
        RECT 32.920 0.000 33.320 0.400 ;
    END
  END Tile_X0Y1_N1END[1]
  PIN Tile_X0Y1_N1END[2]
    DIRECTION INPUT ;
    USE SIGNAL ;
    ANTENNAGATEAREA 2.145000 ;
    PORT
      LAYER Metal2 ;
        RECT 33.880 0.000 34.280 0.400 ;
    END
  END Tile_X0Y1_N1END[2]
  PIN Tile_X0Y1_N1END[3]
    DIRECTION INPUT ;
    USE SIGNAL ;
    ANTENNAGATEAREA 2.132000 ;
    PORT
      LAYER Metal2 ;
        RECT 34.840 0.000 35.240 0.400 ;
    END
  END Tile_X0Y1_N1END[3]
  PIN Tile_X0Y1_N2END[0]
    DIRECTION INPUT ;
    USE SIGNAL ;
    ANTENNAGATEAREA 1.492400 ;
    PORT
      LAYER Metal2 ;
        RECT 43.480 0.000 43.880 0.400 ;
    END
  END Tile_X0Y1_N2END[0]
  PIN Tile_X0Y1_N2END[1]
    DIRECTION INPUT ;
    USE SIGNAL ;
    ANTENNAGATEAREA 1.066000 ;
    PORT
      LAYER Metal2 ;
        RECT 44.440 0.000 44.840 0.400 ;
    END
  END Tile_X0Y1_N2END[1]
  PIN Tile_X0Y1_N2END[2]
    DIRECTION INPUT ;
    USE SIGNAL ;
    ANTENNAGATEAREA 1.094600 ;
    PORT
      LAYER Metal2 ;
        RECT 45.400 0.000 45.800 0.400 ;
    END
  END Tile_X0Y1_N2END[2]
  PIN Tile_X0Y1_N2END[3]
    DIRECTION INPUT ;
    USE SIGNAL ;
    ANTENNAGATEAREA 1.279200 ;
    PORT
      LAYER Metal2 ;
        RECT 46.360 0.000 46.760 0.400 ;
    END
  END Tile_X0Y1_N2END[3]
  PIN Tile_X0Y1_N2END[4]
    DIRECTION INPUT ;
    USE SIGNAL ;
    ANTENNAGATEAREA 1.305200 ;
    PORT
      LAYER Metal2 ;
        RECT 47.320 0.000 47.720 0.400 ;
    END
  END Tile_X0Y1_N2END[4]
  PIN Tile_X0Y1_N2END[5]
    DIRECTION INPUT ;
    USE SIGNAL ;
    ANTENNAGATEAREA 1.066000 ;
    PORT
      LAYER Metal2 ;
        RECT 48.280 0.000 48.680 0.400 ;
    END
  END Tile_X0Y1_N2END[5]
  PIN Tile_X0Y1_N2END[6]
    DIRECTION INPUT ;
    USE SIGNAL ;
    ANTENNAGATEAREA 1.066000 ;
    PORT
      LAYER Metal2 ;
        RECT 49.240 0.000 49.640 0.400 ;
    END
  END Tile_X0Y1_N2END[6]
  PIN Tile_X0Y1_N2END[7]
    DIRECTION INPUT ;
    USE SIGNAL ;
    ANTENNAGATEAREA 1.279200 ;
    PORT
      LAYER Metal2 ;
        RECT 50.200 0.000 50.600 0.400 ;
    END
  END Tile_X0Y1_N2END[7]
  PIN Tile_X0Y1_N2MID[0]
    DIRECTION INPUT ;
    USE SIGNAL ;
    ANTENNAGATEAREA 1.848600 ;
    PORT
      LAYER Metal2 ;
        RECT 35.800 0.000 36.200 0.400 ;
    END
  END Tile_X0Y1_N2MID[0]
  PIN Tile_X0Y1_N2MID[1]
    DIRECTION INPUT ;
    USE SIGNAL ;
    ANTENNAGATEAREA 2.140900 ;
    PORT
      LAYER Metal2 ;
        RECT 36.760 0.000 37.160 0.400 ;
    END
  END Tile_X0Y1_N2MID[1]
  PIN Tile_X0Y1_N2MID[2]
    DIRECTION INPUT ;
    USE SIGNAL ;
    ANTENNAGATEAREA 1.804400 ;
    PORT
      LAYER Metal2 ;
        RECT 37.720 0.000 38.120 0.400 ;
    END
  END Tile_X0Y1_N2MID[2]
  PIN Tile_X0Y1_N2MID[3]
    DIRECTION INPUT ;
    USE SIGNAL ;
    ANTENNAGATEAREA 1.734200 ;
    PORT
      LAYER Metal2 ;
        RECT 38.680 0.000 39.080 0.400 ;
    END
  END Tile_X0Y1_N2MID[3]
  PIN Tile_X0Y1_N2MID[4]
    DIRECTION INPUT ;
    USE SIGNAL ;
    ANTENNAGATEAREA 1.521000 ;
    PORT
      LAYER Metal2 ;
        RECT 39.640 0.000 40.040 0.400 ;
    END
  END Tile_X0Y1_N2MID[4]
  PIN Tile_X0Y1_N2MID[5]
    DIRECTION INPUT ;
    USE SIGNAL ;
    ANTENNAGATEAREA 2.033200 ;
    PORT
      LAYER Metal2 ;
        RECT 40.600 0.000 41.000 0.400 ;
    END
  END Tile_X0Y1_N2MID[5]
  PIN Tile_X0Y1_N2MID[6]
    DIRECTION INPUT ;
    USE SIGNAL ;
    ANTENNAGATEAREA 2.013200 ;
    PORT
      LAYER Metal2 ;
        RECT 41.560 0.000 41.960 0.400 ;
    END
  END Tile_X0Y1_N2MID[6]
  PIN Tile_X0Y1_N2MID[7]
    DIRECTION INPUT ;
    USE SIGNAL ;
    ANTENNAGATEAREA 2.443800 ;
    PORT
      LAYER Metal2 ;
        RECT 42.520 0.000 42.920 0.400 ;
    END
  END Tile_X0Y1_N2MID[7]
  PIN Tile_X0Y1_N4END[0]
    DIRECTION INPUT ;
    USE SIGNAL ;
    ANTENNAGATEAREA 1.079800 ;
    PORT
      LAYER Metal2 ;
        RECT 51.160 0.000 51.560 0.400 ;
    END
  END Tile_X0Y1_N4END[0]
  PIN Tile_X0Y1_N4END[10]
    DIRECTION INPUT ;
    USE SIGNAL ;
    ANTENNAGATEAREA 0.789100 ;
    ANTENNADIFFAREA 2.015400 ;
    PORT
      LAYER Metal2 ;
        RECT 60.760 0.000 61.160 0.400 ;
    END
  END Tile_X0Y1_N4END[10]
  PIN Tile_X0Y1_N4END[11]
    DIRECTION INPUT ;
    USE SIGNAL ;
    ANTENNAGATEAREA 2.005900 ;
    ANTENNADIFFAREA 6.046200 ;
    PORT
      LAYER Metal2 ;
        RECT 61.720 0.000 62.120 0.400 ;
    END
  END Tile_X0Y1_N4END[11]
  PIN Tile_X0Y1_N4END[12]
    DIRECTION INPUT ;
    USE SIGNAL ;
    ANTENNAGATEAREA 2.005900 ;
    ANTENNADIFFAREA 6.046200 ;
    PORT
      LAYER Metal2 ;
        RECT 62.680 0.000 63.080 0.400 ;
    END
  END Tile_X0Y1_N4END[12]
  PIN Tile_X0Y1_N4END[13]
    DIRECTION INPUT ;
    USE SIGNAL ;
    ANTENNAGATEAREA 0.789100 ;
    ANTENNADIFFAREA 2.015400 ;
    PORT
      LAYER Metal2 ;
        RECT 63.640 0.000 64.040 0.400 ;
    END
  END Tile_X0Y1_N4END[13]
  PIN Tile_X0Y1_N4END[14]
    DIRECTION INPUT ;
    USE SIGNAL ;
    ANTENNAGATEAREA 2.005900 ;
    ANTENNADIFFAREA 6.046200 ;
    PORT
      LAYER Metal2 ;
        RECT 64.600 0.000 65.000 0.400 ;
    END
  END Tile_X0Y1_N4END[14]
  PIN Tile_X0Y1_N4END[15]
    DIRECTION INPUT ;
    USE SIGNAL ;
    ANTENNAGATEAREA 0.789100 ;
    ANTENNADIFFAREA 2.015400 ;
    PORT
      LAYER Metal2 ;
        RECT 65.560 0.000 65.960 0.400 ;
    END
  END Tile_X0Y1_N4END[15]
  PIN Tile_X0Y1_N4END[1]
    DIRECTION INPUT ;
    USE SIGNAL ;
    ANTENNAGATEAREA 1.066000 ;
    PORT
      LAYER Metal2 ;
        RECT 52.120 0.000 52.520 0.400 ;
    END
  END Tile_X0Y1_N4END[1]
  PIN Tile_X0Y1_N4END[2]
    DIRECTION INPUT ;
    USE SIGNAL ;
    ANTENNAGATEAREA 1.033500 ;
    PORT
      LAYER Metal2 ;
        RECT 53.080 0.000 53.480 0.400 ;
    END
  END Tile_X0Y1_N4END[2]
  PIN Tile_X0Y1_N4END[3]
    DIRECTION INPUT ;
    USE SIGNAL ;
    ANTENNAGATEAREA 1.001000 ;
    PORT
      LAYER Metal2 ;
        RECT 54.040 0.000 54.440 0.400 ;
    END
  END Tile_X0Y1_N4END[3]
  PIN Tile_X0Y1_N4END[4]
    DIRECTION INPUT ;
    USE SIGNAL ;
    ANTENNAGATEAREA 1.001000 ;
    PORT
      LAYER Metal2 ;
        RECT 55.000 0.000 55.400 0.400 ;
    END
  END Tile_X0Y1_N4END[4]
  PIN Tile_X0Y1_N4END[5]
    DIRECTION INPUT ;
    USE SIGNAL ;
    ANTENNAGATEAREA 1.075100 ;
    PORT
      LAYER Metal2 ;
        RECT 55.960 0.000 56.360 0.400 ;
    END
  END Tile_X0Y1_N4END[5]
  PIN Tile_X0Y1_N4END[6]
    DIRECTION INPUT ;
    USE SIGNAL ;
    ANTENNAGATEAREA 1.001000 ;
    PORT
      LAYER Metal2 ;
        RECT 56.920 0.000 57.320 0.400 ;
    END
  END Tile_X0Y1_N4END[6]
  PIN Tile_X0Y1_N4END[7]
    DIRECTION INPUT ;
    USE SIGNAL ;
    ANTENNAGATEAREA 1.014000 ;
    PORT
      LAYER Metal2 ;
        RECT 57.880 0.000 58.280 0.400 ;
    END
  END Tile_X0Y1_N4END[7]
  PIN Tile_X0Y1_N4END[8]
    DIRECTION INPUT ;
    USE SIGNAL ;
    ANTENNAGATEAREA 0.789100 ;
    ANTENNADIFFAREA 2.015400 ;
    PORT
      LAYER Metal2 ;
        RECT 58.840 0.000 59.240 0.400 ;
    END
  END Tile_X0Y1_N4END[8]
  PIN Tile_X0Y1_N4END[9]
    DIRECTION INPUT ;
    USE SIGNAL ;
    ANTENNAGATEAREA 2.005900 ;
    ANTENNADIFFAREA 6.046200 ;
    PORT
      LAYER Metal2 ;
        RECT 59.800 0.000 60.200 0.400 ;
    END
  END Tile_X0Y1_N4END[9]
  PIN Tile_X0Y1_NN4END[0]
    DIRECTION INPUT ;
    USE SIGNAL ;
    ANTENNAGATEAREA 0.426400 ;
    PORT
      LAYER Metal2 ;
        RECT 66.520 0.000 66.920 0.400 ;
    END
  END Tile_X0Y1_NN4END[0]
  PIN Tile_X0Y1_NN4END[10]
    DIRECTION INPUT ;
    USE SIGNAL ;
    ANTENNAGATEAREA 0.180700 ;
    PORT
      LAYER Metal2 ;
        RECT 76.120 0.000 76.520 0.400 ;
    END
  END Tile_X0Y1_NN4END[10]
  PIN Tile_X0Y1_NN4END[11]
    DIRECTION INPUT ;
    USE SIGNAL ;
    ANTENNAGATEAREA 0.180700 ;
    PORT
      LAYER Metal2 ;
        RECT 77.080 0.000 77.480 0.400 ;
    END
  END Tile_X0Y1_NN4END[11]
  PIN Tile_X0Y1_NN4END[12]
    DIRECTION INPUT ;
    USE SIGNAL ;
    ANTENNAGATEAREA 0.180700 ;
    PORT
      LAYER Metal2 ;
        RECT 78.040 0.000 78.440 0.400 ;
    END
  END Tile_X0Y1_NN4END[12]
  PIN Tile_X0Y1_NN4END[13]
    DIRECTION INPUT ;
    USE SIGNAL ;
    ANTENNAGATEAREA 0.180700 ;
    PORT
      LAYER Metal2 ;
        RECT 79.000 0.000 79.400 0.400 ;
    END
  END Tile_X0Y1_NN4END[13]
  PIN Tile_X0Y1_NN4END[14]
    DIRECTION INPUT ;
    USE SIGNAL ;
    ANTENNAGATEAREA 0.180700 ;
    PORT
      LAYER Metal2 ;
        RECT 79.960 0.000 80.360 0.400 ;
    END
  END Tile_X0Y1_NN4END[14]
  PIN Tile_X0Y1_NN4END[15]
    DIRECTION INPUT ;
    USE SIGNAL ;
    ANTENNAGATEAREA 0.180700 ;
    PORT
      LAYER Metal2 ;
        RECT 80.920 0.000 81.320 0.400 ;
    END
  END Tile_X0Y1_NN4END[15]
  PIN Tile_X0Y1_NN4END[1]
    DIRECTION INPUT ;
    USE SIGNAL ;
    ANTENNAGATEAREA 0.607100 ;
    PORT
      LAYER Metal2 ;
        RECT 67.480 0.000 67.880 0.400 ;
    END
  END Tile_X0Y1_NN4END[1]
  PIN Tile_X0Y1_NN4END[2]
    DIRECTION INPUT ;
    USE SIGNAL ;
    ANTENNAGATEAREA 0.639600 ;
    PORT
      LAYER Metal2 ;
        RECT 68.440 0.000 68.840 0.400 ;
    END
  END Tile_X0Y1_NN4END[2]
  PIN Tile_X0Y1_NN4END[3]
    DIRECTION INPUT ;
    USE SIGNAL ;
    ANTENNAGATEAREA 0.639600 ;
    PORT
      LAYER Metal2 ;
        RECT 69.400 0.000 69.800 0.400 ;
    END
  END Tile_X0Y1_NN4END[3]
  PIN Tile_X0Y1_NN4END[4]
    DIRECTION INPUT ;
    USE SIGNAL ;
    ANTENNAGATEAREA 0.426400 ;
    PORT
      LAYER Metal2 ;
        RECT 70.360 0.000 70.760 0.400 ;
    END
  END Tile_X0Y1_NN4END[4]
  PIN Tile_X0Y1_NN4END[5]
    DIRECTION INPUT ;
    USE SIGNAL ;
    ANTENNAGATEAREA 0.668200 ;
    PORT
      LAYER Metal2 ;
        RECT 71.320 0.000 71.720 0.400 ;
    END
  END Tile_X0Y1_NN4END[5]
  PIN Tile_X0Y1_NN4END[6]
    DIRECTION INPUT ;
    USE SIGNAL ;
    ANTENNAGATEAREA 0.705400 ;
    PORT
      LAYER Metal2 ;
        RECT 72.280 0.000 72.680 0.400 ;
    END
  END Tile_X0Y1_NN4END[6]
  PIN Tile_X0Y1_NN4END[7]
    DIRECTION INPUT ;
    USE SIGNAL ;
    ANTENNAGATEAREA 3.073200 ;
    ANTENNADIFFAREA 8.061600 ;
    PORT
      LAYER Metal2 ;
        RECT 73.240 0.000 73.640 0.400 ;
    END
  END Tile_X0Y1_NN4END[7]
  PIN Tile_X0Y1_NN4END[8]
    DIRECTION INPUT ;
    USE SIGNAL ;
    ANTENNAGATEAREA 0.180700 ;
    PORT
      LAYER Metal2 ;
        RECT 74.200 0.000 74.600 0.400 ;
    END
  END Tile_X0Y1_NN4END[8]
  PIN Tile_X0Y1_NN4END[9]
    DIRECTION INPUT ;
    USE SIGNAL ;
    ANTENNAGATEAREA 0.180700 ;
    PORT
      LAYER Metal2 ;
        RECT 75.160 0.000 75.560 0.400 ;
    END
  END Tile_X0Y1_NN4END[9]
  PIN Tile_X0Y1_S1BEG[0]
    DIRECTION OUTPUT ;
    USE SIGNAL ;
    ANTENNADIFFAREA 0.708600 ;
    PORT
      LAYER Metal2 ;
        RECT 81.880 0.000 82.280 0.400 ;
    END
  END Tile_X0Y1_S1BEG[0]
  PIN Tile_X0Y1_S1BEG[1]
    DIRECTION OUTPUT ;
    USE SIGNAL ;
    ANTENNADIFFAREA 0.708600 ;
    PORT
      LAYER Metal2 ;
        RECT 82.840 0.000 83.240 0.400 ;
    END
  END Tile_X0Y1_S1BEG[1]
  PIN Tile_X0Y1_S1BEG[2]
    DIRECTION OUTPUT ;
    USE SIGNAL ;
    ANTENNADIFFAREA 0.708600 ;
    PORT
      LAYER Metal2 ;
        RECT 83.800 0.000 84.200 0.400 ;
    END
  END Tile_X0Y1_S1BEG[2]
  PIN Tile_X0Y1_S1BEG[3]
    DIRECTION OUTPUT ;
    USE SIGNAL ;
    ANTENNADIFFAREA 0.708600 ;
    PORT
      LAYER Metal2 ;
        RECT 84.760 0.000 85.160 0.400 ;
    END
  END Tile_X0Y1_S1BEG[3]
  PIN Tile_X0Y1_S2BEG[0]
    DIRECTION OUTPUT ;
    USE SIGNAL ;
    ANTENNADIFFAREA 0.708600 ;
    PORT
      LAYER Metal2 ;
        RECT 85.720 0.000 86.120 0.400 ;
    END
  END Tile_X0Y1_S2BEG[0]
  PIN Tile_X0Y1_S2BEG[1]
    DIRECTION OUTPUT ;
    USE SIGNAL ;
    ANTENNADIFFAREA 0.708600 ;
    PORT
      LAYER Metal2 ;
        RECT 86.680 0.000 87.080 0.400 ;
    END
  END Tile_X0Y1_S2BEG[1]
  PIN Tile_X0Y1_S2BEG[2]
    DIRECTION OUTPUT ;
    USE SIGNAL ;
    ANTENNADIFFAREA 0.708600 ;
    PORT
      LAYER Metal2 ;
        RECT 87.640 0.000 88.040 0.400 ;
    END
  END Tile_X0Y1_S2BEG[2]
  PIN Tile_X0Y1_S2BEG[3]
    DIRECTION OUTPUT ;
    USE SIGNAL ;
    ANTENNADIFFAREA 0.708600 ;
    PORT
      LAYER Metal2 ;
        RECT 88.600 0.000 89.000 0.400 ;
    END
  END Tile_X0Y1_S2BEG[3]
  PIN Tile_X0Y1_S2BEG[4]
    DIRECTION OUTPUT ;
    USE SIGNAL ;
    ANTENNADIFFAREA 0.708600 ;
    PORT
      LAYER Metal2 ;
        RECT 89.560 0.000 89.960 0.400 ;
    END
  END Tile_X0Y1_S2BEG[4]
  PIN Tile_X0Y1_S2BEG[5]
    DIRECTION OUTPUT ;
    USE SIGNAL ;
    ANTENNADIFFAREA 0.708600 ;
    PORT
      LAYER Metal2 ;
        RECT 90.520 0.000 90.920 0.400 ;
    END
  END Tile_X0Y1_S2BEG[5]
  PIN Tile_X0Y1_S2BEG[6]
    DIRECTION OUTPUT ;
    USE SIGNAL ;
    ANTENNADIFFAREA 0.708600 ;
    PORT
      LAYER Metal2 ;
        RECT 91.480 0.000 91.880 0.400 ;
    END
  END Tile_X0Y1_S2BEG[6]
  PIN Tile_X0Y1_S2BEG[7]
    DIRECTION OUTPUT ;
    USE SIGNAL ;
    ANTENNADIFFAREA 0.708600 ;
    PORT
      LAYER Metal2 ;
        RECT 92.440 0.000 92.840 0.400 ;
    END
  END Tile_X0Y1_S2BEG[7]
  PIN Tile_X0Y1_S2BEGb[0]
    DIRECTION OUTPUT ;
    USE SIGNAL ;
    ANTENNADIFFAREA 0.708600 ;
    PORT
      LAYER Metal2 ;
        RECT 93.400 0.000 93.800 0.400 ;
    END
  END Tile_X0Y1_S2BEGb[0]
  PIN Tile_X0Y1_S2BEGb[1]
    DIRECTION OUTPUT ;
    USE SIGNAL ;
    ANTENNADIFFAREA 0.708600 ;
    PORT
      LAYER Metal2 ;
        RECT 94.360 0.000 94.760 0.400 ;
    END
  END Tile_X0Y1_S2BEGb[1]
  PIN Tile_X0Y1_S2BEGb[2]
    DIRECTION OUTPUT ;
    USE SIGNAL ;
    ANTENNADIFFAREA 0.708600 ;
    PORT
      LAYER Metal2 ;
        RECT 95.320 0.000 95.720 0.400 ;
    END
  END Tile_X0Y1_S2BEGb[2]
  PIN Tile_X0Y1_S2BEGb[3]
    DIRECTION OUTPUT ;
    USE SIGNAL ;
    ANTENNADIFFAREA 0.708600 ;
    PORT
      LAYER Metal2 ;
        RECT 96.280 0.000 96.680 0.400 ;
    END
  END Tile_X0Y1_S2BEGb[3]
  PIN Tile_X0Y1_S2BEGb[4]
    DIRECTION OUTPUT ;
    USE SIGNAL ;
    ANTENNADIFFAREA 0.708600 ;
    PORT
      LAYER Metal2 ;
        RECT 97.240 0.000 97.640 0.400 ;
    END
  END Tile_X0Y1_S2BEGb[4]
  PIN Tile_X0Y1_S2BEGb[5]
    DIRECTION OUTPUT ;
    USE SIGNAL ;
    ANTENNADIFFAREA 0.708600 ;
    PORT
      LAYER Metal2 ;
        RECT 98.200 0.000 98.600 0.400 ;
    END
  END Tile_X0Y1_S2BEGb[5]
  PIN Tile_X0Y1_S2BEGb[6]
    DIRECTION OUTPUT ;
    USE SIGNAL ;
    ANTENNADIFFAREA 0.708600 ;
    PORT
      LAYER Metal2 ;
        RECT 99.160 0.000 99.560 0.400 ;
    END
  END Tile_X0Y1_S2BEGb[6]
  PIN Tile_X0Y1_S2BEGb[7]
    DIRECTION OUTPUT ;
    USE SIGNAL ;
    ANTENNADIFFAREA 0.708600 ;
    PORT
      LAYER Metal2 ;
        RECT 100.120 0.000 100.520 0.400 ;
    END
  END Tile_X0Y1_S2BEGb[7]
  PIN Tile_X0Y1_S4BEG[0]
    DIRECTION OUTPUT ;
    USE SIGNAL ;
    ANTENNADIFFAREA 0.708600 ;
    PORT
      LAYER Metal2 ;
        RECT 101.080 0.000 101.480 0.400 ;
    END
  END Tile_X0Y1_S4BEG[0]
  PIN Tile_X0Y1_S4BEG[10]
    DIRECTION OUTPUT ;
    USE SIGNAL ;
    ANTENNADIFFAREA 0.708600 ;
    PORT
      LAYER Metal2 ;
        RECT 110.680 0.000 111.080 0.400 ;
    END
  END Tile_X0Y1_S4BEG[10]
  PIN Tile_X0Y1_S4BEG[11]
    DIRECTION OUTPUT ;
    USE SIGNAL ;
    ANTENNADIFFAREA 0.708600 ;
    PORT
      LAYER Metal2 ;
        RECT 111.640 0.000 112.040 0.400 ;
    END
  END Tile_X0Y1_S4BEG[11]
  PIN Tile_X0Y1_S4BEG[12]
    DIRECTION OUTPUT ;
    USE SIGNAL ;
    ANTENNADIFFAREA 0.708600 ;
    PORT
      LAYER Metal2 ;
        RECT 112.600 0.000 113.000 0.400 ;
    END
  END Tile_X0Y1_S4BEG[12]
  PIN Tile_X0Y1_S4BEG[13]
    DIRECTION OUTPUT ;
    USE SIGNAL ;
    ANTENNADIFFAREA 0.708600 ;
    PORT
      LAYER Metal2 ;
        RECT 113.560 0.000 113.960 0.400 ;
    END
  END Tile_X0Y1_S4BEG[13]
  PIN Tile_X0Y1_S4BEG[14]
    DIRECTION OUTPUT ;
    USE SIGNAL ;
    ANTENNADIFFAREA 0.708600 ;
    PORT
      LAYER Metal2 ;
        RECT 114.520 0.000 114.920 0.400 ;
    END
  END Tile_X0Y1_S4BEG[14]
  PIN Tile_X0Y1_S4BEG[15]
    DIRECTION OUTPUT ;
    USE SIGNAL ;
    ANTENNADIFFAREA 0.708600 ;
    PORT
      LAYER Metal2 ;
        RECT 115.480 0.000 115.880 0.400 ;
    END
  END Tile_X0Y1_S4BEG[15]
  PIN Tile_X0Y1_S4BEG[1]
    DIRECTION OUTPUT ;
    USE SIGNAL ;
    ANTENNADIFFAREA 0.708600 ;
    PORT
      LAYER Metal2 ;
        RECT 102.040 0.000 102.440 0.400 ;
    END
  END Tile_X0Y1_S4BEG[1]
  PIN Tile_X0Y1_S4BEG[2]
    DIRECTION OUTPUT ;
    USE SIGNAL ;
    ANTENNADIFFAREA 0.708600 ;
    PORT
      LAYER Metal2 ;
        RECT 103.000 0.000 103.400 0.400 ;
    END
  END Tile_X0Y1_S4BEG[2]
  PIN Tile_X0Y1_S4BEG[3]
    DIRECTION OUTPUT ;
    USE SIGNAL ;
    ANTENNADIFFAREA 0.708600 ;
    PORT
      LAYER Metal2 ;
        RECT 103.960 0.000 104.360 0.400 ;
    END
  END Tile_X0Y1_S4BEG[3]
  PIN Tile_X0Y1_S4BEG[4]
    DIRECTION OUTPUT ;
    USE SIGNAL ;
    ANTENNADIFFAREA 0.708600 ;
    PORT
      LAYER Metal2 ;
        RECT 104.920 0.000 105.320 0.400 ;
    END
  END Tile_X0Y1_S4BEG[4]
  PIN Tile_X0Y1_S4BEG[5]
    DIRECTION OUTPUT ;
    USE SIGNAL ;
    ANTENNADIFFAREA 0.708600 ;
    PORT
      LAYER Metal2 ;
        RECT 105.880 0.000 106.280 0.400 ;
    END
  END Tile_X0Y1_S4BEG[5]
  PIN Tile_X0Y1_S4BEG[6]
    DIRECTION OUTPUT ;
    USE SIGNAL ;
    ANTENNADIFFAREA 0.708600 ;
    PORT
      LAYER Metal2 ;
        RECT 106.840 0.000 107.240 0.400 ;
    END
  END Tile_X0Y1_S4BEG[6]
  PIN Tile_X0Y1_S4BEG[7]
    DIRECTION OUTPUT ;
    USE SIGNAL ;
    ANTENNADIFFAREA 0.708600 ;
    PORT
      LAYER Metal2 ;
        RECT 107.800 0.000 108.200 0.400 ;
    END
  END Tile_X0Y1_S4BEG[7]
  PIN Tile_X0Y1_S4BEG[8]
    DIRECTION OUTPUT ;
    USE SIGNAL ;
    ANTENNADIFFAREA 0.708600 ;
    PORT
      LAYER Metal2 ;
        RECT 108.760 0.000 109.160 0.400 ;
    END
  END Tile_X0Y1_S4BEG[8]
  PIN Tile_X0Y1_S4BEG[9]
    DIRECTION OUTPUT ;
    USE SIGNAL ;
    ANTENNADIFFAREA 0.708600 ;
    PORT
      LAYER Metal2 ;
        RECT 109.720 0.000 110.120 0.400 ;
    END
  END Tile_X0Y1_S4BEG[9]
  PIN Tile_X0Y1_SS4BEG[0]
    DIRECTION OUTPUT ;
    USE SIGNAL ;
    ANTENNADIFFAREA 0.708600 ;
    PORT
      LAYER Metal2 ;
        RECT 116.440 0.000 116.840 0.400 ;
    END
  END Tile_X0Y1_SS4BEG[0]
  PIN Tile_X0Y1_SS4BEG[10]
    DIRECTION OUTPUT ;
    USE SIGNAL ;
    ANTENNADIFFAREA 0.708600 ;
    PORT
      LAYER Metal2 ;
        RECT 126.040 0.000 126.440 0.400 ;
    END
  END Tile_X0Y1_SS4BEG[10]
  PIN Tile_X0Y1_SS4BEG[11]
    DIRECTION OUTPUT ;
    USE SIGNAL ;
    ANTENNADIFFAREA 0.708600 ;
    PORT
      LAYER Metal2 ;
        RECT 127.000 0.000 127.400 0.400 ;
    END
  END Tile_X0Y1_SS4BEG[11]
  PIN Tile_X0Y1_SS4BEG[12]
    DIRECTION OUTPUT ;
    USE SIGNAL ;
    ANTENNADIFFAREA 0.708600 ;
    PORT
      LAYER Metal2 ;
        RECT 127.960 0.000 128.360 0.400 ;
    END
  END Tile_X0Y1_SS4BEG[12]
  PIN Tile_X0Y1_SS4BEG[13]
    DIRECTION OUTPUT ;
    USE SIGNAL ;
    ANTENNADIFFAREA 0.708600 ;
    PORT
      LAYER Metal2 ;
        RECT 128.920 0.000 129.320 0.400 ;
    END
  END Tile_X0Y1_SS4BEG[13]
  PIN Tile_X0Y1_SS4BEG[14]
    DIRECTION OUTPUT ;
    USE SIGNAL ;
    ANTENNADIFFAREA 0.708600 ;
    PORT
      LAYER Metal2 ;
        RECT 129.880 0.000 130.280 0.400 ;
    END
  END Tile_X0Y1_SS4BEG[14]
  PIN Tile_X0Y1_SS4BEG[15]
    DIRECTION OUTPUT ;
    USE SIGNAL ;
    ANTENNADIFFAREA 0.708600 ;
    PORT
      LAYER Metal2 ;
        RECT 130.840 0.000 131.240 0.400 ;
    END
  END Tile_X0Y1_SS4BEG[15]
  PIN Tile_X0Y1_SS4BEG[1]
    DIRECTION OUTPUT ;
    USE SIGNAL ;
    ANTENNADIFFAREA 0.708600 ;
    PORT
      LAYER Metal2 ;
        RECT 117.400 0.000 117.800 0.400 ;
    END
  END Tile_X0Y1_SS4BEG[1]
  PIN Tile_X0Y1_SS4BEG[2]
    DIRECTION OUTPUT ;
    USE SIGNAL ;
    ANTENNADIFFAREA 0.708600 ;
    PORT
      LAYER Metal2 ;
        RECT 118.360 0.000 118.760 0.400 ;
    END
  END Tile_X0Y1_SS4BEG[2]
  PIN Tile_X0Y1_SS4BEG[3]
    DIRECTION OUTPUT ;
    USE SIGNAL ;
    ANTENNADIFFAREA 0.708600 ;
    PORT
      LAYER Metal2 ;
        RECT 119.320 0.000 119.720 0.400 ;
    END
  END Tile_X0Y1_SS4BEG[3]
  PIN Tile_X0Y1_SS4BEG[4]
    DIRECTION OUTPUT ;
    USE SIGNAL ;
    ANTENNADIFFAREA 0.708600 ;
    PORT
      LAYER Metal2 ;
        RECT 120.280 0.000 120.680 0.400 ;
    END
  END Tile_X0Y1_SS4BEG[4]
  PIN Tile_X0Y1_SS4BEG[5]
    DIRECTION OUTPUT ;
    USE SIGNAL ;
    ANTENNADIFFAREA 0.708600 ;
    PORT
      LAYER Metal2 ;
        RECT 121.240 0.000 121.640 0.400 ;
    END
  END Tile_X0Y1_SS4BEG[5]
  PIN Tile_X0Y1_SS4BEG[6]
    DIRECTION OUTPUT ;
    USE SIGNAL ;
    ANTENNADIFFAREA 0.708600 ;
    PORT
      LAYER Metal2 ;
        RECT 122.200 0.000 122.600 0.400 ;
    END
  END Tile_X0Y1_SS4BEG[6]
  PIN Tile_X0Y1_SS4BEG[7]
    DIRECTION OUTPUT ;
    USE SIGNAL ;
    ANTENNADIFFAREA 0.708600 ;
    PORT
      LAYER Metal2 ;
        RECT 123.160 0.000 123.560 0.400 ;
    END
  END Tile_X0Y1_SS4BEG[7]
  PIN Tile_X0Y1_SS4BEG[8]
    DIRECTION OUTPUT ;
    USE SIGNAL ;
    ANTENNADIFFAREA 0.708600 ;
    PORT
      LAYER Metal2 ;
        RECT 124.120 0.000 124.520 0.400 ;
    END
  END Tile_X0Y1_SS4BEG[8]
  PIN Tile_X0Y1_SS4BEG[9]
    DIRECTION OUTPUT ;
    USE SIGNAL ;
    ANTENNADIFFAREA 0.708600 ;
    PORT
      LAYER Metal2 ;
        RECT 125.080 0.000 125.480 0.400 ;
    END
  END Tile_X0Y1_SS4BEG[9]
  PIN Tile_X0Y1_UserCLK
    DIRECTION INPUT ;
    USE SIGNAL ;
    ANTENNAGATEAREA 1.450800 ;
    PORT
      LAYER Metal2 ;
        RECT 131.800 0.000 132.200 0.400 ;
    END
  END Tile_X0Y1_UserCLK
  PIN Tile_X0Y1_W1BEG[0]
    DIRECTION OUTPUT ;
    USE SIGNAL ;
    ANTENNADIFFAREA 0.708600 ;
    PORT
      LAYER Metal3 ;
        RECT 0.000 0.220 0.400 0.620 ;
    END
  END Tile_X0Y1_W1BEG[0]
  PIN Tile_X0Y1_W1BEG[1]
    DIRECTION OUTPUT ;
    USE SIGNAL ;
    ANTENNADIFFAREA 0.708600 ;
    PORT
      LAYER Metal3 ;
        RECT 0.000 1.900 0.400 2.300 ;
    END
  END Tile_X0Y1_W1BEG[1]
  PIN Tile_X0Y1_W1BEG[2]
    DIRECTION OUTPUT ;
    USE SIGNAL ;
    ANTENNADIFFAREA 0.708600 ;
    PORT
      LAYER Metal3 ;
        RECT 0.000 3.580 0.400 3.980 ;
    END
  END Tile_X0Y1_W1BEG[2]
  PIN Tile_X0Y1_W1BEG[3]
    DIRECTION OUTPUT ;
    USE SIGNAL ;
    ANTENNADIFFAREA 0.708600 ;
    PORT
      LAYER Metal3 ;
        RECT 0.000 5.260 0.400 5.660 ;
    END
  END Tile_X0Y1_W1BEG[3]
  PIN Tile_X0Y1_W1END[0]
    DIRECTION INPUT ;
    USE SIGNAL ;
    ANTENNAGATEAREA 1.865800 ;
    PORT
      LAYER Metal3 ;
        RECT 184.400 0.220 184.800 0.620 ;
    END
  END Tile_X0Y1_W1END[0]
  PIN Tile_X0Y1_W1END[1]
    DIRECTION INPUT ;
    USE SIGNAL ;
    ANTENNAGATEAREA 2.173400 ;
    PORT
      LAYER Metal3 ;
        RECT 184.400 1.900 184.800 2.300 ;
    END
  END Tile_X0Y1_W1END[1]
  PIN Tile_X0Y1_W1END[2]
    DIRECTION INPUT ;
    USE SIGNAL ;
    ANTENNAGATEAREA 2.431000 ;
    PORT
      LAYER Metal3 ;
        RECT 184.400 3.580 184.800 3.980 ;
    END
  END Tile_X0Y1_W1END[2]
  PIN Tile_X0Y1_W1END[3]
    DIRECTION INPUT ;
    USE SIGNAL ;
    ANTENNAGATEAREA 1.521000 ;
    PORT
      LAYER Metal3 ;
        RECT 184.400 5.260 184.800 5.660 ;
    END
  END Tile_X0Y1_W1END[3]
  PIN Tile_X0Y1_W2BEG[0]
    DIRECTION OUTPUT ;
    USE SIGNAL ;
    ANTENNADIFFAREA 0.708600 ;
    PORT
      LAYER Metal3 ;
        RECT 0.000 6.940 0.400 7.340 ;
    END
  END Tile_X0Y1_W2BEG[0]
  PIN Tile_X0Y1_W2BEG[1]
    DIRECTION OUTPUT ;
    USE SIGNAL ;
    ANTENNADIFFAREA 0.708600 ;
    PORT
      LAYER Metal3 ;
        RECT 0.000 8.620 0.400 9.020 ;
    END
  END Tile_X0Y1_W2BEG[1]
  PIN Tile_X0Y1_W2BEG[2]
    DIRECTION OUTPUT ;
    USE SIGNAL ;
    ANTENNADIFFAREA 0.708600 ;
    PORT
      LAYER Metal3 ;
        RECT 0.000 10.300 0.400 10.700 ;
    END
  END Tile_X0Y1_W2BEG[2]
  PIN Tile_X0Y1_W2BEG[3]
    DIRECTION OUTPUT ;
    USE SIGNAL ;
    ANTENNADIFFAREA 0.708600 ;
    PORT
      LAYER Metal3 ;
        RECT 0.000 11.980 0.400 12.380 ;
    END
  END Tile_X0Y1_W2BEG[3]
  PIN Tile_X0Y1_W2BEG[4]
    DIRECTION OUTPUT ;
    USE SIGNAL ;
    ANTENNADIFFAREA 0.708600 ;
    PORT
      LAYER Metal3 ;
        RECT 0.000 13.660 0.400 14.060 ;
    END
  END Tile_X0Y1_W2BEG[4]
  PIN Tile_X0Y1_W2BEG[5]
    DIRECTION OUTPUT ;
    USE SIGNAL ;
    ANTENNADIFFAREA 0.708600 ;
    PORT
      LAYER Metal3 ;
        RECT 0.000 15.340 0.400 15.740 ;
    END
  END Tile_X0Y1_W2BEG[5]
  PIN Tile_X0Y1_W2BEG[6]
    DIRECTION OUTPUT ;
    USE SIGNAL ;
    ANTENNADIFFAREA 0.708600 ;
    PORT
      LAYER Metal3 ;
        RECT 0.000 17.020 0.400 17.420 ;
    END
  END Tile_X0Y1_W2BEG[6]
  PIN Tile_X0Y1_W2BEG[7]
    DIRECTION OUTPUT ;
    USE SIGNAL ;
    ANTENNADIFFAREA 0.708600 ;
    PORT
      LAYER Metal3 ;
        RECT 0.000 18.700 0.400 19.100 ;
    END
  END Tile_X0Y1_W2BEG[7]
  PIN Tile_X0Y1_W2BEGb[0]
    DIRECTION OUTPUT ;
    USE SIGNAL ;
    ANTENNADIFFAREA 0.708600 ;
    PORT
      LAYER Metal3 ;
        RECT 0.000 20.380 0.400 20.780 ;
    END
  END Tile_X0Y1_W2BEGb[0]
  PIN Tile_X0Y1_W2BEGb[1]
    DIRECTION OUTPUT ;
    USE SIGNAL ;
    ANTENNADIFFAREA 0.708600 ;
    PORT
      LAYER Metal3 ;
        RECT 0.000 22.060 0.400 22.460 ;
    END
  END Tile_X0Y1_W2BEGb[1]
  PIN Tile_X0Y1_W2BEGb[2]
    DIRECTION OUTPUT ;
    USE SIGNAL ;
    ANTENNADIFFAREA 0.708600 ;
    PORT
      LAYER Metal3 ;
        RECT 0.000 23.740 0.400 24.140 ;
    END
  END Tile_X0Y1_W2BEGb[2]
  PIN Tile_X0Y1_W2BEGb[3]
    DIRECTION OUTPUT ;
    USE SIGNAL ;
    ANTENNADIFFAREA 0.708600 ;
    PORT
      LAYER Metal3 ;
        RECT 0.000 25.420 0.400 25.820 ;
    END
  END Tile_X0Y1_W2BEGb[3]
  PIN Tile_X0Y1_W2BEGb[4]
    DIRECTION OUTPUT ;
    USE SIGNAL ;
    ANTENNADIFFAREA 0.708600 ;
    PORT
      LAYER Metal3 ;
        RECT 0.000 27.100 0.400 27.500 ;
    END
  END Tile_X0Y1_W2BEGb[4]
  PIN Tile_X0Y1_W2BEGb[5]
    DIRECTION OUTPUT ;
    USE SIGNAL ;
    ANTENNADIFFAREA 0.708600 ;
    PORT
      LAYER Metal3 ;
        RECT 0.000 28.780 0.400 29.180 ;
    END
  END Tile_X0Y1_W2BEGb[5]
  PIN Tile_X0Y1_W2BEGb[6]
    DIRECTION OUTPUT ;
    USE SIGNAL ;
    ANTENNADIFFAREA 0.708600 ;
    PORT
      LAYER Metal3 ;
        RECT 0.000 30.460 0.400 30.860 ;
    END
  END Tile_X0Y1_W2BEGb[6]
  PIN Tile_X0Y1_W2BEGb[7]
    DIRECTION OUTPUT ;
    USE SIGNAL ;
    ANTENNADIFFAREA 0.708600 ;
    PORT
      LAYER Metal3 ;
        RECT 0.000 32.140 0.400 32.540 ;
    END
  END Tile_X0Y1_W2BEGb[7]
  PIN Tile_X0Y1_W2END[0]
    DIRECTION INPUT ;
    USE SIGNAL ;
    ANTENNAGATEAREA 0.607100 ;
    PORT
      LAYER Metal3 ;
        RECT 184.400 20.380 184.800 20.780 ;
    END
  END Tile_X0Y1_W2END[0]
  PIN Tile_X0Y1_W2END[1]
    DIRECTION INPUT ;
    USE SIGNAL ;
    ANTENNAGATEAREA 1.489600 ;
    PORT
      LAYER Metal3 ;
        RECT 184.400 22.060 184.800 22.460 ;
    END
  END Tile_X0Y1_W2END[1]
  PIN Tile_X0Y1_W2END[2]
    DIRECTION INPUT ;
    USE SIGNAL ;
    ANTENNAGATEAREA 1.325500 ;
    PORT
      LAYER Metal3 ;
        RECT 184.400 23.740 184.800 24.140 ;
    END
  END Tile_X0Y1_W2END[2]
  PIN Tile_X0Y1_W2END[3]
    DIRECTION INPUT ;
    USE SIGNAL ;
    ANTENNAGATEAREA 1.551700 ;
    PORT
      LAYER Metal3 ;
        RECT 184.400 25.420 184.800 25.820 ;
    END
  END Tile_X0Y1_W2END[3]
  PIN Tile_X0Y1_W2END[4]
    DIRECTION INPUT ;
    USE SIGNAL ;
    ANTENNAGATEAREA 1.817700 ;
    PORT
      LAYER Metal3 ;
        RECT 184.400 27.100 184.800 27.500 ;
    END
  END Tile_X0Y1_W2END[4]
  PIN Tile_X0Y1_W2END[5]
    DIRECTION INPUT ;
    USE SIGNAL ;
    ANTENNAGATEAREA 0.426400 ;
    PORT
      LAYER Metal3 ;
        RECT 184.400 28.780 184.800 29.180 ;
    END
  END Tile_X0Y1_W2END[5]
  PIN Tile_X0Y1_W2END[6]
    DIRECTION INPUT ;
    USE SIGNAL ;
    ANTENNAGATEAREA 0.426400 ;
    PORT
      LAYER Metal3 ;
        RECT 184.400 30.460 184.800 30.860 ;
    END
  END Tile_X0Y1_W2END[6]
  PIN Tile_X0Y1_W2END[7]
    DIRECTION INPUT ;
    USE SIGNAL ;
    ANTENNAGATEAREA 0.886100 ;
    PORT
      LAYER Metal3 ;
        RECT 184.400 32.140 184.800 32.540 ;
    END
  END Tile_X0Y1_W2END[7]
  PIN Tile_X0Y1_W2MID[0]
    DIRECTION INPUT ;
    USE SIGNAL ;
    ANTENNAGATEAREA 1.230900 ;
    PORT
      LAYER Metal3 ;
        RECT 184.400 6.940 184.800 7.340 ;
    END
  END Tile_X0Y1_W2MID[0]
  PIN Tile_X0Y1_W2MID[1]
    DIRECTION INPUT ;
    USE SIGNAL ;
    ANTENNAGATEAREA 1.156500 ;
    PORT
      LAYER Metal3 ;
        RECT 184.400 8.620 184.800 9.020 ;
    END
  END Tile_X0Y1_W2MID[1]
  PIN Tile_X0Y1_W2MID[2]
    DIRECTION INPUT ;
    USE SIGNAL ;
    ANTENNAGATEAREA 0.853600 ;
    PORT
      LAYER Metal3 ;
        RECT 184.400 10.300 184.800 10.700 ;
    END
  END Tile_X0Y1_W2MID[2]
  PIN Tile_X0Y1_W2MID[3]
    DIRECTION INPUT ;
    USE SIGNAL ;
    ANTENNAGATEAREA 0.848900 ;
    PORT
      LAYER Metal3 ;
        RECT 184.400 11.980 184.800 12.380 ;
    END
  END Tile_X0Y1_W2MID[3]
  PIN Tile_X0Y1_W2MID[4]
    DIRECTION INPUT ;
    USE SIGNAL ;
    ANTENNAGATEAREA 0.422500 ;
    PORT
      LAYER Metal3 ;
        RECT 184.400 13.660 184.800 14.060 ;
    END
  END Tile_X0Y1_W2MID[4]
  PIN Tile_X0Y1_W2MID[5]
    DIRECTION INPUT ;
    USE SIGNAL ;
    ANTENNAGATEAREA 1.033500 ;
    PORT
      LAYER Metal3 ;
        RECT 184.400 15.340 184.800 15.740 ;
    END
  END Tile_X0Y1_W2MID[5]
  PIN Tile_X0Y1_W2MID[6]
    DIRECTION INPUT ;
    USE SIGNAL ;
    ANTENNAGATEAREA 0.951900 ;
    PORT
      LAYER Metal3 ;
        RECT 184.400 17.020 184.800 17.420 ;
    END
  END Tile_X0Y1_W2MID[6]
  PIN Tile_X0Y1_W2MID[7]
    DIRECTION INPUT ;
    USE SIGNAL ;
    ANTENNAGATEAREA 1.119300 ;
    PORT
      LAYER Metal3 ;
        RECT 184.400 18.700 184.800 19.100 ;
    END
  END Tile_X0Y1_W2MID[7]
  PIN Tile_X0Y1_W6BEG[0]
    DIRECTION OUTPUT ;
    USE SIGNAL ;
    ANTENNADIFFAREA 0.708600 ;
    PORT
      LAYER Metal3 ;
        RECT 0.000 60.700 0.400 61.100 ;
    END
  END Tile_X0Y1_W6BEG[0]
  PIN Tile_X0Y1_W6BEG[10]
    DIRECTION OUTPUT ;
    USE SIGNAL ;
    ANTENNADIFFAREA 0.708600 ;
    PORT
      LAYER Metal3 ;
        RECT 0.000 77.500 0.400 77.900 ;
    END
  END Tile_X0Y1_W6BEG[10]
  PIN Tile_X0Y1_W6BEG[11]
    DIRECTION OUTPUT ;
    USE SIGNAL ;
    ANTENNADIFFAREA 0.708600 ;
    PORT
      LAYER Metal3 ;
        RECT 0.000 79.180 0.400 79.580 ;
    END
  END Tile_X0Y1_W6BEG[11]
  PIN Tile_X0Y1_W6BEG[1]
    DIRECTION OUTPUT ;
    USE SIGNAL ;
    ANTENNADIFFAREA 0.708600 ;
    PORT
      LAYER Metal3 ;
        RECT 0.000 62.380 0.400 62.780 ;
    END
  END Tile_X0Y1_W6BEG[1]
  PIN Tile_X0Y1_W6BEG[2]
    DIRECTION OUTPUT ;
    USE SIGNAL ;
    ANTENNADIFFAREA 0.708600 ;
    PORT
      LAYER Metal3 ;
        RECT 0.000 64.060 0.400 64.460 ;
    END
  END Tile_X0Y1_W6BEG[2]
  PIN Tile_X0Y1_W6BEG[3]
    DIRECTION OUTPUT ;
    USE SIGNAL ;
    ANTENNADIFFAREA 0.708600 ;
    PORT
      LAYER Metal3 ;
        RECT 0.000 65.740 0.400 66.140 ;
    END
  END Tile_X0Y1_W6BEG[3]
  PIN Tile_X0Y1_W6BEG[4]
    DIRECTION OUTPUT ;
    USE SIGNAL ;
    ANTENNADIFFAREA 0.708600 ;
    PORT
      LAYER Metal3 ;
        RECT 0.000 67.420 0.400 67.820 ;
    END
  END Tile_X0Y1_W6BEG[4]
  PIN Tile_X0Y1_W6BEG[5]
    DIRECTION OUTPUT ;
    USE SIGNAL ;
    ANTENNADIFFAREA 0.708600 ;
    PORT
      LAYER Metal3 ;
        RECT 0.000 69.100 0.400 69.500 ;
    END
  END Tile_X0Y1_W6BEG[5]
  PIN Tile_X0Y1_W6BEG[6]
    DIRECTION OUTPUT ;
    USE SIGNAL ;
    ANTENNADIFFAREA 0.708600 ;
    PORT
      LAYER Metal3 ;
        RECT 0.000 70.780 0.400 71.180 ;
    END
  END Tile_X0Y1_W6BEG[6]
  PIN Tile_X0Y1_W6BEG[7]
    DIRECTION OUTPUT ;
    USE SIGNAL ;
    ANTENNADIFFAREA 0.708600 ;
    PORT
      LAYER Metal3 ;
        RECT 0.000 72.460 0.400 72.860 ;
    END
  END Tile_X0Y1_W6BEG[7]
  PIN Tile_X0Y1_W6BEG[8]
    DIRECTION OUTPUT ;
    USE SIGNAL ;
    ANTENNADIFFAREA 0.708600 ;
    PORT
      LAYER Metal3 ;
        RECT 0.000 74.140 0.400 74.540 ;
    END
  END Tile_X0Y1_W6BEG[8]
  PIN Tile_X0Y1_W6BEG[9]
    DIRECTION OUTPUT ;
    USE SIGNAL ;
    ANTENNADIFFAREA 0.708600 ;
    PORT
      LAYER Metal3 ;
        RECT 0.000 75.820 0.400 76.220 ;
    END
  END Tile_X0Y1_W6BEG[9]
  PIN Tile_X0Y1_W6END[0]
    DIRECTION INPUT ;
    USE SIGNAL ;
    ANTENNAGATEAREA 1.974200 ;
    PORT
      LAYER Metal3 ;
        RECT 184.400 60.700 184.800 61.100 ;
    END
  END Tile_X0Y1_W6END[0]
  PIN Tile_X0Y1_W6END[10]
    DIRECTION INPUT ;
    USE SIGNAL ;
    ANTENNAGATEAREA 0.180700 ;
    PORT
      LAYER Metal3 ;
        RECT 184.400 77.500 184.800 77.900 ;
    END
  END Tile_X0Y1_W6END[10]
  PIN Tile_X0Y1_W6END[11]
    DIRECTION INPUT ;
    USE SIGNAL ;
    ANTENNAGATEAREA 0.180700 ;
    PORT
      LAYER Metal3 ;
        RECT 184.400 79.180 184.800 79.580 ;
    END
  END Tile_X0Y1_W6END[11]
  PIN Tile_X0Y1_W6END[1]
    DIRECTION INPUT ;
    USE SIGNAL ;
    ANTENNAGATEAREA 1.547000 ;
    PORT
      LAYER Metal3 ;
        RECT 184.400 62.380 184.800 62.780 ;
    END
  END Tile_X0Y1_W6END[1]
  PIN Tile_X0Y1_W6END[2]
    DIRECTION INPUT ;
    USE SIGNAL ;
    ANTENNAGATEAREA 0.180700 ;
    PORT
      LAYER Metal3 ;
        RECT 184.400 64.060 184.800 64.460 ;
    END
  END Tile_X0Y1_W6END[2]
  PIN Tile_X0Y1_W6END[3]
    DIRECTION INPUT ;
    USE SIGNAL ;
    ANTENNAGATEAREA 0.180700 ;
    PORT
      LAYER Metal3 ;
        RECT 184.400 65.740 184.800 66.140 ;
    END
  END Tile_X0Y1_W6END[3]
  PIN Tile_X0Y1_W6END[4]
    DIRECTION INPUT ;
    USE SIGNAL ;
    ANTENNAGATEAREA 0.180700 ;
    PORT
      LAYER Metal3 ;
        RECT 184.400 67.420 184.800 67.820 ;
    END
  END Tile_X0Y1_W6END[4]
  PIN Tile_X0Y1_W6END[5]
    DIRECTION INPUT ;
    USE SIGNAL ;
    ANTENNAGATEAREA 0.180700 ;
    PORT
      LAYER Metal3 ;
        RECT 184.400 69.100 184.800 69.500 ;
    END
  END Tile_X0Y1_W6END[5]
  PIN Tile_X0Y1_W6END[6]
    DIRECTION INPUT ;
    USE SIGNAL ;
    ANTENNAGATEAREA 0.180700 ;
    PORT
      LAYER Metal3 ;
        RECT 184.400 70.780 184.800 71.180 ;
    END
  END Tile_X0Y1_W6END[6]
  PIN Tile_X0Y1_W6END[7]
    DIRECTION INPUT ;
    USE SIGNAL ;
    ANTENNAGATEAREA 0.180700 ;
    PORT
      LAYER Metal3 ;
        RECT 184.400 72.460 184.800 72.860 ;
    END
  END Tile_X0Y1_W6END[7]
  PIN Tile_X0Y1_W6END[8]
    DIRECTION INPUT ;
    USE SIGNAL ;
    ANTENNAGATEAREA 0.180700 ;
    PORT
      LAYER Metal3 ;
        RECT 184.400 74.140 184.800 74.540 ;
    END
  END Tile_X0Y1_W6END[8]
  PIN Tile_X0Y1_W6END[9]
    DIRECTION INPUT ;
    USE SIGNAL ;
    ANTENNAGATEAREA 0.180700 ;
    PORT
      LAYER Metal3 ;
        RECT 184.400 75.820 184.800 76.220 ;
    END
  END Tile_X0Y1_W6END[9]
  PIN Tile_X0Y1_WW4BEG[0]
    DIRECTION OUTPUT ;
    USE SIGNAL ;
    ANTENNADIFFAREA 0.708600 ;
    PORT
      LAYER Metal3 ;
        RECT 0.000 33.820 0.400 34.220 ;
    END
  END Tile_X0Y1_WW4BEG[0]
  PIN Tile_X0Y1_WW4BEG[10]
    DIRECTION OUTPUT ;
    USE SIGNAL ;
    ANTENNADIFFAREA 0.708600 ;
    PORT
      LAYER Metal3 ;
        RECT 0.000 50.620 0.400 51.020 ;
    END
  END Tile_X0Y1_WW4BEG[10]
  PIN Tile_X0Y1_WW4BEG[11]
    DIRECTION OUTPUT ;
    USE SIGNAL ;
    ANTENNADIFFAREA 0.708600 ;
    PORT
      LAYER Metal3 ;
        RECT 0.000 52.300 0.400 52.700 ;
    END
  END Tile_X0Y1_WW4BEG[11]
  PIN Tile_X0Y1_WW4BEG[12]
    DIRECTION OUTPUT ;
    USE SIGNAL ;
    ANTENNADIFFAREA 0.708600 ;
    PORT
      LAYER Metal3 ;
        RECT 0.000 53.980 0.400 54.380 ;
    END
  END Tile_X0Y1_WW4BEG[12]
  PIN Tile_X0Y1_WW4BEG[13]
    DIRECTION OUTPUT ;
    USE SIGNAL ;
    ANTENNADIFFAREA 0.708600 ;
    PORT
      LAYER Metal3 ;
        RECT 0.000 55.660 0.400 56.060 ;
    END
  END Tile_X0Y1_WW4BEG[13]
  PIN Tile_X0Y1_WW4BEG[14]
    DIRECTION OUTPUT ;
    USE SIGNAL ;
    ANTENNADIFFAREA 0.708600 ;
    PORT
      LAYER Metal3 ;
        RECT 0.000 57.340 0.400 57.740 ;
    END
  END Tile_X0Y1_WW4BEG[14]
  PIN Tile_X0Y1_WW4BEG[15]
    DIRECTION OUTPUT ;
    USE SIGNAL ;
    ANTENNADIFFAREA 0.708600 ;
    PORT
      LAYER Metal3 ;
        RECT 0.000 59.020 0.400 59.420 ;
    END
  END Tile_X0Y1_WW4BEG[15]
  PIN Tile_X0Y1_WW4BEG[1]
    DIRECTION OUTPUT ;
    USE SIGNAL ;
    ANTENNADIFFAREA 0.708600 ;
    PORT
      LAYER Metal3 ;
        RECT 0.000 35.500 0.400 35.900 ;
    END
  END Tile_X0Y1_WW4BEG[1]
  PIN Tile_X0Y1_WW4BEG[2]
    DIRECTION OUTPUT ;
    USE SIGNAL ;
    ANTENNADIFFAREA 0.708600 ;
    PORT
      LAYER Metal3 ;
        RECT 0.000 37.180 0.400 37.580 ;
    END
  END Tile_X0Y1_WW4BEG[2]
  PIN Tile_X0Y1_WW4BEG[3]
    DIRECTION OUTPUT ;
    USE SIGNAL ;
    ANTENNADIFFAREA 0.708600 ;
    PORT
      LAYER Metal3 ;
        RECT 0.000 38.860 0.400 39.260 ;
    END
  END Tile_X0Y1_WW4BEG[3]
  PIN Tile_X0Y1_WW4BEG[4]
    DIRECTION OUTPUT ;
    USE SIGNAL ;
    ANTENNADIFFAREA 0.708600 ;
    PORT
      LAYER Metal3 ;
        RECT 0.000 40.540 0.400 40.940 ;
    END
  END Tile_X0Y1_WW4BEG[4]
  PIN Tile_X0Y1_WW4BEG[5]
    DIRECTION OUTPUT ;
    USE SIGNAL ;
    ANTENNADIFFAREA 0.708600 ;
    PORT
      LAYER Metal3 ;
        RECT 0.000 42.220 0.400 42.620 ;
    END
  END Tile_X0Y1_WW4BEG[5]
  PIN Tile_X0Y1_WW4BEG[6]
    DIRECTION OUTPUT ;
    USE SIGNAL ;
    ANTENNADIFFAREA 0.708600 ;
    PORT
      LAYER Metal3 ;
        RECT 0.000 43.900 0.400 44.300 ;
    END
  END Tile_X0Y1_WW4BEG[6]
  PIN Tile_X0Y1_WW4BEG[7]
    DIRECTION OUTPUT ;
    USE SIGNAL ;
    ANTENNADIFFAREA 0.708600 ;
    PORT
      LAYER Metal3 ;
        RECT 0.000 45.580 0.400 45.980 ;
    END
  END Tile_X0Y1_WW4BEG[7]
  PIN Tile_X0Y1_WW4BEG[8]
    DIRECTION OUTPUT ;
    USE SIGNAL ;
    ANTENNADIFFAREA 0.708600 ;
    PORT
      LAYER Metal3 ;
        RECT 0.000 47.260 0.400 47.660 ;
    END
  END Tile_X0Y1_WW4BEG[8]
  PIN Tile_X0Y1_WW4BEG[9]
    DIRECTION OUTPUT ;
    USE SIGNAL ;
    ANTENNADIFFAREA 0.708600 ;
    PORT
      LAYER Metal3 ;
        RECT 0.000 48.940 0.400 49.340 ;
    END
  END Tile_X0Y1_WW4BEG[9]
  PIN Tile_X0Y1_WW4END[0]
    DIRECTION INPUT ;
    USE SIGNAL ;
    ANTENNAGATEAREA 0.668200 ;
    PORT
      LAYER Metal3 ;
        RECT 184.400 33.820 184.800 34.220 ;
    END
  END Tile_X0Y1_WW4END[0]
  PIN Tile_X0Y1_WW4END[10]
    DIRECTION INPUT ;
    USE SIGNAL ;
    ANTENNAGATEAREA 0.180700 ;
    PORT
      LAYER Metal3 ;
        RECT 184.400 50.620 184.800 51.020 ;
    END
  END Tile_X0Y1_WW4END[10]
  PIN Tile_X0Y1_WW4END[11]
    DIRECTION INPUT ;
    USE SIGNAL ;
    ANTENNAGATEAREA 0.180700 ;
    PORT
      LAYER Metal3 ;
        RECT 184.400 52.300 184.800 52.700 ;
    END
  END Tile_X0Y1_WW4END[11]
  PIN Tile_X0Y1_WW4END[12]
    DIRECTION INPUT ;
    USE SIGNAL ;
    ANTENNAGATEAREA 0.180700 ;
    PORT
      LAYER Metal3 ;
        RECT 184.400 53.980 184.800 54.380 ;
    END
  END Tile_X0Y1_WW4END[12]
  PIN Tile_X0Y1_WW4END[13]
    DIRECTION INPUT ;
    USE SIGNAL ;
    ANTENNAGATEAREA 0.180700 ;
    PORT
      LAYER Metal3 ;
        RECT 184.400 55.660 184.800 56.060 ;
    END
  END Tile_X0Y1_WW4END[13]
  PIN Tile_X0Y1_WW4END[14]
    DIRECTION INPUT ;
    USE SIGNAL ;
    ANTENNAGATEAREA 0.180700 ;
    PORT
      LAYER Metal3 ;
        RECT 184.400 57.340 184.800 57.740 ;
    END
  END Tile_X0Y1_WW4END[14]
  PIN Tile_X0Y1_WW4END[15]
    DIRECTION INPUT ;
    USE SIGNAL ;
    ANTENNAGATEAREA 0.180700 ;
    PORT
      LAYER Metal3 ;
        RECT 184.400 59.020 184.800 59.420 ;
    END
  END Tile_X0Y1_WW4END[15]
  PIN Tile_X0Y1_WW4END[1]
    DIRECTION INPUT ;
    USE SIGNAL ;
    ANTENNAGATEAREA 0.705400 ;
    PORT
      LAYER Metal3 ;
        RECT 184.400 35.500 184.800 35.900 ;
    END
  END Tile_X0Y1_WW4END[1]
  PIN Tile_X0Y1_WW4END[2]
    DIRECTION INPUT ;
    USE SIGNAL ;
    ANTENNAGATEAREA 0.705400 ;
    PORT
      LAYER Metal3 ;
        RECT 184.400 37.180 184.800 37.580 ;
    END
  END Tile_X0Y1_WW4END[2]
  PIN Tile_X0Y1_WW4END[3]
    DIRECTION INPUT ;
    USE SIGNAL ;
    ANTENNAGATEAREA 0.639600 ;
    PORT
      LAYER Metal3 ;
        RECT 184.400 38.860 184.800 39.260 ;
    END
  END Tile_X0Y1_WW4END[3]
  PIN Tile_X0Y1_WW4END[4]
    DIRECTION INPUT ;
    USE SIGNAL ;
    ANTENNAGATEAREA 0.180700 ;
    PORT
      LAYER Metal3 ;
        RECT 184.400 40.540 184.800 40.940 ;
    END
  END Tile_X0Y1_WW4END[4]
  PIN Tile_X0Y1_WW4END[5]
    DIRECTION INPUT ;
    USE SIGNAL ;
    ANTENNAGATEAREA 0.180700 ;
    PORT
      LAYER Metal3 ;
        RECT 184.400 42.220 184.800 42.620 ;
    END
  END Tile_X0Y1_WW4END[5]
  PIN Tile_X0Y1_WW4END[6]
    DIRECTION INPUT ;
    USE SIGNAL ;
    ANTENNAGATEAREA 0.180700 ;
    PORT
      LAYER Metal3 ;
        RECT 184.400 43.900 184.800 44.300 ;
    END
  END Tile_X0Y1_WW4END[6]
  PIN Tile_X0Y1_WW4END[7]
    DIRECTION INPUT ;
    USE SIGNAL ;
    ANTENNAGATEAREA 0.180700 ;
    PORT
      LAYER Metal3 ;
        RECT 184.400 45.580 184.800 45.980 ;
    END
  END Tile_X0Y1_WW4END[7]
  PIN Tile_X0Y1_WW4END[8]
    DIRECTION INPUT ;
    USE SIGNAL ;
    ANTENNAGATEAREA 0.180700 ;
    PORT
      LAYER Metal3 ;
        RECT 184.400 47.260 184.800 47.660 ;
    END
  END Tile_X0Y1_WW4END[8]
  PIN Tile_X0Y1_WW4END[9]
    DIRECTION INPUT ;
    USE SIGNAL ;
    ANTENNAGATEAREA 0.180700 ;
    PORT
      LAYER Metal3 ;
        RECT 184.400 48.940 184.800 49.340 ;
    END
  END Tile_X0Y1_WW4END[9]
  PIN VGND
    DIRECTION INOUT ;
    USE GROUND ;
    PORT
      LAYER TopMetal1 ;
        RECT 24.460 0.000 26.660 430.080 ;
    END
    PORT
      LAYER TopMetal1 ;
        RECT 100.060 0.000 102.260 430.080 ;
    END
    PORT
      LAYER TopMetal1 ;
        RECT 175.660 0.000 177.860 430.080 ;
    END
  END VGND
  PIN VPWR
    DIRECTION INOUT ;
    USE POWER ;
    PORT
      LAYER TopMetal1 ;
        RECT 18.260 0.000 20.460 430.080 ;
    END
    PORT
      LAYER TopMetal1 ;
        RECT 93.860 0.000 96.060 430.080 ;
    END
    PORT
      LAYER TopMetal1 ;
        RECT 169.460 0.000 171.660 430.080 ;
    END
  END VPWR
  OBS
      LAYER GatPoly ;
        RECT 5.760 3.630 179.040 423.510 ;
      LAYER Metal1 ;
        RECT 5.760 3.560 179.040 423.580 ;
      LAYER Metal2 ;
        RECT 0.375 429.470 31.750 429.680 ;
        RECT 32.570 429.470 32.710 429.680 ;
        RECT 33.530 429.470 33.670 429.680 ;
        RECT 34.490 429.470 34.630 429.680 ;
        RECT 35.450 429.470 35.590 429.680 ;
        RECT 36.410 429.470 36.550 429.680 ;
        RECT 37.370 429.470 37.510 429.680 ;
        RECT 38.330 429.470 38.470 429.680 ;
        RECT 39.290 429.470 39.430 429.680 ;
        RECT 40.250 429.470 40.390 429.680 ;
        RECT 41.210 429.470 41.350 429.680 ;
        RECT 42.170 429.470 42.310 429.680 ;
        RECT 43.130 429.470 43.270 429.680 ;
        RECT 44.090 429.470 44.230 429.680 ;
        RECT 45.050 429.470 45.190 429.680 ;
        RECT 46.010 429.470 46.150 429.680 ;
        RECT 46.970 429.470 47.110 429.680 ;
        RECT 47.930 429.470 48.070 429.680 ;
        RECT 48.890 429.470 49.030 429.680 ;
        RECT 49.850 429.470 49.990 429.680 ;
        RECT 50.810 429.470 50.950 429.680 ;
        RECT 51.770 429.470 51.910 429.680 ;
        RECT 52.730 429.470 52.870 429.680 ;
        RECT 53.690 429.470 53.830 429.680 ;
        RECT 54.650 429.470 54.790 429.680 ;
        RECT 55.610 429.470 55.750 429.680 ;
        RECT 56.570 429.470 56.710 429.680 ;
        RECT 57.530 429.470 57.670 429.680 ;
        RECT 58.490 429.470 58.630 429.680 ;
        RECT 59.450 429.470 59.590 429.680 ;
        RECT 60.410 429.470 60.550 429.680 ;
        RECT 61.370 429.470 61.510 429.680 ;
        RECT 62.330 429.470 62.470 429.680 ;
        RECT 63.290 429.470 63.430 429.680 ;
        RECT 64.250 429.470 64.390 429.680 ;
        RECT 65.210 429.470 65.350 429.680 ;
        RECT 66.170 429.470 66.310 429.680 ;
        RECT 67.130 429.470 67.270 429.680 ;
        RECT 68.090 429.470 68.230 429.680 ;
        RECT 69.050 429.470 69.190 429.680 ;
        RECT 70.010 429.470 70.150 429.680 ;
        RECT 70.970 429.470 71.110 429.680 ;
        RECT 71.930 429.470 72.070 429.680 ;
        RECT 72.890 429.470 73.030 429.680 ;
        RECT 73.850 429.470 73.990 429.680 ;
        RECT 74.810 429.470 74.950 429.680 ;
        RECT 75.770 429.470 75.910 429.680 ;
        RECT 76.730 429.470 76.870 429.680 ;
        RECT 77.690 429.470 77.830 429.680 ;
        RECT 78.650 429.470 78.790 429.680 ;
        RECT 79.610 429.470 79.750 429.680 ;
        RECT 80.570 429.470 80.710 429.680 ;
        RECT 81.530 429.470 81.670 429.680 ;
        RECT 82.490 429.470 82.630 429.680 ;
        RECT 83.450 429.470 83.590 429.680 ;
        RECT 84.410 429.470 84.550 429.680 ;
        RECT 85.370 429.470 85.510 429.680 ;
        RECT 86.330 429.470 86.470 429.680 ;
        RECT 87.290 429.470 87.430 429.680 ;
        RECT 88.250 429.470 88.390 429.680 ;
        RECT 89.210 429.470 89.350 429.680 ;
        RECT 90.170 429.470 90.310 429.680 ;
        RECT 91.130 429.470 91.270 429.680 ;
        RECT 92.090 429.470 92.230 429.680 ;
        RECT 93.050 429.470 93.190 429.680 ;
        RECT 94.010 429.470 94.150 429.680 ;
        RECT 94.970 429.470 95.110 429.680 ;
        RECT 95.930 429.470 96.070 429.680 ;
        RECT 96.890 429.470 97.030 429.680 ;
        RECT 97.850 429.470 97.990 429.680 ;
        RECT 98.810 429.470 98.950 429.680 ;
        RECT 99.770 429.470 99.910 429.680 ;
        RECT 100.730 429.470 100.870 429.680 ;
        RECT 101.690 429.470 101.830 429.680 ;
        RECT 102.650 429.470 102.790 429.680 ;
        RECT 103.610 429.470 103.750 429.680 ;
        RECT 104.570 429.470 104.710 429.680 ;
        RECT 105.530 429.470 105.670 429.680 ;
        RECT 106.490 429.470 106.630 429.680 ;
        RECT 107.450 429.470 107.590 429.680 ;
        RECT 108.410 429.470 108.550 429.680 ;
        RECT 109.370 429.470 109.510 429.680 ;
        RECT 110.330 429.470 110.470 429.680 ;
        RECT 111.290 429.470 111.430 429.680 ;
        RECT 112.250 429.470 112.390 429.680 ;
        RECT 113.210 429.470 113.350 429.680 ;
        RECT 114.170 429.470 114.310 429.680 ;
        RECT 115.130 429.470 115.270 429.680 ;
        RECT 116.090 429.470 116.230 429.680 ;
        RECT 117.050 429.470 117.190 429.680 ;
        RECT 118.010 429.470 118.150 429.680 ;
        RECT 118.970 429.470 119.110 429.680 ;
        RECT 119.930 429.470 120.070 429.680 ;
        RECT 120.890 429.470 121.030 429.680 ;
        RECT 121.850 429.470 121.990 429.680 ;
        RECT 122.810 429.470 122.950 429.680 ;
        RECT 123.770 429.470 123.910 429.680 ;
        RECT 124.730 429.470 124.870 429.680 ;
        RECT 125.690 429.470 125.830 429.680 ;
        RECT 126.650 429.470 126.790 429.680 ;
        RECT 127.610 429.470 127.750 429.680 ;
        RECT 128.570 429.470 128.710 429.680 ;
        RECT 129.530 429.470 129.670 429.680 ;
        RECT 130.490 429.470 130.630 429.680 ;
        RECT 131.450 429.470 131.590 429.680 ;
        RECT 132.410 429.470 132.550 429.680 ;
        RECT 133.370 429.470 133.510 429.680 ;
        RECT 134.330 429.470 134.470 429.680 ;
        RECT 135.290 429.470 135.430 429.680 ;
        RECT 136.250 429.470 136.390 429.680 ;
        RECT 137.210 429.470 137.350 429.680 ;
        RECT 138.170 429.470 138.310 429.680 ;
        RECT 139.130 429.470 139.270 429.680 ;
        RECT 140.090 429.470 140.230 429.680 ;
        RECT 141.050 429.470 141.190 429.680 ;
        RECT 142.010 429.470 142.150 429.680 ;
        RECT 142.970 429.470 143.110 429.680 ;
        RECT 143.930 429.470 144.070 429.680 ;
        RECT 144.890 429.470 145.030 429.680 ;
        RECT 145.850 429.470 145.990 429.680 ;
        RECT 146.810 429.470 146.950 429.680 ;
        RECT 147.770 429.470 147.910 429.680 ;
        RECT 148.730 429.470 148.870 429.680 ;
        RECT 149.690 429.470 149.830 429.680 ;
        RECT 150.650 429.470 150.790 429.680 ;
        RECT 151.610 429.470 184.425 429.680 ;
        RECT 0.375 0.610 184.425 429.470 ;
        RECT 0.375 0.275 31.750 0.610 ;
        RECT 32.570 0.275 32.710 0.610 ;
        RECT 33.530 0.275 33.670 0.610 ;
        RECT 34.490 0.275 34.630 0.610 ;
        RECT 35.450 0.275 35.590 0.610 ;
        RECT 36.410 0.275 36.550 0.610 ;
        RECT 37.370 0.275 37.510 0.610 ;
        RECT 38.330 0.275 38.470 0.610 ;
        RECT 39.290 0.275 39.430 0.610 ;
        RECT 40.250 0.275 40.390 0.610 ;
        RECT 41.210 0.275 41.350 0.610 ;
        RECT 42.170 0.275 42.310 0.610 ;
        RECT 43.130 0.275 43.270 0.610 ;
        RECT 44.090 0.275 44.230 0.610 ;
        RECT 45.050 0.275 45.190 0.610 ;
        RECT 46.010 0.275 46.150 0.610 ;
        RECT 46.970 0.275 47.110 0.610 ;
        RECT 47.930 0.275 48.070 0.610 ;
        RECT 48.890 0.275 49.030 0.610 ;
        RECT 49.850 0.275 49.990 0.610 ;
        RECT 50.810 0.275 50.950 0.610 ;
        RECT 51.770 0.275 51.910 0.610 ;
        RECT 52.730 0.275 52.870 0.610 ;
        RECT 53.690 0.275 53.830 0.610 ;
        RECT 54.650 0.275 54.790 0.610 ;
        RECT 55.610 0.275 55.750 0.610 ;
        RECT 56.570 0.275 56.710 0.610 ;
        RECT 57.530 0.275 57.670 0.610 ;
        RECT 58.490 0.275 58.630 0.610 ;
        RECT 59.450 0.275 59.590 0.610 ;
        RECT 60.410 0.275 60.550 0.610 ;
        RECT 61.370 0.275 61.510 0.610 ;
        RECT 62.330 0.275 62.470 0.610 ;
        RECT 63.290 0.275 63.430 0.610 ;
        RECT 64.250 0.275 64.390 0.610 ;
        RECT 65.210 0.275 65.350 0.610 ;
        RECT 66.170 0.275 66.310 0.610 ;
        RECT 67.130 0.275 67.270 0.610 ;
        RECT 68.090 0.275 68.230 0.610 ;
        RECT 69.050 0.275 69.190 0.610 ;
        RECT 70.010 0.275 70.150 0.610 ;
        RECT 70.970 0.275 71.110 0.610 ;
        RECT 71.930 0.275 72.070 0.610 ;
        RECT 72.890 0.275 73.030 0.610 ;
        RECT 73.850 0.275 73.990 0.610 ;
        RECT 74.810 0.275 74.950 0.610 ;
        RECT 75.770 0.275 75.910 0.610 ;
        RECT 76.730 0.275 76.870 0.610 ;
        RECT 77.690 0.275 77.830 0.610 ;
        RECT 78.650 0.275 78.790 0.610 ;
        RECT 79.610 0.275 79.750 0.610 ;
        RECT 80.570 0.275 80.710 0.610 ;
        RECT 81.530 0.275 81.670 0.610 ;
        RECT 82.490 0.275 82.630 0.610 ;
        RECT 83.450 0.275 83.590 0.610 ;
        RECT 84.410 0.275 84.550 0.610 ;
        RECT 85.370 0.275 85.510 0.610 ;
        RECT 86.330 0.275 86.470 0.610 ;
        RECT 87.290 0.275 87.430 0.610 ;
        RECT 88.250 0.275 88.390 0.610 ;
        RECT 89.210 0.275 89.350 0.610 ;
        RECT 90.170 0.275 90.310 0.610 ;
        RECT 91.130 0.275 91.270 0.610 ;
        RECT 92.090 0.275 92.230 0.610 ;
        RECT 93.050 0.275 93.190 0.610 ;
        RECT 94.010 0.275 94.150 0.610 ;
        RECT 94.970 0.275 95.110 0.610 ;
        RECT 95.930 0.275 96.070 0.610 ;
        RECT 96.890 0.275 97.030 0.610 ;
        RECT 97.850 0.275 97.990 0.610 ;
        RECT 98.810 0.275 98.950 0.610 ;
        RECT 99.770 0.275 99.910 0.610 ;
        RECT 100.730 0.275 100.870 0.610 ;
        RECT 101.690 0.275 101.830 0.610 ;
        RECT 102.650 0.275 102.790 0.610 ;
        RECT 103.610 0.275 103.750 0.610 ;
        RECT 104.570 0.275 104.710 0.610 ;
        RECT 105.530 0.275 105.670 0.610 ;
        RECT 106.490 0.275 106.630 0.610 ;
        RECT 107.450 0.275 107.590 0.610 ;
        RECT 108.410 0.275 108.550 0.610 ;
        RECT 109.370 0.275 109.510 0.610 ;
        RECT 110.330 0.275 110.470 0.610 ;
        RECT 111.290 0.275 111.430 0.610 ;
        RECT 112.250 0.275 112.390 0.610 ;
        RECT 113.210 0.275 113.350 0.610 ;
        RECT 114.170 0.275 114.310 0.610 ;
        RECT 115.130 0.275 115.270 0.610 ;
        RECT 116.090 0.275 116.230 0.610 ;
        RECT 117.050 0.275 117.190 0.610 ;
        RECT 118.010 0.275 118.150 0.610 ;
        RECT 118.970 0.275 119.110 0.610 ;
        RECT 119.930 0.275 120.070 0.610 ;
        RECT 120.890 0.275 121.030 0.610 ;
        RECT 121.850 0.275 121.990 0.610 ;
        RECT 122.810 0.275 122.950 0.610 ;
        RECT 123.770 0.275 123.910 0.610 ;
        RECT 124.730 0.275 124.870 0.610 ;
        RECT 125.690 0.275 125.830 0.610 ;
        RECT 126.650 0.275 126.790 0.610 ;
        RECT 127.610 0.275 127.750 0.610 ;
        RECT 128.570 0.275 128.710 0.610 ;
        RECT 129.530 0.275 129.670 0.610 ;
        RECT 130.490 0.275 130.630 0.610 ;
        RECT 131.450 0.275 131.590 0.610 ;
        RECT 132.410 0.275 132.550 0.610 ;
        RECT 133.370 0.275 133.510 0.610 ;
        RECT 134.330 0.275 134.470 0.610 ;
        RECT 135.290 0.275 135.430 0.610 ;
        RECT 136.250 0.275 136.390 0.610 ;
        RECT 137.210 0.275 137.350 0.610 ;
        RECT 138.170 0.275 138.310 0.610 ;
        RECT 139.130 0.275 139.270 0.610 ;
        RECT 140.090 0.275 140.230 0.610 ;
        RECT 141.050 0.275 141.190 0.610 ;
        RECT 142.010 0.275 142.150 0.610 ;
        RECT 142.970 0.275 143.110 0.610 ;
        RECT 143.930 0.275 144.070 0.610 ;
        RECT 144.890 0.275 145.030 0.610 ;
        RECT 145.850 0.275 145.990 0.610 ;
        RECT 146.810 0.275 146.950 0.610 ;
        RECT 147.770 0.275 147.910 0.610 ;
        RECT 148.730 0.275 148.870 0.610 ;
        RECT 149.690 0.275 149.830 0.610 ;
        RECT 150.650 0.275 150.790 0.610 ;
        RECT 151.610 0.275 184.425 0.610 ;
      LAYER Metal3 ;
        RECT 0.335 429.230 184.700 429.760 ;
        RECT 0.610 428.410 184.190 429.230 ;
        RECT 0.335 427.550 184.700 428.410 ;
        RECT 0.610 426.730 184.190 427.550 ;
        RECT 0.335 425.870 184.700 426.730 ;
        RECT 0.610 425.050 184.190 425.870 ;
        RECT 0.335 424.190 184.700 425.050 ;
        RECT 0.610 423.370 184.190 424.190 ;
        RECT 0.335 422.510 184.700 423.370 ;
        RECT 0.610 421.690 184.190 422.510 ;
        RECT 0.335 420.830 184.700 421.690 ;
        RECT 0.610 420.010 184.190 420.830 ;
        RECT 0.335 419.150 184.700 420.010 ;
        RECT 0.610 418.330 184.190 419.150 ;
        RECT 0.335 417.470 184.700 418.330 ;
        RECT 0.610 416.650 184.190 417.470 ;
        RECT 0.335 415.790 184.700 416.650 ;
        RECT 0.610 414.970 184.190 415.790 ;
        RECT 0.335 414.110 184.700 414.970 ;
        RECT 0.610 413.290 184.190 414.110 ;
        RECT 0.335 412.430 184.700 413.290 ;
        RECT 0.610 411.610 184.190 412.430 ;
        RECT 0.335 410.750 184.700 411.610 ;
        RECT 0.610 409.930 184.190 410.750 ;
        RECT 0.335 409.070 184.700 409.930 ;
        RECT 0.610 408.250 184.190 409.070 ;
        RECT 0.335 407.390 184.700 408.250 ;
        RECT 0.610 406.570 184.190 407.390 ;
        RECT 0.335 405.710 184.700 406.570 ;
        RECT 0.610 404.890 184.190 405.710 ;
        RECT 0.335 404.030 184.700 404.890 ;
        RECT 0.610 403.210 184.190 404.030 ;
        RECT 0.335 402.350 184.700 403.210 ;
        RECT 0.610 401.530 184.190 402.350 ;
        RECT 0.335 400.670 184.700 401.530 ;
        RECT 0.610 399.850 184.190 400.670 ;
        RECT 0.335 398.990 184.700 399.850 ;
        RECT 0.610 398.170 184.190 398.990 ;
        RECT 0.335 397.310 184.700 398.170 ;
        RECT 0.610 396.490 184.190 397.310 ;
        RECT 0.335 395.630 184.700 396.490 ;
        RECT 0.610 394.810 184.190 395.630 ;
        RECT 0.335 393.950 184.700 394.810 ;
        RECT 0.610 393.130 184.190 393.950 ;
        RECT 0.335 392.270 184.700 393.130 ;
        RECT 0.610 391.450 184.190 392.270 ;
        RECT 0.335 390.590 184.700 391.450 ;
        RECT 0.610 389.770 184.190 390.590 ;
        RECT 0.335 388.910 184.700 389.770 ;
        RECT 0.610 388.090 184.190 388.910 ;
        RECT 0.335 387.230 184.700 388.090 ;
        RECT 0.610 386.410 184.190 387.230 ;
        RECT 0.335 385.550 184.700 386.410 ;
        RECT 0.610 384.730 184.190 385.550 ;
        RECT 0.335 383.870 184.700 384.730 ;
        RECT 0.610 383.050 184.190 383.870 ;
        RECT 0.335 382.190 184.700 383.050 ;
        RECT 0.610 381.370 184.190 382.190 ;
        RECT 0.335 380.510 184.700 381.370 ;
        RECT 0.610 379.690 184.190 380.510 ;
        RECT 0.335 378.830 184.700 379.690 ;
        RECT 0.610 378.010 184.190 378.830 ;
        RECT 0.335 377.150 184.700 378.010 ;
        RECT 0.610 376.330 184.190 377.150 ;
        RECT 0.335 375.470 184.700 376.330 ;
        RECT 0.610 374.650 184.190 375.470 ;
        RECT 0.335 373.790 184.700 374.650 ;
        RECT 0.610 372.970 184.190 373.790 ;
        RECT 0.335 372.110 184.700 372.970 ;
        RECT 0.610 371.290 184.190 372.110 ;
        RECT 0.335 370.430 184.700 371.290 ;
        RECT 0.610 369.610 184.190 370.430 ;
        RECT 0.335 368.750 184.700 369.610 ;
        RECT 0.610 367.930 184.190 368.750 ;
        RECT 0.335 367.070 184.700 367.930 ;
        RECT 0.610 366.250 184.190 367.070 ;
        RECT 0.335 365.390 184.700 366.250 ;
        RECT 0.610 364.570 184.190 365.390 ;
        RECT 0.335 363.710 184.700 364.570 ;
        RECT 0.610 362.890 184.190 363.710 ;
        RECT 0.335 362.030 184.700 362.890 ;
        RECT 0.610 361.210 184.190 362.030 ;
        RECT 0.335 360.350 184.700 361.210 ;
        RECT 0.610 359.530 184.190 360.350 ;
        RECT 0.335 358.670 184.700 359.530 ;
        RECT 0.610 357.850 184.190 358.670 ;
        RECT 0.335 356.990 184.700 357.850 ;
        RECT 0.610 356.170 184.190 356.990 ;
        RECT 0.335 355.310 184.700 356.170 ;
        RECT 0.610 354.490 184.190 355.310 ;
        RECT 0.335 353.630 184.700 354.490 ;
        RECT 0.610 352.810 184.190 353.630 ;
        RECT 0.335 351.950 184.700 352.810 ;
        RECT 0.610 351.130 184.190 351.950 ;
        RECT 0.335 350.270 184.700 351.130 ;
        RECT 0.610 349.450 184.190 350.270 ;
        RECT 0.335 348.590 184.700 349.450 ;
        RECT 0.610 347.770 184.190 348.590 ;
        RECT 0.335 346.910 184.700 347.770 ;
        RECT 0.610 346.090 184.190 346.910 ;
        RECT 0.335 345.230 184.700 346.090 ;
        RECT 0.610 344.410 184.190 345.230 ;
        RECT 0.335 343.550 184.700 344.410 ;
        RECT 0.610 342.730 184.190 343.550 ;
        RECT 0.335 341.870 184.700 342.730 ;
        RECT 0.610 341.050 184.190 341.870 ;
        RECT 0.335 340.190 184.700 341.050 ;
        RECT 0.610 339.370 184.190 340.190 ;
        RECT 0.335 338.510 184.700 339.370 ;
        RECT 0.610 337.690 184.190 338.510 ;
        RECT 0.335 336.830 184.700 337.690 ;
        RECT 0.610 336.010 184.190 336.830 ;
        RECT 0.335 335.150 184.700 336.010 ;
        RECT 0.610 334.330 184.190 335.150 ;
        RECT 0.335 333.470 184.700 334.330 ;
        RECT 0.610 332.650 184.190 333.470 ;
        RECT 0.335 331.790 184.700 332.650 ;
        RECT 0.610 330.970 184.190 331.790 ;
        RECT 0.335 330.110 184.700 330.970 ;
        RECT 0.610 329.290 184.190 330.110 ;
        RECT 0.335 328.430 184.700 329.290 ;
        RECT 0.610 327.610 184.190 328.430 ;
        RECT 0.335 326.750 184.700 327.610 ;
        RECT 0.610 325.930 184.190 326.750 ;
        RECT 0.335 325.070 184.700 325.930 ;
        RECT 0.610 324.250 184.190 325.070 ;
        RECT 0.335 323.390 184.700 324.250 ;
        RECT 0.610 322.570 184.190 323.390 ;
        RECT 0.335 321.710 184.700 322.570 ;
        RECT 0.610 320.890 184.190 321.710 ;
        RECT 0.335 320.030 184.700 320.890 ;
        RECT 0.610 319.210 184.190 320.030 ;
        RECT 0.335 318.350 184.700 319.210 ;
        RECT 0.610 317.530 184.190 318.350 ;
        RECT 0.335 316.670 184.700 317.530 ;
        RECT 0.610 315.850 184.190 316.670 ;
        RECT 0.335 314.990 184.700 315.850 ;
        RECT 0.610 314.170 184.190 314.990 ;
        RECT 0.335 313.310 184.700 314.170 ;
        RECT 0.610 312.490 184.190 313.310 ;
        RECT 0.335 311.630 184.700 312.490 ;
        RECT 0.610 310.810 184.190 311.630 ;
        RECT 0.335 309.950 184.700 310.810 ;
        RECT 0.610 309.130 184.190 309.950 ;
        RECT 0.335 308.270 184.700 309.130 ;
        RECT 0.610 307.450 184.190 308.270 ;
        RECT 0.335 306.590 184.700 307.450 ;
        RECT 0.610 305.770 184.190 306.590 ;
        RECT 0.335 304.910 184.700 305.770 ;
        RECT 0.610 304.090 184.190 304.910 ;
        RECT 0.335 303.230 184.700 304.090 ;
        RECT 0.610 302.410 184.190 303.230 ;
        RECT 0.335 301.550 184.700 302.410 ;
        RECT 0.610 300.730 184.190 301.550 ;
        RECT 0.335 299.870 184.700 300.730 ;
        RECT 0.610 299.050 184.190 299.870 ;
        RECT 0.335 298.190 184.700 299.050 ;
        RECT 0.610 297.370 184.190 298.190 ;
        RECT 0.335 296.510 184.700 297.370 ;
        RECT 0.610 295.690 184.190 296.510 ;
        RECT 0.335 294.830 184.700 295.690 ;
        RECT 0.610 294.010 184.190 294.830 ;
        RECT 0.335 293.150 184.700 294.010 ;
        RECT 0.610 292.330 184.190 293.150 ;
        RECT 0.335 291.470 184.700 292.330 ;
        RECT 0.610 290.650 184.190 291.470 ;
        RECT 0.335 289.790 184.700 290.650 ;
        RECT 0.610 288.970 184.190 289.790 ;
        RECT 0.335 288.110 184.700 288.970 ;
        RECT 0.610 287.290 184.190 288.110 ;
        RECT 0.335 286.430 184.700 287.290 ;
        RECT 0.610 285.610 184.190 286.430 ;
        RECT 0.335 284.750 184.700 285.610 ;
        RECT 0.610 283.930 184.190 284.750 ;
        RECT 0.335 283.070 184.700 283.930 ;
        RECT 0.610 282.250 184.190 283.070 ;
        RECT 0.335 281.390 184.700 282.250 ;
        RECT 0.610 280.570 184.190 281.390 ;
        RECT 0.335 279.710 184.700 280.570 ;
        RECT 0.610 278.890 184.190 279.710 ;
        RECT 0.335 278.030 184.700 278.890 ;
        RECT 0.610 277.210 184.190 278.030 ;
        RECT 0.335 276.350 184.700 277.210 ;
        RECT 0.610 275.530 184.190 276.350 ;
        RECT 0.335 274.670 184.700 275.530 ;
        RECT 0.610 273.850 184.190 274.670 ;
        RECT 0.335 272.990 184.700 273.850 ;
        RECT 0.610 272.170 184.190 272.990 ;
        RECT 0.335 271.310 184.700 272.170 ;
        RECT 0.610 270.490 184.190 271.310 ;
        RECT 0.335 269.630 184.700 270.490 ;
        RECT 0.610 268.810 184.190 269.630 ;
        RECT 0.335 267.950 184.700 268.810 ;
        RECT 0.610 267.130 184.190 267.950 ;
        RECT 0.335 266.270 184.700 267.130 ;
        RECT 0.610 265.450 184.190 266.270 ;
        RECT 0.335 264.590 184.700 265.450 ;
        RECT 0.610 263.770 184.190 264.590 ;
        RECT 0.335 262.910 184.700 263.770 ;
        RECT 0.610 262.090 184.190 262.910 ;
        RECT 0.335 261.230 184.700 262.090 ;
        RECT 0.610 260.410 184.190 261.230 ;
        RECT 0.335 259.550 184.700 260.410 ;
        RECT 0.610 258.730 184.190 259.550 ;
        RECT 0.335 257.870 184.700 258.730 ;
        RECT 0.610 257.050 184.190 257.870 ;
        RECT 0.335 256.190 184.700 257.050 ;
        RECT 0.610 255.370 184.190 256.190 ;
        RECT 0.335 254.510 184.700 255.370 ;
        RECT 0.610 253.690 184.190 254.510 ;
        RECT 0.335 252.830 184.700 253.690 ;
        RECT 0.610 252.010 184.190 252.830 ;
        RECT 0.335 251.150 184.700 252.010 ;
        RECT 0.610 250.330 184.190 251.150 ;
        RECT 0.335 249.470 184.700 250.330 ;
        RECT 0.610 248.650 184.190 249.470 ;
        RECT 0.335 247.790 184.700 248.650 ;
        RECT 0.610 246.970 184.190 247.790 ;
        RECT 0.335 246.110 184.700 246.970 ;
        RECT 0.610 245.290 184.190 246.110 ;
        RECT 0.335 244.430 184.700 245.290 ;
        RECT 0.610 243.610 184.190 244.430 ;
        RECT 0.335 242.750 184.700 243.610 ;
        RECT 0.610 241.930 184.190 242.750 ;
        RECT 0.335 241.070 184.700 241.930 ;
        RECT 0.610 240.250 184.190 241.070 ;
        RECT 0.335 239.390 184.700 240.250 ;
        RECT 0.610 238.570 184.190 239.390 ;
        RECT 0.335 237.710 184.700 238.570 ;
        RECT 0.610 236.890 184.190 237.710 ;
        RECT 0.335 236.030 184.700 236.890 ;
        RECT 0.610 235.210 184.190 236.030 ;
        RECT 0.335 234.350 184.700 235.210 ;
        RECT 0.610 233.530 184.190 234.350 ;
        RECT 0.335 232.670 184.700 233.530 ;
        RECT 0.610 231.850 184.190 232.670 ;
        RECT 0.335 230.990 184.700 231.850 ;
        RECT 0.610 230.170 184.190 230.990 ;
        RECT 0.335 229.310 184.700 230.170 ;
        RECT 0.610 228.490 184.190 229.310 ;
        RECT 0.335 227.630 184.700 228.490 ;
        RECT 0.610 226.810 184.190 227.630 ;
        RECT 0.335 225.950 184.700 226.810 ;
        RECT 0.610 225.130 184.190 225.950 ;
        RECT 0.335 224.270 184.700 225.130 ;
        RECT 0.610 223.450 184.190 224.270 ;
        RECT 0.335 222.590 184.700 223.450 ;
        RECT 0.610 221.770 184.190 222.590 ;
        RECT 0.335 220.910 184.700 221.770 ;
        RECT 0.610 220.090 184.190 220.910 ;
        RECT 0.335 219.230 184.700 220.090 ;
        RECT 0.610 218.410 184.190 219.230 ;
        RECT 0.335 217.550 184.700 218.410 ;
        RECT 0.610 216.730 184.190 217.550 ;
        RECT 0.335 215.870 184.700 216.730 ;
        RECT 0.610 215.050 184.190 215.870 ;
        RECT 0.335 214.190 184.700 215.050 ;
        RECT 0.610 213.370 184.190 214.190 ;
        RECT 0.335 212.510 184.700 213.370 ;
        RECT 0.610 211.690 184.190 212.510 ;
        RECT 0.335 210.830 184.700 211.690 ;
        RECT 0.610 210.010 184.190 210.830 ;
        RECT 0.335 209.150 184.700 210.010 ;
        RECT 0.610 208.330 184.190 209.150 ;
        RECT 0.335 207.470 184.700 208.330 ;
        RECT 0.610 206.650 184.190 207.470 ;
        RECT 0.335 205.790 184.700 206.650 ;
        RECT 0.610 204.970 184.190 205.790 ;
        RECT 0.335 204.110 184.700 204.970 ;
        RECT 0.610 203.290 184.190 204.110 ;
        RECT 0.335 202.430 184.700 203.290 ;
        RECT 0.610 201.610 184.190 202.430 ;
        RECT 0.335 200.750 184.700 201.610 ;
        RECT 0.610 199.930 184.190 200.750 ;
        RECT 0.335 199.070 184.700 199.930 ;
        RECT 0.610 198.250 184.190 199.070 ;
        RECT 0.335 197.390 184.700 198.250 ;
        RECT 0.610 196.570 184.190 197.390 ;
        RECT 0.335 195.710 184.700 196.570 ;
        RECT 0.610 194.890 184.190 195.710 ;
        RECT 0.335 194.030 184.700 194.890 ;
        RECT 0.610 193.210 184.190 194.030 ;
        RECT 0.335 192.350 184.700 193.210 ;
        RECT 0.610 191.530 184.190 192.350 ;
        RECT 0.335 190.670 184.700 191.530 ;
        RECT 0.610 189.850 184.190 190.670 ;
        RECT 0.335 188.990 184.700 189.850 ;
        RECT 0.610 188.170 184.190 188.990 ;
        RECT 0.335 187.310 184.700 188.170 ;
        RECT 0.610 186.490 184.190 187.310 ;
        RECT 0.335 185.630 184.700 186.490 ;
        RECT 0.610 184.810 184.190 185.630 ;
        RECT 0.335 183.950 184.700 184.810 ;
        RECT 0.610 183.130 184.190 183.950 ;
        RECT 0.335 182.270 184.700 183.130 ;
        RECT 0.610 181.450 184.190 182.270 ;
        RECT 0.335 180.590 184.700 181.450 ;
        RECT 0.610 179.770 184.190 180.590 ;
        RECT 0.335 178.910 184.700 179.770 ;
        RECT 0.610 178.090 184.190 178.910 ;
        RECT 0.335 177.230 184.700 178.090 ;
        RECT 0.610 176.410 184.190 177.230 ;
        RECT 0.335 175.550 184.700 176.410 ;
        RECT 0.610 174.730 184.190 175.550 ;
        RECT 0.335 173.870 184.700 174.730 ;
        RECT 0.610 173.050 184.190 173.870 ;
        RECT 0.335 172.190 184.700 173.050 ;
        RECT 0.610 171.370 184.190 172.190 ;
        RECT 0.335 170.510 184.700 171.370 ;
        RECT 0.610 169.690 184.190 170.510 ;
        RECT 0.335 168.830 184.700 169.690 ;
        RECT 0.610 168.010 184.190 168.830 ;
        RECT 0.335 167.150 184.700 168.010 ;
        RECT 0.610 166.330 184.190 167.150 ;
        RECT 0.335 165.470 184.700 166.330 ;
        RECT 0.610 164.650 184.190 165.470 ;
        RECT 0.335 163.790 184.700 164.650 ;
        RECT 0.610 162.970 184.190 163.790 ;
        RECT 0.335 162.110 184.700 162.970 ;
        RECT 0.610 161.290 184.190 162.110 ;
        RECT 0.335 160.430 184.700 161.290 ;
        RECT 0.610 159.610 184.190 160.430 ;
        RECT 0.335 158.750 184.700 159.610 ;
        RECT 0.610 157.930 184.190 158.750 ;
        RECT 0.335 157.070 184.700 157.930 ;
        RECT 0.610 156.250 184.190 157.070 ;
        RECT 0.335 155.390 184.700 156.250 ;
        RECT 0.610 154.570 184.190 155.390 ;
        RECT 0.335 153.710 184.700 154.570 ;
        RECT 0.610 152.890 184.190 153.710 ;
        RECT 0.335 152.030 184.700 152.890 ;
        RECT 0.610 151.210 184.190 152.030 ;
        RECT 0.335 150.350 184.700 151.210 ;
        RECT 0.610 149.530 184.190 150.350 ;
        RECT 0.335 148.670 184.700 149.530 ;
        RECT 0.610 147.850 184.190 148.670 ;
        RECT 0.335 146.990 184.700 147.850 ;
        RECT 0.610 146.170 184.190 146.990 ;
        RECT 0.335 145.310 184.700 146.170 ;
        RECT 0.610 144.490 184.190 145.310 ;
        RECT 0.335 143.630 184.700 144.490 ;
        RECT 0.610 142.810 184.190 143.630 ;
        RECT 0.335 141.950 184.700 142.810 ;
        RECT 0.610 141.130 184.190 141.950 ;
        RECT 0.335 140.270 184.700 141.130 ;
        RECT 0.610 139.450 184.190 140.270 ;
        RECT 0.335 138.590 184.700 139.450 ;
        RECT 0.610 137.770 184.190 138.590 ;
        RECT 0.335 136.910 184.700 137.770 ;
        RECT 0.610 136.090 184.190 136.910 ;
        RECT 0.335 135.230 184.700 136.090 ;
        RECT 0.610 134.410 184.190 135.230 ;
        RECT 0.335 133.550 184.700 134.410 ;
        RECT 0.610 132.730 184.190 133.550 ;
        RECT 0.335 131.870 184.700 132.730 ;
        RECT 0.610 131.050 184.190 131.870 ;
        RECT 0.335 130.190 184.700 131.050 ;
        RECT 0.610 129.370 184.190 130.190 ;
        RECT 0.335 128.510 184.700 129.370 ;
        RECT 0.610 127.690 184.190 128.510 ;
        RECT 0.335 126.830 184.700 127.690 ;
        RECT 0.610 126.010 184.190 126.830 ;
        RECT 0.335 125.150 184.700 126.010 ;
        RECT 0.610 124.330 184.190 125.150 ;
        RECT 0.335 123.470 184.700 124.330 ;
        RECT 0.610 122.650 184.190 123.470 ;
        RECT 0.335 121.790 184.700 122.650 ;
        RECT 0.610 120.970 184.190 121.790 ;
        RECT 0.335 120.110 184.700 120.970 ;
        RECT 0.610 119.290 184.190 120.110 ;
        RECT 0.335 118.430 184.700 119.290 ;
        RECT 0.610 117.610 184.190 118.430 ;
        RECT 0.335 116.750 184.700 117.610 ;
        RECT 0.610 115.930 184.190 116.750 ;
        RECT 0.335 115.070 184.700 115.930 ;
        RECT 0.610 114.250 184.190 115.070 ;
        RECT 0.335 113.390 184.700 114.250 ;
        RECT 0.610 112.570 184.190 113.390 ;
        RECT 0.335 111.710 184.700 112.570 ;
        RECT 0.610 110.890 184.190 111.710 ;
        RECT 0.335 110.030 184.700 110.890 ;
        RECT 0.610 109.210 184.190 110.030 ;
        RECT 0.335 108.350 184.700 109.210 ;
        RECT 0.610 107.530 184.190 108.350 ;
        RECT 0.335 106.670 184.700 107.530 ;
        RECT 0.610 105.850 184.190 106.670 ;
        RECT 0.335 104.990 184.700 105.850 ;
        RECT 0.610 104.170 184.190 104.990 ;
        RECT 0.335 103.310 184.700 104.170 ;
        RECT 0.610 102.490 184.190 103.310 ;
        RECT 0.335 101.630 184.700 102.490 ;
        RECT 0.610 100.810 184.190 101.630 ;
        RECT 0.335 99.950 184.700 100.810 ;
        RECT 0.610 99.130 184.190 99.950 ;
        RECT 0.335 98.270 184.700 99.130 ;
        RECT 0.610 97.450 184.190 98.270 ;
        RECT 0.335 96.590 184.700 97.450 ;
        RECT 0.610 95.770 184.190 96.590 ;
        RECT 0.335 94.910 184.700 95.770 ;
        RECT 0.610 94.090 184.190 94.910 ;
        RECT 0.335 93.230 184.700 94.090 ;
        RECT 0.610 92.410 184.190 93.230 ;
        RECT 0.335 91.550 184.700 92.410 ;
        RECT 0.610 90.730 184.190 91.550 ;
        RECT 0.335 89.870 184.700 90.730 ;
        RECT 0.610 89.050 184.190 89.870 ;
        RECT 0.335 88.190 184.700 89.050 ;
        RECT 0.610 87.370 184.190 88.190 ;
        RECT 0.335 86.510 184.700 87.370 ;
        RECT 0.610 85.690 184.190 86.510 ;
        RECT 0.335 84.830 184.700 85.690 ;
        RECT 0.610 84.010 184.190 84.830 ;
        RECT 0.335 83.150 184.700 84.010 ;
        RECT 0.610 82.330 184.190 83.150 ;
        RECT 0.335 81.470 184.700 82.330 ;
        RECT 0.610 80.650 184.190 81.470 ;
        RECT 0.335 79.790 184.700 80.650 ;
        RECT 0.610 78.970 184.190 79.790 ;
        RECT 0.335 78.110 184.700 78.970 ;
        RECT 0.610 77.290 184.190 78.110 ;
        RECT 0.335 76.430 184.700 77.290 ;
        RECT 0.610 75.610 184.190 76.430 ;
        RECT 0.335 74.750 184.700 75.610 ;
        RECT 0.610 73.930 184.190 74.750 ;
        RECT 0.335 73.070 184.700 73.930 ;
        RECT 0.610 72.250 184.190 73.070 ;
        RECT 0.335 71.390 184.700 72.250 ;
        RECT 0.610 70.570 184.190 71.390 ;
        RECT 0.335 69.710 184.700 70.570 ;
        RECT 0.610 68.890 184.190 69.710 ;
        RECT 0.335 68.030 184.700 68.890 ;
        RECT 0.610 67.210 184.190 68.030 ;
        RECT 0.335 66.350 184.700 67.210 ;
        RECT 0.610 65.530 184.190 66.350 ;
        RECT 0.335 64.670 184.700 65.530 ;
        RECT 0.610 63.850 184.190 64.670 ;
        RECT 0.335 62.990 184.700 63.850 ;
        RECT 0.610 62.170 184.190 62.990 ;
        RECT 0.335 61.310 184.700 62.170 ;
        RECT 0.610 60.490 184.190 61.310 ;
        RECT 0.335 59.630 184.700 60.490 ;
        RECT 0.610 58.810 184.190 59.630 ;
        RECT 0.335 57.950 184.700 58.810 ;
        RECT 0.610 57.130 184.190 57.950 ;
        RECT 0.335 56.270 184.700 57.130 ;
        RECT 0.610 55.450 184.190 56.270 ;
        RECT 0.335 54.590 184.700 55.450 ;
        RECT 0.610 53.770 184.190 54.590 ;
        RECT 0.335 52.910 184.700 53.770 ;
        RECT 0.610 52.090 184.190 52.910 ;
        RECT 0.335 51.230 184.700 52.090 ;
        RECT 0.610 50.410 184.190 51.230 ;
        RECT 0.335 49.550 184.700 50.410 ;
        RECT 0.610 48.730 184.190 49.550 ;
        RECT 0.335 47.870 184.700 48.730 ;
        RECT 0.610 47.050 184.190 47.870 ;
        RECT 0.335 46.190 184.700 47.050 ;
        RECT 0.610 45.370 184.190 46.190 ;
        RECT 0.335 44.510 184.700 45.370 ;
        RECT 0.610 43.690 184.190 44.510 ;
        RECT 0.335 42.830 184.700 43.690 ;
        RECT 0.610 42.010 184.190 42.830 ;
        RECT 0.335 41.150 184.700 42.010 ;
        RECT 0.610 40.330 184.190 41.150 ;
        RECT 0.335 39.470 184.700 40.330 ;
        RECT 0.610 38.650 184.190 39.470 ;
        RECT 0.335 37.790 184.700 38.650 ;
        RECT 0.610 36.970 184.190 37.790 ;
        RECT 0.335 36.110 184.700 36.970 ;
        RECT 0.610 35.290 184.190 36.110 ;
        RECT 0.335 34.430 184.700 35.290 ;
        RECT 0.610 33.610 184.190 34.430 ;
        RECT 0.335 32.750 184.700 33.610 ;
        RECT 0.610 31.930 184.190 32.750 ;
        RECT 0.335 31.070 184.700 31.930 ;
        RECT 0.610 30.250 184.190 31.070 ;
        RECT 0.335 29.390 184.700 30.250 ;
        RECT 0.610 28.570 184.190 29.390 ;
        RECT 0.335 27.710 184.700 28.570 ;
        RECT 0.610 26.890 184.190 27.710 ;
        RECT 0.335 26.030 184.700 26.890 ;
        RECT 0.610 25.210 184.190 26.030 ;
        RECT 0.335 24.350 184.700 25.210 ;
        RECT 0.610 23.530 184.190 24.350 ;
        RECT 0.335 22.670 184.700 23.530 ;
        RECT 0.610 21.850 184.190 22.670 ;
        RECT 0.335 20.990 184.700 21.850 ;
        RECT 0.610 20.170 184.190 20.990 ;
        RECT 0.335 19.310 184.700 20.170 ;
        RECT 0.610 18.490 184.190 19.310 ;
        RECT 0.335 17.630 184.700 18.490 ;
        RECT 0.610 16.810 184.190 17.630 ;
        RECT 0.335 15.950 184.700 16.810 ;
        RECT 0.610 15.130 184.190 15.950 ;
        RECT 0.335 14.270 184.700 15.130 ;
        RECT 0.610 13.450 184.190 14.270 ;
        RECT 0.335 12.590 184.700 13.450 ;
        RECT 0.610 11.770 184.190 12.590 ;
        RECT 0.335 10.910 184.700 11.770 ;
        RECT 0.610 10.090 184.190 10.910 ;
        RECT 0.335 9.230 184.700 10.090 ;
        RECT 0.610 8.410 184.190 9.230 ;
        RECT 0.335 7.550 184.700 8.410 ;
        RECT 0.610 6.730 184.190 7.550 ;
        RECT 0.335 5.870 184.700 6.730 ;
        RECT 0.610 5.050 184.190 5.870 ;
        RECT 0.335 4.190 184.700 5.050 ;
        RECT 0.610 3.370 184.190 4.190 ;
        RECT 0.335 2.510 184.700 3.370 ;
        RECT 0.610 1.690 184.190 2.510 ;
        RECT 0.335 0.830 184.700 1.690 ;
        RECT 0.610 0.315 184.190 0.830 ;
      LAYER Metal4 ;
        RECT 0.375 0.265 184.420 428.965 ;
      LAYER Metal5 ;
        RECT 0.335 0.320 183.505 423.670 ;
      LAYER TopMetal1 ;
        RECT 48.700 1.700 92.220 423.760 ;
        RECT 97.700 1.700 98.420 423.760 ;
        RECT 103.900 1.700 155.220 423.760 ;
  END
END DSP
END LIBRARY

